VERSION 5.8 ;
BUSBITCHARS "[]" ;
DIVIDERCHAR "/" ;
UNITS
    DATABASE MICRONS 1000 ;
END UNITS

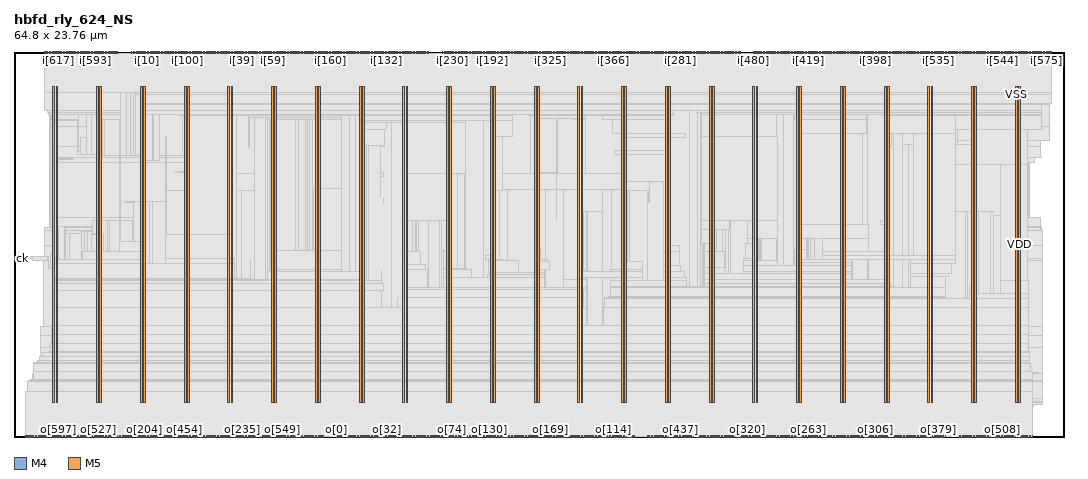
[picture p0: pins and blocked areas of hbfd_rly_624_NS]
MACRO hbfd_rly_624_NS
  FOREIGN hbfd_rly_624_NS 0 0 ;
  CLASS BLOCK ;
  SIZE 64.8 BY 23.76 ;
  PIN ck
    DIRECTION INPUT ;
    USE SIGNAL ;
    PORT
      LAYER M4 ;
        RECT  0 10.992 0.084 11.016 ;
    END
  END ck
  PIN i[0]
    DIRECTION INPUT ;
    USE SIGNAL ;
    PORT
      LAYER M5 ;
        RECT  7.248 23.676 7.272 23.76 ;
    END
  END i[0]
  PIN i[100]
    DIRECTION INPUT ;
    USE SIGNAL ;
    PORT
      LAYER M5 ;
        RECT  10.704 23.676 10.728 23.76 ;
    END
  END i[100]
  PIN i[101]
    DIRECTION INPUT ;
    USE SIGNAL ;
    PORT
      LAYER M5 ;
        RECT  10.8 23.676 10.824 23.76 ;
    END
  END i[101]
  PIN i[102]
    DIRECTION INPUT ;
    USE SIGNAL ;
    PORT
      LAYER M5 ;
        RECT  10.896 23.676 10.92 23.76 ;
    END
  END i[102]
  PIN i[103]
    DIRECTION INPUT ;
    USE SIGNAL ;
    PORT
      LAYER M5 ;
        RECT  10.992 23.676 11.016 23.76 ;
    END
  END i[103]
  PIN i[104]
    DIRECTION INPUT ;
    USE SIGNAL ;
    PORT
      LAYER M5 ;
        RECT  11.088 23.676 11.112 23.76 ;
    END
  END i[104]
  PIN i[105]
    DIRECTION INPUT ;
    USE SIGNAL ;
    PORT
      LAYER M5 ;
        RECT  11.184 23.676 11.208 23.76 ;
    END
  END i[105]
  PIN i[106]
    DIRECTION INPUT ;
    USE SIGNAL ;
    PORT
      LAYER M5 ;
        RECT  11.28 23.676 11.304 23.76 ;
    END
  END i[106]
  PIN i[107]
    DIRECTION INPUT ;
    USE SIGNAL ;
    PORT
      LAYER M5 ;
        RECT  11.376 23.676 11.4 23.76 ;
    END
  END i[107]
  PIN i[108]
    DIRECTION INPUT ;
    USE SIGNAL ;
    PORT
      LAYER M5 ;
        RECT  11.472 23.676 11.496 23.76 ;
    END
  END i[108]
  PIN i[109]
    DIRECTION INPUT ;
    USE SIGNAL ;
    PORT
      LAYER M5 ;
        RECT  11.568 23.676 11.592 23.76 ;
    END
  END i[109]
  PIN i[10]
    DIRECTION INPUT ;
    USE SIGNAL ;
    PORT
      LAYER M5 ;
        RECT  8.208 23.676 8.232 23.76 ;
    END
  END i[10]
  PIN i[110]
    DIRECTION INPUT ;
    USE SIGNAL ;
    PORT
      LAYER M5 ;
        RECT  11.664 23.676 11.688 23.76 ;
    END
  END i[110]
  PIN i[111]
    DIRECTION INPUT ;
    USE SIGNAL ;
    PORT
      LAYER M5 ;
        RECT  11.76 23.676 11.784 23.76 ;
    END
  END i[111]
  PIN i[112]
    DIRECTION INPUT ;
    USE SIGNAL ;
    PORT
      LAYER M5 ;
        RECT  11.856 23.676 11.88 23.76 ;
    END
  END i[112]
  PIN i[113]
    DIRECTION INPUT ;
    USE SIGNAL ;
    PORT
      LAYER M5 ;
        RECT  11.952 23.676 11.976 23.76 ;
    END
  END i[113]
  PIN i[114]
    DIRECTION INPUT ;
    USE SIGNAL ;
    PORT
      LAYER M5 ;
        RECT  12.048 23.676 12.072 23.76 ;
    END
  END i[114]
  PIN i[115]
    DIRECTION INPUT ;
    USE SIGNAL ;
    PORT
      LAYER M5 ;
        RECT  12.144 23.676 12.168 23.76 ;
    END
  END i[115]
  PIN i[116]
    DIRECTION INPUT ;
    USE SIGNAL ;
    PORT
      LAYER M5 ;
        RECT  12.24 23.676 12.264 23.76 ;
    END
  END i[116]
  PIN i[117]
    DIRECTION INPUT ;
    USE SIGNAL ;
    PORT
      LAYER M5 ;
        RECT  12.336 23.676 12.36 23.76 ;
    END
  END i[117]
  PIN i[118]
    DIRECTION INPUT ;
    USE SIGNAL ;
    PORT
      LAYER M5 ;
        RECT  12.432 23.676 12.456 23.76 ;
    END
  END i[118]
  PIN i[119]
    DIRECTION INPUT ;
    USE SIGNAL ;
    PORT
      LAYER M5 ;
        RECT  12.528 23.676 12.552 23.76 ;
    END
  END i[119]
  PIN i[11]
    DIRECTION INPUT ;
    USE SIGNAL ;
    PORT
      LAYER M5 ;
        RECT  8.304 23.676 8.328 23.76 ;
    END
  END i[11]
  PIN i[120]
    DIRECTION INPUT ;
    USE SIGNAL ;
    PORT
      LAYER M5 ;
        RECT  12.624 23.676 12.648 23.76 ;
    END
  END i[120]
  PIN i[121]
    DIRECTION INPUT ;
    USE SIGNAL ;
    PORT
      LAYER M5 ;
        RECT  12.72 23.676 12.744 23.76 ;
    END
  END i[121]
  PIN i[122]
    DIRECTION INPUT ;
    USE SIGNAL ;
    PORT
      LAYER M5 ;
        RECT  12.816 23.676 12.84 23.76 ;
    END
  END i[122]
  PIN i[123]
    DIRECTION INPUT ;
    USE SIGNAL ;
    PORT
      LAYER M5 ;
        RECT  12.912 23.676 12.936 23.76 ;
    END
  END i[123]
  PIN i[124]
    DIRECTION INPUT ;
    USE SIGNAL ;
    PORT
      LAYER M5 ;
        RECT  13.008 23.676 13.032 23.76 ;
    END
  END i[124]
  PIN i[125]
    DIRECTION INPUT ;
    USE SIGNAL ;
    PORT
      LAYER M5 ;
        RECT  13.104 23.676 13.128 23.76 ;
    END
  END i[125]
  PIN i[126]
    DIRECTION INPUT ;
    USE SIGNAL ;
    PORT
      LAYER M5 ;
        RECT  13.2 23.676 13.224 23.76 ;
    END
  END i[126]
  PIN i[127]
    DIRECTION INPUT ;
    USE SIGNAL ;
    PORT
      LAYER M5 ;
        RECT  13.296 23.676 13.32 23.76 ;
    END
  END i[127]
  PIN i[128]
    DIRECTION INPUT ;
    USE SIGNAL ;
    PORT
      LAYER M5 ;
        RECT  22.608 23.676 22.632 23.76 ;
    END
  END i[128]
  PIN i[129]
    DIRECTION INPUT ;
    USE SIGNAL ;
    PORT
      LAYER M5 ;
        RECT  22.704 23.676 22.728 23.76 ;
    END
  END i[129]
  PIN i[12]
    DIRECTION INPUT ;
    USE SIGNAL ;
    PORT
      LAYER M5 ;
        RECT  8.4 23.676 8.424 23.76 ;
    END
  END i[12]
  PIN i[130]
    DIRECTION INPUT ;
    USE SIGNAL ;
    PORT
      LAYER M5 ;
        RECT  22.8 23.676 22.824 23.76 ;
    END
  END i[130]
  PIN i[131]
    DIRECTION INPUT ;
    USE SIGNAL ;
    PORT
      LAYER M5 ;
        RECT  22.896 23.676 22.92 23.76 ;
    END
  END i[131]
  PIN i[132]
    DIRECTION INPUT ;
    USE SIGNAL ;
    PORT
      LAYER M5 ;
        RECT  22.992 23.676 23.016 23.76 ;
    END
  END i[132]
  PIN i[133]
    DIRECTION INPUT ;
    USE SIGNAL ;
    PORT
      LAYER M5 ;
        RECT  23.088 23.676 23.112 23.76 ;
    END
  END i[133]
  PIN i[134]
    DIRECTION INPUT ;
    USE SIGNAL ;
    PORT
      LAYER M5 ;
        RECT  23.184 23.676 23.208 23.76 ;
    END
  END i[134]
  PIN i[135]
    DIRECTION INPUT ;
    USE SIGNAL ;
    PORT
      LAYER M5 ;
        RECT  23.28 23.676 23.304 23.76 ;
    END
  END i[135]
  PIN i[136]
    DIRECTION INPUT ;
    USE SIGNAL ;
    PORT
      LAYER M5 ;
        RECT  23.376 23.676 23.4 23.76 ;
    END
  END i[136]
  PIN i[137]
    DIRECTION INPUT ;
    USE SIGNAL ;
    PORT
      LAYER M5 ;
        RECT  23.472 23.676 23.496 23.76 ;
    END
  END i[137]
  PIN i[138]
    DIRECTION INPUT ;
    USE SIGNAL ;
    PORT
      LAYER M5 ;
        RECT  23.568 23.676 23.592 23.76 ;
    END
  END i[138]
  PIN i[139]
    DIRECTION INPUT ;
    USE SIGNAL ;
    PORT
      LAYER M5 ;
        RECT  23.664 23.676 23.688 23.76 ;
    END
  END i[139]
  PIN i[13]
    DIRECTION INPUT ;
    USE SIGNAL ;
    PORT
      LAYER M5 ;
        RECT  8.496 23.676 8.52 23.76 ;
    END
  END i[13]
  PIN i[140]
    DIRECTION INPUT ;
    USE SIGNAL ;
    PORT
      LAYER M5 ;
        RECT  23.76 23.676 23.784 23.76 ;
    END
  END i[140]
  PIN i[141]
    DIRECTION INPUT ;
    USE SIGNAL ;
    PORT
      LAYER M5 ;
        RECT  23.856 23.676 23.88 23.76 ;
    END
  END i[141]
  PIN i[142]
    DIRECTION INPUT ;
    USE SIGNAL ;
    PORT
      LAYER M5 ;
        RECT  23.952 23.676 23.976 23.76 ;
    END
  END i[142]
  PIN i[143]
    DIRECTION INPUT ;
    USE SIGNAL ;
    PORT
      LAYER M5 ;
        RECT  24.048 23.676 24.072 23.76 ;
    END
  END i[143]
  PIN i[144]
    DIRECTION INPUT ;
    USE SIGNAL ;
    PORT
      LAYER M5 ;
        RECT  24.144 23.676 24.168 23.76 ;
    END
  END i[144]
  PIN i[145]
    DIRECTION INPUT ;
    USE SIGNAL ;
    PORT
      LAYER M5 ;
        RECT  24.24 23.676 24.264 23.76 ;
    END
  END i[145]
  PIN i[146]
    DIRECTION INPUT ;
    USE SIGNAL ;
    PORT
      LAYER M5 ;
        RECT  24.336 23.676 24.36 23.76 ;
    END
  END i[146]
  PIN i[147]
    DIRECTION INPUT ;
    USE SIGNAL ;
    PORT
      LAYER M5 ;
        RECT  24.432 23.676 24.456 23.76 ;
    END
  END i[147]
  PIN i[148]
    DIRECTION INPUT ;
    USE SIGNAL ;
    PORT
      LAYER M5 ;
        RECT  24.528 23.676 24.552 23.76 ;
    END
  END i[148]
  PIN i[149]
    DIRECTION INPUT ;
    USE SIGNAL ;
    PORT
      LAYER M5 ;
        RECT  24.624 23.676 24.648 23.76 ;
    END
  END i[149]
  PIN i[14]
    DIRECTION INPUT ;
    USE SIGNAL ;
    PORT
      LAYER M5 ;
        RECT  8.592 23.676 8.616 23.76 ;
    END
  END i[14]
  PIN i[150]
    DIRECTION INPUT ;
    USE SIGNAL ;
    PORT
      LAYER M5 ;
        RECT  24.72 23.676 24.744 23.76 ;
    END
  END i[150]
  PIN i[151]
    DIRECTION INPUT ;
    USE SIGNAL ;
    PORT
      LAYER M5 ;
        RECT  24.816 23.676 24.84 23.76 ;
    END
  END i[151]
  PIN i[152]
    DIRECTION INPUT ;
    USE SIGNAL ;
    PORT
      LAYER M5 ;
        RECT  24.912 23.676 24.936 23.76 ;
    END
  END i[152]
  PIN i[153]
    DIRECTION INPUT ;
    USE SIGNAL ;
    PORT
      LAYER M5 ;
        RECT  25.008 23.676 25.032 23.76 ;
    END
  END i[153]
  PIN i[154]
    DIRECTION INPUT ;
    USE SIGNAL ;
    PORT
      LAYER M5 ;
        RECT  25.104 23.676 25.128 23.76 ;
    END
  END i[154]
  PIN i[155]
    DIRECTION INPUT ;
    USE SIGNAL ;
    PORT
      LAYER M5 ;
        RECT  25.2 23.676 25.224 23.76 ;
    END
  END i[155]
  PIN i[156]
    DIRECTION INPUT ;
    USE SIGNAL ;
    PORT
      LAYER M5 ;
        RECT  25.296 23.676 25.32 23.76 ;
    END
  END i[156]
  PIN i[157]
    DIRECTION INPUT ;
    USE SIGNAL ;
    PORT
      LAYER M5 ;
        RECT  25.392 23.676 25.416 23.76 ;
    END
  END i[157]
  PIN i[158]
    DIRECTION INPUT ;
    USE SIGNAL ;
    PORT
      LAYER M5 ;
        RECT  25.488 23.676 25.512 23.76 ;
    END
  END i[158]
  PIN i[159]
    DIRECTION INPUT ;
    USE SIGNAL ;
    PORT
      LAYER M5 ;
        RECT  25.584 23.676 25.608 23.76 ;
    END
  END i[159]
  PIN i[15]
    DIRECTION INPUT ;
    USE SIGNAL ;
    PORT
      LAYER M5 ;
        RECT  8.688 23.676 8.712 23.76 ;
    END
  END i[15]
  PIN i[160]
    DIRECTION INPUT ;
    USE SIGNAL ;
    PORT
      LAYER M5 ;
        RECT  19.536 23.676 19.56 23.76 ;
    END
  END i[160]
  PIN i[161]
    DIRECTION INPUT ;
    USE SIGNAL ;
    PORT
      LAYER M5 ;
        RECT  19.632 23.676 19.656 23.76 ;
    END
  END i[161]
  PIN i[162]
    DIRECTION INPUT ;
    USE SIGNAL ;
    PORT
      LAYER M5 ;
        RECT  19.728 23.676 19.752 23.76 ;
    END
  END i[162]
  PIN i[163]
    DIRECTION INPUT ;
    USE SIGNAL ;
    PORT
      LAYER M5 ;
        RECT  19.824 23.676 19.848 23.76 ;
    END
  END i[163]
  PIN i[164]
    DIRECTION INPUT ;
    USE SIGNAL ;
    PORT
      LAYER M5 ;
        RECT  19.92 23.676 19.944 23.76 ;
    END
  END i[164]
  PIN i[165]
    DIRECTION INPUT ;
    USE SIGNAL ;
    PORT
      LAYER M5 ;
        RECT  20.016 23.676 20.04 23.76 ;
    END
  END i[165]
  PIN i[166]
    DIRECTION INPUT ;
    USE SIGNAL ;
    PORT
      LAYER M5 ;
        RECT  20.112 23.676 20.136 23.76 ;
    END
  END i[166]
  PIN i[167]
    DIRECTION INPUT ;
    USE SIGNAL ;
    PORT
      LAYER M5 ;
        RECT  20.208 23.676 20.232 23.76 ;
    END
  END i[167]
  PIN i[168]
    DIRECTION INPUT ;
    USE SIGNAL ;
    PORT
      LAYER M5 ;
        RECT  20.304 23.676 20.328 23.76 ;
    END
  END i[168]
  PIN i[169]
    DIRECTION INPUT ;
    USE SIGNAL ;
    PORT
      LAYER M5 ;
        RECT  20.4 23.676 20.424 23.76 ;
    END
  END i[169]
  PIN i[16]
    DIRECTION INPUT ;
    USE SIGNAL ;
    PORT
      LAYER M5 ;
        RECT  8.784 23.676 8.808 23.76 ;
    END
  END i[16]
  PIN i[170]
    DIRECTION INPUT ;
    USE SIGNAL ;
    PORT
      LAYER M5 ;
        RECT  20.496 23.676 20.52 23.76 ;
    END
  END i[170]
  PIN i[171]
    DIRECTION INPUT ;
    USE SIGNAL ;
    PORT
      LAYER M5 ;
        RECT  20.592 23.676 20.616 23.76 ;
    END
  END i[171]
  PIN i[172]
    DIRECTION INPUT ;
    USE SIGNAL ;
    PORT
      LAYER M5 ;
        RECT  20.688 23.676 20.712 23.76 ;
    END
  END i[172]
  PIN i[173]
    DIRECTION INPUT ;
    USE SIGNAL ;
    PORT
      LAYER M5 ;
        RECT  20.784 23.676 20.808 23.76 ;
    END
  END i[173]
  PIN i[174]
    DIRECTION INPUT ;
    USE SIGNAL ;
    PORT
      LAYER M5 ;
        RECT  20.88 23.676 20.904 23.76 ;
    END
  END i[174]
  PIN i[175]
    DIRECTION INPUT ;
    USE SIGNAL ;
    PORT
      LAYER M5 ;
        RECT  20.976 23.676 21 23.76 ;
    END
  END i[175]
  PIN i[176]
    DIRECTION INPUT ;
    USE SIGNAL ;
    PORT
      LAYER M5 ;
        RECT  21.072 23.676 21.096 23.76 ;
    END
  END i[176]
  PIN i[177]
    DIRECTION INPUT ;
    USE SIGNAL ;
    PORT
      LAYER M5 ;
        RECT  21.168 23.676 21.192 23.76 ;
    END
  END i[177]
  PIN i[178]
    DIRECTION INPUT ;
    USE SIGNAL ;
    PORT
      LAYER M5 ;
        RECT  21.264 23.676 21.288 23.76 ;
    END
  END i[178]
  PIN i[179]
    DIRECTION INPUT ;
    USE SIGNAL ;
    PORT
      LAYER M5 ;
        RECT  21.36 23.676 21.384 23.76 ;
    END
  END i[179]
  PIN i[17]
    DIRECTION INPUT ;
    USE SIGNAL ;
    PORT
      LAYER M5 ;
        RECT  8.88 23.676 8.904 23.76 ;
    END
  END i[17]
  PIN i[180]
    DIRECTION INPUT ;
    USE SIGNAL ;
    PORT
      LAYER M5 ;
        RECT  21.456 23.676 21.48 23.76 ;
    END
  END i[180]
  PIN i[181]
    DIRECTION INPUT ;
    USE SIGNAL ;
    PORT
      LAYER M5 ;
        RECT  21.552 23.676 21.576 23.76 ;
    END
  END i[181]
  PIN i[182]
    DIRECTION INPUT ;
    USE SIGNAL ;
    PORT
      LAYER M5 ;
        RECT  21.648 23.676 21.672 23.76 ;
    END
  END i[182]
  PIN i[183]
    DIRECTION INPUT ;
    USE SIGNAL ;
    PORT
      LAYER M5 ;
        RECT  21.744 23.676 21.768 23.76 ;
    END
  END i[183]
  PIN i[184]
    DIRECTION INPUT ;
    USE SIGNAL ;
    PORT
      LAYER M5 ;
        RECT  21.84 23.676 21.864 23.76 ;
    END
  END i[184]
  PIN i[185]
    DIRECTION INPUT ;
    USE SIGNAL ;
    PORT
      LAYER M5 ;
        RECT  21.936 23.676 21.96 23.76 ;
    END
  END i[185]
  PIN i[186]
    DIRECTION INPUT ;
    USE SIGNAL ;
    PORT
      LAYER M5 ;
        RECT  22.032 23.676 22.056 23.76 ;
    END
  END i[186]
  PIN i[187]
    DIRECTION INPUT ;
    USE SIGNAL ;
    PORT
      LAYER M5 ;
        RECT  22.128 23.676 22.152 23.76 ;
    END
  END i[187]
  PIN i[188]
    DIRECTION INPUT ;
    USE SIGNAL ;
    PORT
      LAYER M5 ;
        RECT  22.224 23.676 22.248 23.76 ;
    END
  END i[188]
  PIN i[189]
    DIRECTION INPUT ;
    USE SIGNAL ;
    PORT
      LAYER M5 ;
        RECT  22.32 23.676 22.344 23.76 ;
    END
  END i[189]
  PIN i[18]
    DIRECTION INPUT ;
    USE SIGNAL ;
    PORT
      LAYER M5 ;
        RECT  8.976 23.676 9 23.76 ;
    END
  END i[18]
  PIN i[190]
    DIRECTION INPUT ;
    USE SIGNAL ;
    PORT
      LAYER M5 ;
        RECT  22.416 23.676 22.44 23.76 ;
    END
  END i[190]
  PIN i[191]
    DIRECTION INPUT ;
    USE SIGNAL ;
    PORT
      LAYER M5 ;
        RECT  22.512 23.676 22.536 23.76 ;
    END
  END i[191]
  PIN i[192]
    DIRECTION INPUT ;
    USE SIGNAL ;
    PORT
      LAYER M5 ;
        RECT  29.52 23.676 29.544 23.76 ;
    END
  END i[192]
  PIN i[193]
    DIRECTION INPUT ;
    USE SIGNAL ;
    PORT
      LAYER M5 ;
        RECT  29.616 23.676 29.64 23.76 ;
    END
  END i[193]
  PIN i[194]
    DIRECTION INPUT ;
    USE SIGNAL ;
    PORT
      LAYER M5 ;
        RECT  29.712 23.676 29.736 23.76 ;
    END
  END i[194]
  PIN i[195]
    DIRECTION INPUT ;
    USE SIGNAL ;
    PORT
      LAYER M5 ;
        RECT  29.808 23.676 29.832 23.76 ;
    END
  END i[195]
  PIN i[196]
    DIRECTION INPUT ;
    USE SIGNAL ;
    PORT
      LAYER M5 ;
        RECT  29.904 23.676 29.928 23.76 ;
    END
  END i[196]
  PIN i[197]
    DIRECTION INPUT ;
    USE SIGNAL ;
    PORT
      LAYER M5 ;
        RECT  30 23.676 30.024 23.76 ;
    END
  END i[197]
  PIN i[198]
    DIRECTION INPUT ;
    USE SIGNAL ;
    PORT
      LAYER M5 ;
        RECT  30.096 23.676 30.12 23.76 ;
    END
  END i[198]
  PIN i[199]
    DIRECTION INPUT ;
    USE SIGNAL ;
    PORT
      LAYER M5 ;
        RECT  30.192 23.676 30.216 23.76 ;
    END
  END i[199]
  PIN i[19]
    DIRECTION INPUT ;
    USE SIGNAL ;
    PORT
      LAYER M5 ;
        RECT  9.072 23.676 9.096 23.76 ;
    END
  END i[19]
  PIN i[1]
    DIRECTION INPUT ;
    USE SIGNAL ;
    PORT
      LAYER M5 ;
        RECT  7.344 23.676 7.368 23.76 ;
    END
  END i[1]
  PIN i[200]
    DIRECTION INPUT ;
    USE SIGNAL ;
    PORT
      LAYER M5 ;
        RECT  30.288 23.676 30.312 23.76 ;
    END
  END i[200]
  PIN i[201]
    DIRECTION INPUT ;
    USE SIGNAL ;
    PORT
      LAYER M5 ;
        RECT  30.384 23.676 30.408 23.76 ;
    END
  END i[201]
  PIN i[202]
    DIRECTION INPUT ;
    USE SIGNAL ;
    PORT
      LAYER M5 ;
        RECT  30.48 23.676 30.504 23.76 ;
    END
  END i[202]
  PIN i[203]
    DIRECTION INPUT ;
    USE SIGNAL ;
    PORT
      LAYER M5 ;
        RECT  30.576 23.676 30.6 23.76 ;
    END
  END i[203]
  PIN i[204]
    DIRECTION INPUT ;
    USE SIGNAL ;
    PORT
      LAYER M5 ;
        RECT  30.672 23.676 30.696 23.76 ;
    END
  END i[204]
  PIN i[205]
    DIRECTION INPUT ;
    USE SIGNAL ;
    PORT
      LAYER M5 ;
        RECT  30.768 23.676 30.792 23.76 ;
    END
  END i[205]
  PIN i[206]
    DIRECTION INPUT ;
    USE SIGNAL ;
    PORT
      LAYER M5 ;
        RECT  30.864 23.676 30.888 23.76 ;
    END
  END i[206]
  PIN i[207]
    DIRECTION INPUT ;
    USE SIGNAL ;
    PORT
      LAYER M5 ;
        RECT  30.96 23.676 30.984 23.76 ;
    END
  END i[207]
  PIN i[208]
    DIRECTION INPUT ;
    USE SIGNAL ;
    PORT
      LAYER M5 ;
        RECT  31.056 23.676 31.08 23.76 ;
    END
  END i[208]
  PIN i[209]
    DIRECTION INPUT ;
    USE SIGNAL ;
    PORT
      LAYER M5 ;
        RECT  31.152 23.676 31.176 23.76 ;
    END
  END i[209]
  PIN i[20]
    DIRECTION INPUT ;
    USE SIGNAL ;
    PORT
      LAYER M5 ;
        RECT  9.168 23.676 9.192 23.76 ;
    END
  END i[20]
  PIN i[210]
    DIRECTION INPUT ;
    USE SIGNAL ;
    PORT
      LAYER M5 ;
        RECT  31.248 23.676 31.272 23.76 ;
    END
  END i[210]
  PIN i[211]
    DIRECTION INPUT ;
    USE SIGNAL ;
    PORT
      LAYER M5 ;
        RECT  31.344 23.676 31.368 23.76 ;
    END
  END i[211]
  PIN i[212]
    DIRECTION INPUT ;
    USE SIGNAL ;
    PORT
      LAYER M5 ;
        RECT  31.44 23.676 31.464 23.76 ;
    END
  END i[212]
  PIN i[213]
    DIRECTION INPUT ;
    USE SIGNAL ;
    PORT
      LAYER M5 ;
        RECT  31.536 23.676 31.56 23.76 ;
    END
  END i[213]
  PIN i[214]
    DIRECTION INPUT ;
    USE SIGNAL ;
    PORT
      LAYER M5 ;
        RECT  31.632 23.676 31.656 23.76 ;
    END
  END i[214]
  PIN i[215]
    DIRECTION INPUT ;
    USE SIGNAL ;
    PORT
      LAYER M5 ;
        RECT  31.728 23.676 31.752 23.76 ;
    END
  END i[215]
  PIN i[216]
    DIRECTION INPUT ;
    USE SIGNAL ;
    PORT
      LAYER M5 ;
        RECT  31.824 23.676 31.848 23.76 ;
    END
  END i[216]
  PIN i[217]
    DIRECTION INPUT ;
    USE SIGNAL ;
    PORT
      LAYER M5 ;
        RECT  31.92 23.676 31.944 23.76 ;
    END
  END i[217]
  PIN i[218]
    DIRECTION INPUT ;
    USE SIGNAL ;
    PORT
      LAYER M5 ;
        RECT  32.016 23.676 32.04 23.76 ;
    END
  END i[218]
  PIN i[219]
    DIRECTION INPUT ;
    USE SIGNAL ;
    PORT
      LAYER M5 ;
        RECT  32.112 23.676 32.136 23.76 ;
    END
  END i[219]
  PIN i[21]
    DIRECTION INPUT ;
    USE SIGNAL ;
    PORT
      LAYER M5 ;
        RECT  9.264 23.676 9.288 23.76 ;
    END
  END i[21]
  PIN i[220]
    DIRECTION INPUT ;
    USE SIGNAL ;
    PORT
      LAYER M5 ;
        RECT  32.208 23.676 32.232 23.76 ;
    END
  END i[220]
  PIN i[221]
    DIRECTION INPUT ;
    USE SIGNAL ;
    PORT
      LAYER M5 ;
        RECT  32.304 23.676 32.328 23.76 ;
    END
  END i[221]
  PIN i[222]
    DIRECTION INPUT ;
    USE SIGNAL ;
    PORT
      LAYER M5 ;
        RECT  32.4 23.676 32.424 23.76 ;
    END
  END i[222]
  PIN i[223]
    DIRECTION INPUT ;
    USE SIGNAL ;
    PORT
      LAYER M5 ;
        RECT  32.496 23.676 32.52 23.76 ;
    END
  END i[223]
  PIN i[224]
    DIRECTION INPUT ;
    USE SIGNAL ;
    PORT
      LAYER M5 ;
        RECT  26.448 23.676 26.472 23.76 ;
    END
  END i[224]
  PIN i[225]
    DIRECTION INPUT ;
    USE SIGNAL ;
    PORT
      LAYER M5 ;
        RECT  26.544 23.676 26.568 23.76 ;
    END
  END i[225]
  PIN i[226]
    DIRECTION INPUT ;
    USE SIGNAL ;
    PORT
      LAYER M5 ;
        RECT  26.64 23.676 26.664 23.76 ;
    END
  END i[226]
  PIN i[227]
    DIRECTION INPUT ;
    USE SIGNAL ;
    PORT
      LAYER M5 ;
        RECT  26.736 23.676 26.76 23.76 ;
    END
  END i[227]
  PIN i[228]
    DIRECTION INPUT ;
    USE SIGNAL ;
    PORT
      LAYER M5 ;
        RECT  26.832 23.676 26.856 23.76 ;
    END
  END i[228]
  PIN i[229]
    DIRECTION INPUT ;
    USE SIGNAL ;
    PORT
      LAYER M5 ;
        RECT  26.928 23.676 26.952 23.76 ;
    END
  END i[229]
  PIN i[22]
    DIRECTION INPUT ;
    USE SIGNAL ;
    PORT
      LAYER M5 ;
        RECT  9.36 23.676 9.384 23.76 ;
    END
  END i[22]
  PIN i[230]
    DIRECTION INPUT ;
    USE SIGNAL ;
    PORT
      LAYER M5 ;
        RECT  27.024 23.676 27.048 23.76 ;
    END
  END i[230]
  PIN i[231]
    DIRECTION INPUT ;
    USE SIGNAL ;
    PORT
      LAYER M5 ;
        RECT  27.12 23.676 27.144 23.76 ;
    END
  END i[231]
  PIN i[232]
    DIRECTION INPUT ;
    USE SIGNAL ;
    PORT
      LAYER M5 ;
        RECT  27.216 23.676 27.24 23.76 ;
    END
  END i[232]
  PIN i[233]
    DIRECTION INPUT ;
    USE SIGNAL ;
    PORT
      LAYER M5 ;
        RECT  27.312 23.676 27.336 23.76 ;
    END
  END i[233]
  PIN i[234]
    DIRECTION INPUT ;
    USE SIGNAL ;
    PORT
      LAYER M5 ;
        RECT  27.408 23.676 27.432 23.76 ;
    END
  END i[234]
  PIN i[235]
    DIRECTION INPUT ;
    USE SIGNAL ;
    PORT
      LAYER M5 ;
        RECT  27.504 23.676 27.528 23.76 ;
    END
  END i[235]
  PIN i[236]
    DIRECTION INPUT ;
    USE SIGNAL ;
    PORT
      LAYER M5 ;
        RECT  27.6 23.676 27.624 23.76 ;
    END
  END i[236]
  PIN i[237]
    DIRECTION INPUT ;
    USE SIGNAL ;
    PORT
      LAYER M5 ;
        RECT  27.696 23.676 27.72 23.76 ;
    END
  END i[237]
  PIN i[238]
    DIRECTION INPUT ;
    USE SIGNAL ;
    PORT
      LAYER M5 ;
        RECT  27.792 23.676 27.816 23.76 ;
    END
  END i[238]
  PIN i[239]
    DIRECTION INPUT ;
    USE SIGNAL ;
    PORT
      LAYER M5 ;
        RECT  27.888 23.676 27.912 23.76 ;
    END
  END i[239]
  PIN i[23]
    DIRECTION INPUT ;
    USE SIGNAL ;
    PORT
      LAYER M5 ;
        RECT  9.456 23.676 9.48 23.76 ;
    END
  END i[23]
  PIN i[240]
    DIRECTION INPUT ;
    USE SIGNAL ;
    PORT
      LAYER M5 ;
        RECT  27.984 23.676 28.008 23.76 ;
    END
  END i[240]
  PIN i[241]
    DIRECTION INPUT ;
    USE SIGNAL ;
    PORT
      LAYER M5 ;
        RECT  28.08 23.676 28.104 23.76 ;
    END
  END i[241]
  PIN i[242]
    DIRECTION INPUT ;
    USE SIGNAL ;
    PORT
      LAYER M5 ;
        RECT  28.176 23.676 28.2 23.76 ;
    END
  END i[242]
  PIN i[243]
    DIRECTION INPUT ;
    USE SIGNAL ;
    PORT
      LAYER M5 ;
        RECT  28.272 23.676 28.296 23.76 ;
    END
  END i[243]
  PIN i[244]
    DIRECTION INPUT ;
    USE SIGNAL ;
    PORT
      LAYER M5 ;
        RECT  28.368 23.676 28.392 23.76 ;
    END
  END i[244]
  PIN i[245]
    DIRECTION INPUT ;
    USE SIGNAL ;
    PORT
      LAYER M5 ;
        RECT  28.464 23.676 28.488 23.76 ;
    END
  END i[245]
  PIN i[246]
    DIRECTION INPUT ;
    USE SIGNAL ;
    PORT
      LAYER M5 ;
        RECT  28.56 23.676 28.584 23.76 ;
    END
  END i[246]
  PIN i[247]
    DIRECTION INPUT ;
    USE SIGNAL ;
    PORT
      LAYER M5 ;
        RECT  28.656 23.676 28.68 23.76 ;
    END
  END i[247]
  PIN i[248]
    DIRECTION INPUT ;
    USE SIGNAL ;
    PORT
      LAYER M5 ;
        RECT  28.752 23.676 28.776 23.76 ;
    END
  END i[248]
  PIN i[249]
    DIRECTION INPUT ;
    USE SIGNAL ;
    PORT
      LAYER M5 ;
        RECT  28.848 23.676 28.872 23.76 ;
    END
  END i[249]
  PIN i[24]
    DIRECTION INPUT ;
    USE SIGNAL ;
    PORT
      LAYER M5 ;
        RECT  9.552 23.676 9.576 23.76 ;
    END
  END i[24]
  PIN i[250]
    DIRECTION INPUT ;
    USE SIGNAL ;
    PORT
      LAYER M5 ;
        RECT  28.944 23.676 28.968 23.76 ;
    END
  END i[250]
  PIN i[251]
    DIRECTION INPUT ;
    USE SIGNAL ;
    PORT
      LAYER M5 ;
        RECT  29.04 23.676 29.064 23.76 ;
    END
  END i[251]
  PIN i[252]
    DIRECTION INPUT ;
    USE SIGNAL ;
    PORT
      LAYER M5 ;
        RECT  29.136 23.676 29.16 23.76 ;
    END
  END i[252]
  PIN i[253]
    DIRECTION INPUT ;
    USE SIGNAL ;
    PORT
      LAYER M5 ;
        RECT  29.232 23.676 29.256 23.76 ;
    END
  END i[253]
  PIN i[254]
    DIRECTION INPUT ;
    USE SIGNAL ;
    PORT
      LAYER M5 ;
        RECT  29.328 23.676 29.352 23.76 ;
    END
  END i[254]
  PIN i[255]
    DIRECTION INPUT ;
    USE SIGNAL ;
    PORT
      LAYER M5 ;
        RECT  29.424 23.676 29.448 23.76 ;
    END
  END i[255]
  PIN i[256]
    DIRECTION INPUT ;
    USE SIGNAL ;
    PORT
      LAYER M5 ;
        RECT  38.736 23.676 38.76 23.76 ;
    END
  END i[256]
  PIN i[257]
    DIRECTION INPUT ;
    USE SIGNAL ;
    PORT
      LAYER M5 ;
        RECT  38.832 23.676 38.856 23.76 ;
    END
  END i[257]
  PIN i[258]
    DIRECTION INPUT ;
    USE SIGNAL ;
    PORT
      LAYER M5 ;
        RECT  38.928 23.676 38.952 23.76 ;
    END
  END i[258]
  PIN i[259]
    DIRECTION INPUT ;
    USE SIGNAL ;
    PORT
      LAYER M5 ;
        RECT  39.024 23.676 39.048 23.76 ;
    END
  END i[259]
  PIN i[25]
    DIRECTION INPUT ;
    USE SIGNAL ;
    PORT
      LAYER M5 ;
        RECT  9.648 23.676 9.672 23.76 ;
    END
  END i[25]
  PIN i[260]
    DIRECTION INPUT ;
    USE SIGNAL ;
    PORT
      LAYER M5 ;
        RECT  39.12 23.676 39.144 23.76 ;
    END
  END i[260]
  PIN i[261]
    DIRECTION INPUT ;
    USE SIGNAL ;
    PORT
      LAYER M5 ;
        RECT  39.216 23.676 39.24 23.76 ;
    END
  END i[261]
  PIN i[262]
    DIRECTION INPUT ;
    USE SIGNAL ;
    PORT
      LAYER M5 ;
        RECT  39.312 23.676 39.336 23.76 ;
    END
  END i[262]
  PIN i[263]
    DIRECTION INPUT ;
    USE SIGNAL ;
    PORT
      LAYER M5 ;
        RECT  39.408 23.676 39.432 23.76 ;
    END
  END i[263]
  PIN i[264]
    DIRECTION INPUT ;
    USE SIGNAL ;
    PORT
      LAYER M5 ;
        RECT  39.504 23.676 39.528 23.76 ;
    END
  END i[264]
  PIN i[265]
    DIRECTION INPUT ;
    USE SIGNAL ;
    PORT
      LAYER M5 ;
        RECT  39.6 23.676 39.624 23.76 ;
    END
  END i[265]
  PIN i[266]
    DIRECTION INPUT ;
    USE SIGNAL ;
    PORT
      LAYER M5 ;
        RECT  39.696 23.676 39.72 23.76 ;
    END
  END i[266]
  PIN i[267]
    DIRECTION INPUT ;
    USE SIGNAL ;
    PORT
      LAYER M5 ;
        RECT  39.792 23.676 39.816 23.76 ;
    END
  END i[267]
  PIN i[268]
    DIRECTION INPUT ;
    USE SIGNAL ;
    PORT
      LAYER M5 ;
        RECT  39.888 23.676 39.912 23.76 ;
    END
  END i[268]
  PIN i[269]
    DIRECTION INPUT ;
    USE SIGNAL ;
    PORT
      LAYER M5 ;
        RECT  39.984 23.676 40.008 23.76 ;
    END
  END i[269]
  PIN i[26]
    DIRECTION INPUT ;
    USE SIGNAL ;
    PORT
      LAYER M5 ;
        RECT  9.744 23.676 9.768 23.76 ;
    END
  END i[26]
  PIN i[270]
    DIRECTION INPUT ;
    USE SIGNAL ;
    PORT
      LAYER M5 ;
        RECT  40.08 23.676 40.104 23.76 ;
    END
  END i[270]
  PIN i[271]
    DIRECTION INPUT ;
    USE SIGNAL ;
    PORT
      LAYER M5 ;
        RECT  40.176 23.676 40.2 23.76 ;
    END
  END i[271]
  PIN i[272]
    DIRECTION INPUT ;
    USE SIGNAL ;
    PORT
      LAYER M5 ;
        RECT  40.272 23.676 40.296 23.76 ;
    END
  END i[272]
  PIN i[273]
    DIRECTION INPUT ;
    USE SIGNAL ;
    PORT
      LAYER M5 ;
        RECT  40.368 23.676 40.392 23.76 ;
    END
  END i[273]
  PIN i[274]
    DIRECTION INPUT ;
    USE SIGNAL ;
    PORT
      LAYER M5 ;
        RECT  40.464 23.676 40.488 23.76 ;
    END
  END i[274]
  PIN i[275]
    DIRECTION INPUT ;
    USE SIGNAL ;
    PORT
      LAYER M5 ;
        RECT  40.56 23.676 40.584 23.76 ;
    END
  END i[275]
  PIN i[276]
    DIRECTION INPUT ;
    USE SIGNAL ;
    PORT
      LAYER M5 ;
        RECT  40.656 23.676 40.68 23.76 ;
    END
  END i[276]
  PIN i[277]
    DIRECTION INPUT ;
    USE SIGNAL ;
    PORT
      LAYER M5 ;
        RECT  40.752 23.676 40.776 23.76 ;
    END
  END i[277]
  PIN i[278]
    DIRECTION INPUT ;
    USE SIGNAL ;
    PORT
      LAYER M5 ;
        RECT  40.848 23.676 40.872 23.76 ;
    END
  END i[278]
  PIN i[279]
    DIRECTION INPUT ;
    USE SIGNAL ;
    PORT
      LAYER M5 ;
        RECT  40.944 23.676 40.968 23.76 ;
    END
  END i[279]
  PIN i[27]
    DIRECTION INPUT ;
    USE SIGNAL ;
    PORT
      LAYER M5 ;
        RECT  9.84 23.676 9.864 23.76 ;
    END
  END i[27]
  PIN i[280]
    DIRECTION INPUT ;
    USE SIGNAL ;
    PORT
      LAYER M5 ;
        RECT  41.04 23.676 41.064 23.76 ;
    END
  END i[280]
  PIN i[281]
    DIRECTION INPUT ;
    USE SIGNAL ;
    PORT
      LAYER M5 ;
        RECT  41.136 23.676 41.16 23.76 ;
    END
  END i[281]
  PIN i[282]
    DIRECTION INPUT ;
    USE SIGNAL ;
    PORT
      LAYER M5 ;
        RECT  41.232 23.676 41.256 23.76 ;
    END
  END i[282]
  PIN i[283]
    DIRECTION INPUT ;
    USE SIGNAL ;
    PORT
      LAYER M5 ;
        RECT  41.328 23.676 41.352 23.76 ;
    END
  END i[283]
  PIN i[284]
    DIRECTION INPUT ;
    USE SIGNAL ;
    PORT
      LAYER M5 ;
        RECT  41.424 23.676 41.448 23.76 ;
    END
  END i[284]
  PIN i[285]
    DIRECTION INPUT ;
    USE SIGNAL ;
    PORT
      LAYER M5 ;
        RECT  41.52 23.676 41.544 23.76 ;
    END
  END i[285]
  PIN i[286]
    DIRECTION INPUT ;
    USE SIGNAL ;
    PORT
      LAYER M5 ;
        RECT  41.616 23.676 41.64 23.76 ;
    END
  END i[286]
  PIN i[287]
    DIRECTION INPUT ;
    USE SIGNAL ;
    PORT
      LAYER M5 ;
        RECT  41.712 23.676 41.736 23.76 ;
    END
  END i[287]
  PIN i[288]
    DIRECTION INPUT ;
    USE SIGNAL ;
    PORT
      LAYER M5 ;
        RECT  41.808 23.676 41.832 23.76 ;
    END
  END i[288]
  PIN i[289]
    DIRECTION INPUT ;
    USE SIGNAL ;
    PORT
      LAYER M5 ;
        RECT  41.904 23.676 41.928 23.76 ;
    END
  END i[289]
  PIN i[28]
    DIRECTION INPUT ;
    USE SIGNAL ;
    PORT
      LAYER M5 ;
        RECT  9.936 23.676 9.96 23.76 ;
    END
  END i[28]
  PIN i[290]
    DIRECTION INPUT ;
    USE SIGNAL ;
    PORT
      LAYER M5 ;
        RECT  42 23.676 42.024 23.76 ;
    END
  END i[290]
  PIN i[291]
    DIRECTION INPUT ;
    USE SIGNAL ;
    PORT
      LAYER M5 ;
        RECT  42.096 23.676 42.12 23.76 ;
    END
  END i[291]
  PIN i[292]
    DIRECTION INPUT ;
    USE SIGNAL ;
    PORT
      LAYER M5 ;
        RECT  42.192 23.676 42.216 23.76 ;
    END
  END i[292]
  PIN i[293]
    DIRECTION INPUT ;
    USE SIGNAL ;
    PORT
      LAYER M5 ;
        RECT  42.288 23.676 42.312 23.76 ;
    END
  END i[293]
  PIN i[294]
    DIRECTION INPUT ;
    USE SIGNAL ;
    PORT
      LAYER M5 ;
        RECT  42.384 23.676 42.408 23.76 ;
    END
  END i[294]
  PIN i[295]
    DIRECTION INPUT ;
    USE SIGNAL ;
    PORT
      LAYER M5 ;
        RECT  42.48 23.676 42.504 23.76 ;
    END
  END i[295]
  PIN i[296]
    DIRECTION INPUT ;
    USE SIGNAL ;
    PORT
      LAYER M5 ;
        RECT  42.576 23.676 42.6 23.76 ;
    END
  END i[296]
  PIN i[297]
    DIRECTION INPUT ;
    USE SIGNAL ;
    PORT
      LAYER M5 ;
        RECT  42.672 23.676 42.696 23.76 ;
    END
  END i[297]
  PIN i[298]
    DIRECTION INPUT ;
    USE SIGNAL ;
    PORT
      LAYER M5 ;
        RECT  42.768 23.676 42.792 23.76 ;
    END
  END i[298]
  PIN i[299]
    DIRECTION INPUT ;
    USE SIGNAL ;
    PORT
      LAYER M5 ;
        RECT  42.864 23.676 42.888 23.76 ;
    END
  END i[299]
  PIN i[29]
    DIRECTION INPUT ;
    USE SIGNAL ;
    PORT
      LAYER M5 ;
        RECT  10.032 23.676 10.056 23.76 ;
    END
  END i[29]
  PIN i[2]
    DIRECTION INPUT ;
    USE SIGNAL ;
    PORT
      LAYER M5 ;
        RECT  7.44 23.676 7.464 23.76 ;
    END
  END i[2]
  PIN i[300]
    DIRECTION INPUT ;
    USE SIGNAL ;
    PORT
      LAYER M5 ;
        RECT  42.96 23.676 42.984 23.76 ;
    END
  END i[300]
  PIN i[301]
    DIRECTION INPUT ;
    USE SIGNAL ;
    PORT
      LAYER M5 ;
        RECT  43.056 23.676 43.08 23.76 ;
    END
  END i[301]
  PIN i[302]
    DIRECTION INPUT ;
    USE SIGNAL ;
    PORT
      LAYER M5 ;
        RECT  43.152 23.676 43.176 23.76 ;
    END
  END i[302]
  PIN i[303]
    DIRECTION INPUT ;
    USE SIGNAL ;
    PORT
      LAYER M5 ;
        RECT  43.248 23.676 43.272 23.76 ;
    END
  END i[303]
  PIN i[304]
    DIRECTION INPUT ;
    USE SIGNAL ;
    PORT
      LAYER M5 ;
        RECT  43.344 23.676 43.368 23.76 ;
    END
  END i[304]
  PIN i[305]
    DIRECTION INPUT ;
    USE SIGNAL ;
    PORT
      LAYER M5 ;
        RECT  43.44 23.676 43.464 23.76 ;
    END
  END i[305]
  PIN i[306]
    DIRECTION INPUT ;
    USE SIGNAL ;
    PORT
      LAYER M5 ;
        RECT  43.536 23.676 43.56 23.76 ;
    END
  END i[306]
  PIN i[307]
    DIRECTION INPUT ;
    USE SIGNAL ;
    PORT
      LAYER M5 ;
        RECT  43.632 23.676 43.656 23.76 ;
    END
  END i[307]
  PIN i[308]
    DIRECTION INPUT ;
    USE SIGNAL ;
    PORT
      LAYER M5 ;
        RECT  43.728 23.676 43.752 23.76 ;
    END
  END i[308]
  PIN i[309]
    DIRECTION INPUT ;
    USE SIGNAL ;
    PORT
      LAYER M5 ;
        RECT  43.824 23.676 43.848 23.76 ;
    END
  END i[309]
  PIN i[30]
    DIRECTION INPUT ;
    USE SIGNAL ;
    PORT
      LAYER M5 ;
        RECT  10.128 23.676 10.152 23.76 ;
    END
  END i[30]
  PIN i[310]
    DIRECTION INPUT ;
    USE SIGNAL ;
    PORT
      LAYER M5 ;
        RECT  43.92 23.676 43.944 23.76 ;
    END
  END i[310]
  PIN i[311]
    DIRECTION INPUT ;
    USE SIGNAL ;
    PORT
      LAYER M5 ;
        RECT  44.016 23.676 44.04 23.76 ;
    END
  END i[311]
  PIN i[312]
    DIRECTION INPUT ;
    USE SIGNAL ;
    PORT
      LAYER M5 ;
        RECT  44.112 23.676 44.136 23.76 ;
    END
  END i[312]
  PIN i[313]
    DIRECTION INPUT ;
    USE SIGNAL ;
    PORT
      LAYER M5 ;
        RECT  44.208 23.676 44.232 23.76 ;
    END
  END i[313]
  PIN i[314]
    DIRECTION INPUT ;
    USE SIGNAL ;
    PORT
      LAYER M5 ;
        RECT  44.304 23.676 44.328 23.76 ;
    END
  END i[314]
  PIN i[315]
    DIRECTION INPUT ;
    USE SIGNAL ;
    PORT
      LAYER M5 ;
        RECT  44.4 23.676 44.424 23.76 ;
    END
  END i[315]
  PIN i[316]
    DIRECTION INPUT ;
    USE SIGNAL ;
    PORT
      LAYER M5 ;
        RECT  44.496 23.676 44.52 23.76 ;
    END
  END i[316]
  PIN i[317]
    DIRECTION INPUT ;
    USE SIGNAL ;
    PORT
      LAYER M5 ;
        RECT  44.592 23.676 44.616 23.76 ;
    END
  END i[317]
  PIN i[318]
    DIRECTION INPUT ;
    USE SIGNAL ;
    PORT
      LAYER M5 ;
        RECT  44.688 23.676 44.712 23.76 ;
    END
  END i[318]
  PIN i[319]
    DIRECTION INPUT ;
    USE SIGNAL ;
    PORT
      LAYER M5 ;
        RECT  44.784 23.676 44.808 23.76 ;
    END
  END i[319]
  PIN i[31]
    DIRECTION INPUT ;
    USE SIGNAL ;
    PORT
      LAYER M5 ;
        RECT  10.224 23.676 10.248 23.76 ;
    END
  END i[31]
  PIN i[320]
    DIRECTION INPUT ;
    USE SIGNAL ;
    PORT
      LAYER M5 ;
        RECT  32.592 23.676 32.616 23.76 ;
    END
  END i[320]
  PIN i[321]
    DIRECTION INPUT ;
    USE SIGNAL ;
    PORT
      LAYER M5 ;
        RECT  32.688 23.676 32.712 23.76 ;
    END
  END i[321]
  PIN i[322]
    DIRECTION INPUT ;
    USE SIGNAL ;
    PORT
      LAYER M5 ;
        RECT  32.784 23.676 32.808 23.76 ;
    END
  END i[322]
  PIN i[323]
    DIRECTION INPUT ;
    USE SIGNAL ;
    PORT
      LAYER M5 ;
        RECT  32.88 23.676 32.904 23.76 ;
    END
  END i[323]
  PIN i[324]
    DIRECTION INPUT ;
    USE SIGNAL ;
    PORT
      LAYER M5 ;
        RECT  32.976 23.676 33 23.76 ;
    END
  END i[324]
  PIN i[325]
    DIRECTION INPUT ;
    USE SIGNAL ;
    PORT
      LAYER M5 ;
        RECT  33.072 23.676 33.096 23.76 ;
    END
  END i[325]
  PIN i[326]
    DIRECTION INPUT ;
    USE SIGNAL ;
    PORT
      LAYER M5 ;
        RECT  33.168 23.676 33.192 23.76 ;
    END
  END i[326]
  PIN i[327]
    DIRECTION INPUT ;
    USE SIGNAL ;
    PORT
      LAYER M5 ;
        RECT  33.264 23.676 33.288 23.76 ;
    END
  END i[327]
  PIN i[328]
    DIRECTION INPUT ;
    USE SIGNAL ;
    PORT
      LAYER M5 ;
        RECT  33.36 23.676 33.384 23.76 ;
    END
  END i[328]
  PIN i[329]
    DIRECTION INPUT ;
    USE SIGNAL ;
    PORT
      LAYER M5 ;
        RECT  33.456 23.676 33.48 23.76 ;
    END
  END i[329]
  PIN i[32]
    DIRECTION INPUT ;
    USE SIGNAL ;
    PORT
      LAYER M5 ;
        RECT  13.392 23.676 13.416 23.76 ;
    END
  END i[32]
  PIN i[330]
    DIRECTION INPUT ;
    USE SIGNAL ;
    PORT
      LAYER M5 ;
        RECT  33.552 23.676 33.576 23.76 ;
    END
  END i[330]
  PIN i[331]
    DIRECTION INPUT ;
    USE SIGNAL ;
    PORT
      LAYER M5 ;
        RECT  33.648 23.676 33.672 23.76 ;
    END
  END i[331]
  PIN i[332]
    DIRECTION INPUT ;
    USE SIGNAL ;
    PORT
      LAYER M5 ;
        RECT  33.744 23.676 33.768 23.76 ;
    END
  END i[332]
  PIN i[333]
    DIRECTION INPUT ;
    USE SIGNAL ;
    PORT
      LAYER M5 ;
        RECT  33.84 23.676 33.864 23.76 ;
    END
  END i[333]
  PIN i[334]
    DIRECTION INPUT ;
    USE SIGNAL ;
    PORT
      LAYER M5 ;
        RECT  33.936 23.676 33.96 23.76 ;
    END
  END i[334]
  PIN i[335]
    DIRECTION INPUT ;
    USE SIGNAL ;
    PORT
      LAYER M5 ;
        RECT  34.032 23.676 34.056 23.76 ;
    END
  END i[335]
  PIN i[336]
    DIRECTION INPUT ;
    USE SIGNAL ;
    PORT
      LAYER M5 ;
        RECT  34.128 23.676 34.152 23.76 ;
    END
  END i[336]
  PIN i[337]
    DIRECTION INPUT ;
    USE SIGNAL ;
    PORT
      LAYER M5 ;
        RECT  34.224 23.676 34.248 23.76 ;
    END
  END i[337]
  PIN i[338]
    DIRECTION INPUT ;
    USE SIGNAL ;
    PORT
      LAYER M5 ;
        RECT  34.32 23.676 34.344 23.76 ;
    END
  END i[338]
  PIN i[339]
    DIRECTION INPUT ;
    USE SIGNAL ;
    PORT
      LAYER M5 ;
        RECT  34.416 23.676 34.44 23.76 ;
    END
  END i[339]
  PIN i[33]
    DIRECTION INPUT ;
    USE SIGNAL ;
    PORT
      LAYER M5 ;
        RECT  13.488 23.676 13.512 23.76 ;
    END
  END i[33]
  PIN i[340]
    DIRECTION INPUT ;
    USE SIGNAL ;
    PORT
      LAYER M5 ;
        RECT  34.512 23.676 34.536 23.76 ;
    END
  END i[340]
  PIN i[341]
    DIRECTION INPUT ;
    USE SIGNAL ;
    PORT
      LAYER M5 ;
        RECT  34.608 23.676 34.632 23.76 ;
    END
  END i[341]
  PIN i[342]
    DIRECTION INPUT ;
    USE SIGNAL ;
    PORT
      LAYER M5 ;
        RECT  34.704 23.676 34.728 23.76 ;
    END
  END i[342]
  PIN i[343]
    DIRECTION INPUT ;
    USE SIGNAL ;
    PORT
      LAYER M5 ;
        RECT  34.8 23.676 34.824 23.76 ;
    END
  END i[343]
  PIN i[344]
    DIRECTION INPUT ;
    USE SIGNAL ;
    PORT
      LAYER M5 ;
        RECT  34.896 23.676 34.92 23.76 ;
    END
  END i[344]
  PIN i[345]
    DIRECTION INPUT ;
    USE SIGNAL ;
    PORT
      LAYER M5 ;
        RECT  34.992 23.676 35.016 23.76 ;
    END
  END i[345]
  PIN i[346]
    DIRECTION INPUT ;
    USE SIGNAL ;
    PORT
      LAYER M5 ;
        RECT  35.088 23.676 35.112 23.76 ;
    END
  END i[346]
  PIN i[347]
    DIRECTION INPUT ;
    USE SIGNAL ;
    PORT
      LAYER M5 ;
        RECT  35.184 23.676 35.208 23.76 ;
    END
  END i[347]
  PIN i[348]
    DIRECTION INPUT ;
    USE SIGNAL ;
    PORT
      LAYER M5 ;
        RECT  35.28 23.676 35.304 23.76 ;
    END
  END i[348]
  PIN i[349]
    DIRECTION INPUT ;
    USE SIGNAL ;
    PORT
      LAYER M5 ;
        RECT  35.376 23.676 35.4 23.76 ;
    END
  END i[349]
  PIN i[34]
    DIRECTION INPUT ;
    USE SIGNAL ;
    PORT
      LAYER M5 ;
        RECT  13.584 23.676 13.608 23.76 ;
    END
  END i[34]
  PIN i[350]
    DIRECTION INPUT ;
    USE SIGNAL ;
    PORT
      LAYER M5 ;
        RECT  35.472 23.676 35.496 23.76 ;
    END
  END i[350]
  PIN i[351]
    DIRECTION INPUT ;
    USE SIGNAL ;
    PORT
      LAYER M5 ;
        RECT  35.568 23.676 35.592 23.76 ;
    END
  END i[351]
  PIN i[352]
    DIRECTION INPUT ;
    USE SIGNAL ;
    PORT
      LAYER M5 ;
        RECT  35.664 23.676 35.688 23.76 ;
    END
  END i[352]
  PIN i[353]
    DIRECTION INPUT ;
    USE SIGNAL ;
    PORT
      LAYER M5 ;
        RECT  35.76 23.676 35.784 23.76 ;
    END
  END i[353]
  PIN i[354]
    DIRECTION INPUT ;
    USE SIGNAL ;
    PORT
      LAYER M5 ;
        RECT  35.856 23.676 35.88 23.76 ;
    END
  END i[354]
  PIN i[355]
    DIRECTION INPUT ;
    USE SIGNAL ;
    PORT
      LAYER M5 ;
        RECT  35.952 23.676 35.976 23.76 ;
    END
  END i[355]
  PIN i[356]
    DIRECTION INPUT ;
    USE SIGNAL ;
    PORT
      LAYER M5 ;
        RECT  36.048 23.676 36.072 23.76 ;
    END
  END i[356]
  PIN i[357]
    DIRECTION INPUT ;
    USE SIGNAL ;
    PORT
      LAYER M5 ;
        RECT  36.144 23.676 36.168 23.76 ;
    END
  END i[357]
  PIN i[358]
    DIRECTION INPUT ;
    USE SIGNAL ;
    PORT
      LAYER M5 ;
        RECT  36.24 23.676 36.264 23.76 ;
    END
  END i[358]
  PIN i[359]
    DIRECTION INPUT ;
    USE SIGNAL ;
    PORT
      LAYER M5 ;
        RECT  36.336 23.676 36.36 23.76 ;
    END
  END i[359]
  PIN i[35]
    DIRECTION INPUT ;
    USE SIGNAL ;
    PORT
      LAYER M5 ;
        RECT  13.68 23.676 13.704 23.76 ;
    END
  END i[35]
  PIN i[360]
    DIRECTION INPUT ;
    USE SIGNAL ;
    PORT
      LAYER M5 ;
        RECT  36.432 23.676 36.456 23.76 ;
    END
  END i[360]
  PIN i[361]
    DIRECTION INPUT ;
    USE SIGNAL ;
    PORT
      LAYER M5 ;
        RECT  36.528 23.676 36.552 23.76 ;
    END
  END i[361]
  PIN i[362]
    DIRECTION INPUT ;
    USE SIGNAL ;
    PORT
      LAYER M5 ;
        RECT  36.624 23.676 36.648 23.76 ;
    END
  END i[362]
  PIN i[363]
    DIRECTION INPUT ;
    USE SIGNAL ;
    PORT
      LAYER M5 ;
        RECT  36.72 23.676 36.744 23.76 ;
    END
  END i[363]
  PIN i[364]
    DIRECTION INPUT ;
    USE SIGNAL ;
    PORT
      LAYER M5 ;
        RECT  36.816 23.676 36.84 23.76 ;
    END
  END i[364]
  PIN i[365]
    DIRECTION INPUT ;
    USE SIGNAL ;
    PORT
      LAYER M5 ;
        RECT  36.912 23.676 36.936 23.76 ;
    END
  END i[365]
  PIN i[366]
    DIRECTION INPUT ;
    USE SIGNAL ;
    PORT
      LAYER M5 ;
        RECT  37.008 23.676 37.032 23.76 ;
    END
  END i[366]
  PIN i[367]
    DIRECTION INPUT ;
    USE SIGNAL ;
    PORT
      LAYER M5 ;
        RECT  37.104 23.676 37.128 23.76 ;
    END
  END i[367]
  PIN i[368]
    DIRECTION INPUT ;
    USE SIGNAL ;
    PORT
      LAYER M5 ;
        RECT  37.2 23.676 37.224 23.76 ;
    END
  END i[368]
  PIN i[369]
    DIRECTION INPUT ;
    USE SIGNAL ;
    PORT
      LAYER M5 ;
        RECT  37.296 23.676 37.32 23.76 ;
    END
  END i[369]
  PIN i[36]
    DIRECTION INPUT ;
    USE SIGNAL ;
    PORT
      LAYER M5 ;
        RECT  13.776 23.676 13.8 23.76 ;
    END
  END i[36]
  PIN i[370]
    DIRECTION INPUT ;
    USE SIGNAL ;
    PORT
      LAYER M5 ;
        RECT  37.392 23.676 37.416 23.76 ;
    END
  END i[370]
  PIN i[371]
    DIRECTION INPUT ;
    USE SIGNAL ;
    PORT
      LAYER M5 ;
        RECT  37.488 23.676 37.512 23.76 ;
    END
  END i[371]
  PIN i[372]
    DIRECTION INPUT ;
    USE SIGNAL ;
    PORT
      LAYER M5 ;
        RECT  37.584 23.676 37.608 23.76 ;
    END
  END i[372]
  PIN i[373]
    DIRECTION INPUT ;
    USE SIGNAL ;
    PORT
      LAYER M5 ;
        RECT  37.68 23.676 37.704 23.76 ;
    END
  END i[373]
  PIN i[374]
    DIRECTION INPUT ;
    USE SIGNAL ;
    PORT
      LAYER M5 ;
        RECT  37.776 23.676 37.8 23.76 ;
    END
  END i[374]
  PIN i[375]
    DIRECTION INPUT ;
    USE SIGNAL ;
    PORT
      LAYER M5 ;
        RECT  37.872 23.676 37.896 23.76 ;
    END
  END i[375]
  PIN i[376]
    DIRECTION INPUT ;
    USE SIGNAL ;
    PORT
      LAYER M5 ;
        RECT  37.968 23.676 37.992 23.76 ;
    END
  END i[376]
  PIN i[377]
    DIRECTION INPUT ;
    USE SIGNAL ;
    PORT
      LAYER M5 ;
        RECT  38.064 23.676 38.088 23.76 ;
    END
  END i[377]
  PIN i[378]
    DIRECTION INPUT ;
    USE SIGNAL ;
    PORT
      LAYER M5 ;
        RECT  38.16 23.676 38.184 23.76 ;
    END
  END i[378]
  PIN i[379]
    DIRECTION INPUT ;
    USE SIGNAL ;
    PORT
      LAYER M5 ;
        RECT  38.256 23.676 38.28 23.76 ;
    END
  END i[379]
  PIN i[37]
    DIRECTION INPUT ;
    USE SIGNAL ;
    PORT
      LAYER M5 ;
        RECT  13.872 23.676 13.896 23.76 ;
    END
  END i[37]
  PIN i[380]
    DIRECTION INPUT ;
    USE SIGNAL ;
    PORT
      LAYER M5 ;
        RECT  38.352 23.676 38.376 23.76 ;
    END
  END i[380]
  PIN i[381]
    DIRECTION INPUT ;
    USE SIGNAL ;
    PORT
      LAYER M5 ;
        RECT  38.448 23.676 38.472 23.76 ;
    END
  END i[381]
  PIN i[382]
    DIRECTION INPUT ;
    USE SIGNAL ;
    PORT
      LAYER M5 ;
        RECT  38.544 23.676 38.568 23.76 ;
    END
  END i[382]
  PIN i[383]
    DIRECTION INPUT ;
    USE SIGNAL ;
    PORT
      LAYER M5 ;
        RECT  38.64 23.676 38.664 23.76 ;
    END
  END i[383]
  PIN i[384]
    DIRECTION INPUT ;
    USE SIGNAL ;
    PORT
      LAYER M5 ;
        RECT  51.792 23.676 51.816 23.76 ;
    END
  END i[384]
  PIN i[385]
    DIRECTION INPUT ;
    USE SIGNAL ;
    PORT
      LAYER M5 ;
        RECT  51.888 23.676 51.912 23.76 ;
    END
  END i[385]
  PIN i[386]
    DIRECTION INPUT ;
    USE SIGNAL ;
    PORT
      LAYER M5 ;
        RECT  51.984 23.676 52.008 23.76 ;
    END
  END i[386]
  PIN i[387]
    DIRECTION INPUT ;
    USE SIGNAL ;
    PORT
      LAYER M5 ;
        RECT  52.08 23.676 52.104 23.76 ;
    END
  END i[387]
  PIN i[388]
    DIRECTION INPUT ;
    USE SIGNAL ;
    PORT
      LAYER M5 ;
        RECT  52.176 23.676 52.2 23.76 ;
    END
  END i[388]
  PIN i[389]
    DIRECTION INPUT ;
    USE SIGNAL ;
    PORT
      LAYER M5 ;
        RECT  52.272 23.676 52.296 23.76 ;
    END
  END i[389]
  PIN i[38]
    DIRECTION INPUT ;
    USE SIGNAL ;
    PORT
      LAYER M5 ;
        RECT  13.968 23.676 13.992 23.76 ;
    END
  END i[38]
  PIN i[390]
    DIRECTION INPUT ;
    USE SIGNAL ;
    PORT
      LAYER M5 ;
        RECT  52.368 23.676 52.392 23.76 ;
    END
  END i[390]
  PIN i[391]
    DIRECTION INPUT ;
    USE SIGNAL ;
    PORT
      LAYER M5 ;
        RECT  52.464 23.676 52.488 23.76 ;
    END
  END i[391]
  PIN i[392]
    DIRECTION INPUT ;
    USE SIGNAL ;
    PORT
      LAYER M5 ;
        RECT  52.56 23.676 52.584 23.76 ;
    END
  END i[392]
  PIN i[393]
    DIRECTION INPUT ;
    USE SIGNAL ;
    PORT
      LAYER M5 ;
        RECT  52.656 23.676 52.68 23.76 ;
    END
  END i[393]
  PIN i[394]
    DIRECTION INPUT ;
    USE SIGNAL ;
    PORT
      LAYER M5 ;
        RECT  52.752 23.676 52.776 23.76 ;
    END
  END i[394]
  PIN i[395]
    DIRECTION INPUT ;
    USE SIGNAL ;
    PORT
      LAYER M5 ;
        RECT  52.848 23.676 52.872 23.76 ;
    END
  END i[395]
  PIN i[396]
    DIRECTION INPUT ;
    USE SIGNAL ;
    PORT
      LAYER M5 ;
        RECT  52.944 23.676 52.968 23.76 ;
    END
  END i[396]
  PIN i[397]
    DIRECTION INPUT ;
    USE SIGNAL ;
    PORT
      LAYER M5 ;
        RECT  53.04 23.676 53.064 23.76 ;
    END
  END i[397]
  PIN i[398]
    DIRECTION INPUT ;
    USE SIGNAL ;
    PORT
      LAYER M5 ;
        RECT  53.136 23.676 53.16 23.76 ;
    END
  END i[398]
  PIN i[399]
    DIRECTION INPUT ;
    USE SIGNAL ;
    PORT
      LAYER M5 ;
        RECT  53.232 23.676 53.256 23.76 ;
    END
  END i[399]
  PIN i[39]
    DIRECTION INPUT ;
    USE SIGNAL ;
    PORT
      LAYER M5 ;
        RECT  14.064 23.676 14.088 23.76 ;
    END
  END i[39]
  PIN i[3]
    DIRECTION INPUT ;
    USE SIGNAL ;
    PORT
      LAYER M5 ;
        RECT  7.536 23.676 7.56 23.76 ;
    END
  END i[3]
  PIN i[400]
    DIRECTION INPUT ;
    USE SIGNAL ;
    PORT
      LAYER M5 ;
        RECT  53.328 23.676 53.352 23.76 ;
    END
  END i[400]
  PIN i[401]
    DIRECTION INPUT ;
    USE SIGNAL ;
    PORT
      LAYER M5 ;
        RECT  53.424 23.676 53.448 23.76 ;
    END
  END i[401]
  PIN i[402]
    DIRECTION INPUT ;
    USE SIGNAL ;
    PORT
      LAYER M5 ;
        RECT  53.52 23.676 53.544 23.76 ;
    END
  END i[402]
  PIN i[403]
    DIRECTION INPUT ;
    USE SIGNAL ;
    PORT
      LAYER M5 ;
        RECT  53.616 23.676 53.64 23.76 ;
    END
  END i[403]
  PIN i[404]
    DIRECTION INPUT ;
    USE SIGNAL ;
    PORT
      LAYER M5 ;
        RECT  53.712 23.676 53.736 23.76 ;
    END
  END i[404]
  PIN i[405]
    DIRECTION INPUT ;
    USE SIGNAL ;
    PORT
      LAYER M5 ;
        RECT  53.808 23.676 53.832 23.76 ;
    END
  END i[405]
  PIN i[406]
    DIRECTION INPUT ;
    USE SIGNAL ;
    PORT
      LAYER M5 ;
        RECT  53.904 23.676 53.928 23.76 ;
    END
  END i[406]
  PIN i[407]
    DIRECTION INPUT ;
    USE SIGNAL ;
    PORT
      LAYER M5 ;
        RECT  54 23.676 54.024 23.76 ;
    END
  END i[407]
  PIN i[408]
    DIRECTION INPUT ;
    USE SIGNAL ;
    PORT
      LAYER M5 ;
        RECT  54.096 23.676 54.12 23.76 ;
    END
  END i[408]
  PIN i[409]
    DIRECTION INPUT ;
    USE SIGNAL ;
    PORT
      LAYER M5 ;
        RECT  54.192 23.676 54.216 23.76 ;
    END
  END i[409]
  PIN i[40]
    DIRECTION INPUT ;
    USE SIGNAL ;
    PORT
      LAYER M5 ;
        RECT  14.16 23.676 14.184 23.76 ;
    END
  END i[40]
  PIN i[410]
    DIRECTION INPUT ;
    USE SIGNAL ;
    PORT
      LAYER M5 ;
        RECT  54.288 23.676 54.312 23.76 ;
    END
  END i[410]
  PIN i[411]
    DIRECTION INPUT ;
    USE SIGNAL ;
    PORT
      LAYER M5 ;
        RECT  54.384 23.676 54.408 23.76 ;
    END
  END i[411]
  PIN i[412]
    DIRECTION INPUT ;
    USE SIGNAL ;
    PORT
      LAYER M5 ;
        RECT  54.48 23.676 54.504 23.76 ;
    END
  END i[412]
  PIN i[413]
    DIRECTION INPUT ;
    USE SIGNAL ;
    PORT
      LAYER M5 ;
        RECT  54.576 23.676 54.6 23.76 ;
    END
  END i[413]
  PIN i[414]
    DIRECTION INPUT ;
    USE SIGNAL ;
    PORT
      LAYER M5 ;
        RECT  54.672 23.676 54.696 23.76 ;
    END
  END i[414]
  PIN i[415]
    DIRECTION INPUT ;
    USE SIGNAL ;
    PORT
      LAYER M5 ;
        RECT  54.768 23.676 54.792 23.76 ;
    END
  END i[415]
  PIN i[416]
    DIRECTION INPUT ;
    USE SIGNAL ;
    PORT
      LAYER M5 ;
        RECT  48.72 23.676 48.744 23.76 ;
    END
  END i[416]
  PIN i[417]
    DIRECTION INPUT ;
    USE SIGNAL ;
    PORT
      LAYER M5 ;
        RECT  48.816 23.676 48.84 23.76 ;
    END
  END i[417]
  PIN i[418]
    DIRECTION INPUT ;
    USE SIGNAL ;
    PORT
      LAYER M5 ;
        RECT  48.912 23.676 48.936 23.76 ;
    END
  END i[418]
  PIN i[419]
    DIRECTION INPUT ;
    USE SIGNAL ;
    PORT
      LAYER M5 ;
        RECT  49.008 23.676 49.032 23.76 ;
    END
  END i[419]
  PIN i[41]
    DIRECTION INPUT ;
    USE SIGNAL ;
    PORT
      LAYER M5 ;
        RECT  14.256 23.676 14.28 23.76 ;
    END
  END i[41]
  PIN i[420]
    DIRECTION INPUT ;
    USE SIGNAL ;
    PORT
      LAYER M5 ;
        RECT  49.104 23.676 49.128 23.76 ;
    END
  END i[420]
  PIN i[421]
    DIRECTION INPUT ;
    USE SIGNAL ;
    PORT
      LAYER M5 ;
        RECT  49.2 23.676 49.224 23.76 ;
    END
  END i[421]
  PIN i[422]
    DIRECTION INPUT ;
    USE SIGNAL ;
    PORT
      LAYER M5 ;
        RECT  49.296 23.676 49.32 23.76 ;
    END
  END i[422]
  PIN i[423]
    DIRECTION INPUT ;
    USE SIGNAL ;
    PORT
      LAYER M5 ;
        RECT  49.392 23.676 49.416 23.76 ;
    END
  END i[423]
  PIN i[424]
    DIRECTION INPUT ;
    USE SIGNAL ;
    PORT
      LAYER M5 ;
        RECT  49.488 23.676 49.512 23.76 ;
    END
  END i[424]
  PIN i[425]
    DIRECTION INPUT ;
    USE SIGNAL ;
    PORT
      LAYER M5 ;
        RECT  49.584 23.676 49.608 23.76 ;
    END
  END i[425]
  PIN i[426]
    DIRECTION INPUT ;
    USE SIGNAL ;
    PORT
      LAYER M5 ;
        RECT  49.68 23.676 49.704 23.76 ;
    END
  END i[426]
  PIN i[427]
    DIRECTION INPUT ;
    USE SIGNAL ;
    PORT
      LAYER M5 ;
        RECT  49.776 23.676 49.8 23.76 ;
    END
  END i[427]
  PIN i[428]
    DIRECTION INPUT ;
    USE SIGNAL ;
    PORT
      LAYER M5 ;
        RECT  49.872 23.676 49.896 23.76 ;
    END
  END i[428]
  PIN i[429]
    DIRECTION INPUT ;
    USE SIGNAL ;
    PORT
      LAYER M5 ;
        RECT  49.968 23.676 49.992 23.76 ;
    END
  END i[429]
  PIN i[42]
    DIRECTION INPUT ;
    USE SIGNAL ;
    PORT
      LAYER M5 ;
        RECT  14.352 23.676 14.376 23.76 ;
    END
  END i[42]
  PIN i[430]
    DIRECTION INPUT ;
    USE SIGNAL ;
    PORT
      LAYER M5 ;
        RECT  50.064 23.676 50.088 23.76 ;
    END
  END i[430]
  PIN i[431]
    DIRECTION INPUT ;
    USE SIGNAL ;
    PORT
      LAYER M5 ;
        RECT  50.16 23.676 50.184 23.76 ;
    END
  END i[431]
  PIN i[432]
    DIRECTION INPUT ;
    USE SIGNAL ;
    PORT
      LAYER M5 ;
        RECT  50.256 23.676 50.28 23.76 ;
    END
  END i[432]
  PIN i[433]
    DIRECTION INPUT ;
    USE SIGNAL ;
    PORT
      LAYER M5 ;
        RECT  50.352 23.676 50.376 23.76 ;
    END
  END i[433]
  PIN i[434]
    DIRECTION INPUT ;
    USE SIGNAL ;
    PORT
      LAYER M5 ;
        RECT  50.448 23.676 50.472 23.76 ;
    END
  END i[434]
  PIN i[435]
    DIRECTION INPUT ;
    USE SIGNAL ;
    PORT
      LAYER M5 ;
        RECT  50.544 23.676 50.568 23.76 ;
    END
  END i[435]
  PIN i[436]
    DIRECTION INPUT ;
    USE SIGNAL ;
    PORT
      LAYER M5 ;
        RECT  50.64 23.676 50.664 23.76 ;
    END
  END i[436]
  PIN i[437]
    DIRECTION INPUT ;
    USE SIGNAL ;
    PORT
      LAYER M5 ;
        RECT  50.736 23.676 50.76 23.76 ;
    END
  END i[437]
  PIN i[438]
    DIRECTION INPUT ;
    USE SIGNAL ;
    PORT
      LAYER M5 ;
        RECT  50.832 23.676 50.856 23.76 ;
    END
  END i[438]
  PIN i[439]
    DIRECTION INPUT ;
    USE SIGNAL ;
    PORT
      LAYER M5 ;
        RECT  50.928 23.676 50.952 23.76 ;
    END
  END i[439]
  PIN i[43]
    DIRECTION INPUT ;
    USE SIGNAL ;
    PORT
      LAYER M5 ;
        RECT  14.448 23.676 14.472 23.76 ;
    END
  END i[43]
  PIN i[440]
    DIRECTION INPUT ;
    USE SIGNAL ;
    PORT
      LAYER M5 ;
        RECT  51.024 23.676 51.048 23.76 ;
    END
  END i[440]
  PIN i[441]
    DIRECTION INPUT ;
    USE SIGNAL ;
    PORT
      LAYER M5 ;
        RECT  51.12 23.676 51.144 23.76 ;
    END
  END i[441]
  PIN i[442]
    DIRECTION INPUT ;
    USE SIGNAL ;
    PORT
      LAYER M5 ;
        RECT  51.216 23.676 51.24 23.76 ;
    END
  END i[442]
  PIN i[443]
    DIRECTION INPUT ;
    USE SIGNAL ;
    PORT
      LAYER M5 ;
        RECT  51.312 23.676 51.336 23.76 ;
    END
  END i[443]
  PIN i[444]
    DIRECTION INPUT ;
    USE SIGNAL ;
    PORT
      LAYER M5 ;
        RECT  51.408 23.676 51.432 23.76 ;
    END
  END i[444]
  PIN i[445]
    DIRECTION INPUT ;
    USE SIGNAL ;
    PORT
      LAYER M5 ;
        RECT  51.504 23.676 51.528 23.76 ;
    END
  END i[445]
  PIN i[446]
    DIRECTION INPUT ;
    USE SIGNAL ;
    PORT
      LAYER M5 ;
        RECT  51.6 23.676 51.624 23.76 ;
    END
  END i[446]
  PIN i[447]
    DIRECTION INPUT ;
    USE SIGNAL ;
    PORT
      LAYER M5 ;
        RECT  51.696 23.676 51.72 23.76 ;
    END
  END i[447]
  PIN i[448]
    DIRECTION INPUT ;
    USE SIGNAL ;
    PORT
      LAYER M5 ;
        RECT  57.936 23.676 57.96 23.76 ;
    END
  END i[448]
  PIN i[449]
    DIRECTION INPUT ;
    USE SIGNAL ;
    PORT
      LAYER M5 ;
        RECT  58.032 23.676 58.056 23.76 ;
    END
  END i[449]
  PIN i[44]
    DIRECTION INPUT ;
    USE SIGNAL ;
    PORT
      LAYER M5 ;
        RECT  14.544 23.676 14.568 23.76 ;
    END
  END i[44]
  PIN i[450]
    DIRECTION INPUT ;
    USE SIGNAL ;
    PORT
      LAYER M5 ;
        RECT  58.128 23.676 58.152 23.76 ;
    END
  END i[450]
  PIN i[451]
    DIRECTION INPUT ;
    USE SIGNAL ;
    PORT
      LAYER M5 ;
        RECT  58.224 23.676 58.248 23.76 ;
    END
  END i[451]
  PIN i[452]
    DIRECTION INPUT ;
    USE SIGNAL ;
    PORT
      LAYER M5 ;
        RECT  58.32 23.676 58.344 23.76 ;
    END
  END i[452]
  PIN i[453]
    DIRECTION INPUT ;
    USE SIGNAL ;
    PORT
      LAYER M5 ;
        RECT  58.416 23.676 58.44 23.76 ;
    END
  END i[453]
  PIN i[454]
    DIRECTION INPUT ;
    USE SIGNAL ;
    PORT
      LAYER M5 ;
        RECT  58.512 23.676 58.536 23.76 ;
    END
  END i[454]
  PIN i[455]
    DIRECTION INPUT ;
    USE SIGNAL ;
    PORT
      LAYER M5 ;
        RECT  58.608 23.676 58.632 23.76 ;
    END
  END i[455]
  PIN i[456]
    DIRECTION INPUT ;
    USE SIGNAL ;
    PORT
      LAYER M5 ;
        RECT  58.704 23.676 58.728 23.76 ;
    END
  END i[456]
  PIN i[457]
    DIRECTION INPUT ;
    USE SIGNAL ;
    PORT
      LAYER M5 ;
        RECT  58.8 23.676 58.824 23.76 ;
    END
  END i[457]
  PIN i[458]
    DIRECTION INPUT ;
    USE SIGNAL ;
    PORT
      LAYER M5 ;
        RECT  58.896 23.676 58.92 23.76 ;
    END
  END i[458]
  PIN i[459]
    DIRECTION INPUT ;
    USE SIGNAL ;
    PORT
      LAYER M5 ;
        RECT  58.992 23.676 59.016 23.76 ;
    END
  END i[459]
  PIN i[45]
    DIRECTION INPUT ;
    USE SIGNAL ;
    PORT
      LAYER M5 ;
        RECT  14.64 23.676 14.664 23.76 ;
    END
  END i[45]
  PIN i[460]
    DIRECTION INPUT ;
    USE SIGNAL ;
    PORT
      LAYER M5 ;
        RECT  59.088 23.676 59.112 23.76 ;
    END
  END i[460]
  PIN i[461]
    DIRECTION INPUT ;
    USE SIGNAL ;
    PORT
      LAYER M5 ;
        RECT  59.184 23.676 59.208 23.76 ;
    END
  END i[461]
  PIN i[462]
    DIRECTION INPUT ;
    USE SIGNAL ;
    PORT
      LAYER M5 ;
        RECT  59.28 23.676 59.304 23.76 ;
    END
  END i[462]
  PIN i[463]
    DIRECTION INPUT ;
    USE SIGNAL ;
    PORT
      LAYER M5 ;
        RECT  59.376 23.676 59.4 23.76 ;
    END
  END i[463]
  PIN i[464]
    DIRECTION INPUT ;
    USE SIGNAL ;
    PORT
      LAYER M5 ;
        RECT  59.472 23.676 59.496 23.76 ;
    END
  END i[464]
  PIN i[465]
    DIRECTION INPUT ;
    USE SIGNAL ;
    PORT
      LAYER M5 ;
        RECT  59.568 23.676 59.592 23.76 ;
    END
  END i[465]
  PIN i[466]
    DIRECTION INPUT ;
    USE SIGNAL ;
    PORT
      LAYER M5 ;
        RECT  59.664 23.676 59.688 23.76 ;
    END
  END i[466]
  PIN i[467]
    DIRECTION INPUT ;
    USE SIGNAL ;
    PORT
      LAYER M5 ;
        RECT  59.76 23.676 59.784 23.76 ;
    END
  END i[467]
  PIN i[468]
    DIRECTION INPUT ;
    USE SIGNAL ;
    PORT
      LAYER M5 ;
        RECT  59.856 23.676 59.88 23.76 ;
    END
  END i[468]
  PIN i[469]
    DIRECTION INPUT ;
    USE SIGNAL ;
    PORT
      LAYER M5 ;
        RECT  59.952 23.676 59.976 23.76 ;
    END
  END i[469]
  PIN i[46]
    DIRECTION INPUT ;
    USE SIGNAL ;
    PORT
      LAYER M5 ;
        RECT  14.736 23.676 14.76 23.76 ;
    END
  END i[46]
  PIN i[470]
    DIRECTION INPUT ;
    USE SIGNAL ;
    PORT
      LAYER M5 ;
        RECT  60.048 23.676 60.072 23.76 ;
    END
  END i[470]
  PIN i[471]
    DIRECTION INPUT ;
    USE SIGNAL ;
    PORT
      LAYER M5 ;
        RECT  60.144 23.676 60.168 23.76 ;
    END
  END i[471]
  PIN i[472]
    DIRECTION INPUT ;
    USE SIGNAL ;
    PORT
      LAYER M5 ;
        RECT  60.24 23.676 60.264 23.76 ;
    END
  END i[472]
  PIN i[473]
    DIRECTION INPUT ;
    USE SIGNAL ;
    PORT
      LAYER M5 ;
        RECT  60.336 23.676 60.36 23.76 ;
    END
  END i[473]
  PIN i[474]
    DIRECTION INPUT ;
    USE SIGNAL ;
    PORT
      LAYER M5 ;
        RECT  60.432 23.676 60.456 23.76 ;
    END
  END i[474]
  PIN i[475]
    DIRECTION INPUT ;
    USE SIGNAL ;
    PORT
      LAYER M5 ;
        RECT  60.528 23.676 60.552 23.76 ;
    END
  END i[475]
  PIN i[476]
    DIRECTION INPUT ;
    USE SIGNAL ;
    PORT
      LAYER M5 ;
        RECT  60.624 23.676 60.648 23.76 ;
    END
  END i[476]
  PIN i[477]
    DIRECTION INPUT ;
    USE SIGNAL ;
    PORT
      LAYER M5 ;
        RECT  60.72 23.676 60.744 23.76 ;
    END
  END i[477]
  PIN i[478]
    DIRECTION INPUT ;
    USE SIGNAL ;
    PORT
      LAYER M5 ;
        RECT  60.816 23.676 60.84 23.76 ;
    END
  END i[478]
  PIN i[479]
    DIRECTION INPUT ;
    USE SIGNAL ;
    PORT
      LAYER M5 ;
        RECT  60.912 23.676 60.936 23.76 ;
    END
  END i[479]
  PIN i[47]
    DIRECTION INPUT ;
    USE SIGNAL ;
    PORT
      LAYER M5 ;
        RECT  14.832 23.676 14.856 23.76 ;
    END
  END i[47]
  PIN i[480]
    DIRECTION INPUT ;
    USE SIGNAL ;
    PORT
      LAYER M5 ;
        RECT  45.648 23.676 45.672 23.76 ;
    END
  END i[480]
  PIN i[481]
    DIRECTION INPUT ;
    USE SIGNAL ;
    PORT
      LAYER M5 ;
        RECT  45.744 23.676 45.768 23.76 ;
    END
  END i[481]
  PIN i[482]
    DIRECTION INPUT ;
    USE SIGNAL ;
    PORT
      LAYER M5 ;
        RECT  45.84 23.676 45.864 23.76 ;
    END
  END i[482]
  PIN i[483]
    DIRECTION INPUT ;
    USE SIGNAL ;
    PORT
      LAYER M5 ;
        RECT  45.936 23.676 45.96 23.76 ;
    END
  END i[483]
  PIN i[484]
    DIRECTION INPUT ;
    USE SIGNAL ;
    PORT
      LAYER M5 ;
        RECT  46.032 23.676 46.056 23.76 ;
    END
  END i[484]
  PIN i[485]
    DIRECTION INPUT ;
    USE SIGNAL ;
    PORT
      LAYER M5 ;
        RECT  46.128 23.676 46.152 23.76 ;
    END
  END i[485]
  PIN i[486]
    DIRECTION INPUT ;
    USE SIGNAL ;
    PORT
      LAYER M5 ;
        RECT  46.224 23.676 46.248 23.76 ;
    END
  END i[486]
  PIN i[487]
    DIRECTION INPUT ;
    USE SIGNAL ;
    PORT
      LAYER M5 ;
        RECT  46.32 23.676 46.344 23.76 ;
    END
  END i[487]
  PIN i[488]
    DIRECTION INPUT ;
    USE SIGNAL ;
    PORT
      LAYER M5 ;
        RECT  46.416 23.676 46.44 23.76 ;
    END
  END i[488]
  PIN i[489]
    DIRECTION INPUT ;
    USE SIGNAL ;
    PORT
      LAYER M5 ;
        RECT  46.512 23.676 46.536 23.76 ;
    END
  END i[489]
  PIN i[48]
    DIRECTION INPUT ;
    USE SIGNAL ;
    PORT
      LAYER M5 ;
        RECT  14.928 23.676 14.952 23.76 ;
    END
  END i[48]
  PIN i[490]
    DIRECTION INPUT ;
    USE SIGNAL ;
    PORT
      LAYER M5 ;
        RECT  46.608 23.676 46.632 23.76 ;
    END
  END i[490]
  PIN i[491]
    DIRECTION INPUT ;
    USE SIGNAL ;
    PORT
      LAYER M5 ;
        RECT  46.704 23.676 46.728 23.76 ;
    END
  END i[491]
  PIN i[492]
    DIRECTION INPUT ;
    USE SIGNAL ;
    PORT
      LAYER M5 ;
        RECT  46.8 23.676 46.824 23.76 ;
    END
  END i[492]
  PIN i[493]
    DIRECTION INPUT ;
    USE SIGNAL ;
    PORT
      LAYER M5 ;
        RECT  46.896 23.676 46.92 23.76 ;
    END
  END i[493]
  PIN i[494]
    DIRECTION INPUT ;
    USE SIGNAL ;
    PORT
      LAYER M5 ;
        RECT  46.992 23.676 47.016 23.76 ;
    END
  END i[494]
  PIN i[495]
    DIRECTION INPUT ;
    USE SIGNAL ;
    PORT
      LAYER M5 ;
        RECT  47.088 23.676 47.112 23.76 ;
    END
  END i[495]
  PIN i[496]
    DIRECTION INPUT ;
    USE SIGNAL ;
    PORT
      LAYER M5 ;
        RECT  47.184 23.676 47.208 23.76 ;
    END
  END i[496]
  PIN i[497]
    DIRECTION INPUT ;
    USE SIGNAL ;
    PORT
      LAYER M5 ;
        RECT  47.28 23.676 47.304 23.76 ;
    END
  END i[497]
  PIN i[498]
    DIRECTION INPUT ;
    USE SIGNAL ;
    PORT
      LAYER M5 ;
        RECT  47.376 23.676 47.4 23.76 ;
    END
  END i[498]
  PIN i[499]
    DIRECTION INPUT ;
    USE SIGNAL ;
    PORT
      LAYER M5 ;
        RECT  47.472 23.676 47.496 23.76 ;
    END
  END i[499]
  PIN i[49]
    DIRECTION INPUT ;
    USE SIGNAL ;
    PORT
      LAYER M5 ;
        RECT  15.024 23.676 15.048 23.76 ;
    END
  END i[49]
  PIN i[4]
    DIRECTION INPUT ;
    USE SIGNAL ;
    PORT
      LAYER M5 ;
        RECT  7.632 23.676 7.656 23.76 ;
    END
  END i[4]
  PIN i[500]
    DIRECTION INPUT ;
    USE SIGNAL ;
    PORT
      LAYER M5 ;
        RECT  47.568 23.676 47.592 23.76 ;
    END
  END i[500]
  PIN i[501]
    DIRECTION INPUT ;
    USE SIGNAL ;
    PORT
      LAYER M5 ;
        RECT  47.664 23.676 47.688 23.76 ;
    END
  END i[501]
  PIN i[502]
    DIRECTION INPUT ;
    USE SIGNAL ;
    PORT
      LAYER M5 ;
        RECT  47.76 23.676 47.784 23.76 ;
    END
  END i[502]
  PIN i[503]
    DIRECTION INPUT ;
    USE SIGNAL ;
    PORT
      LAYER M5 ;
        RECT  47.856 23.676 47.88 23.76 ;
    END
  END i[503]
  PIN i[504]
    DIRECTION INPUT ;
    USE SIGNAL ;
    PORT
      LAYER M5 ;
        RECT  47.952 23.676 47.976 23.76 ;
    END
  END i[504]
  PIN i[505]
    DIRECTION INPUT ;
    USE SIGNAL ;
    PORT
      LAYER M5 ;
        RECT  48.048 23.676 48.072 23.76 ;
    END
  END i[505]
  PIN i[506]
    DIRECTION INPUT ;
    USE SIGNAL ;
    PORT
      LAYER M5 ;
        RECT  48.144 23.676 48.168 23.76 ;
    END
  END i[506]
  PIN i[507]
    DIRECTION INPUT ;
    USE SIGNAL ;
    PORT
      LAYER M5 ;
        RECT  48.24 23.676 48.264 23.76 ;
    END
  END i[507]
  PIN i[508]
    DIRECTION INPUT ;
    USE SIGNAL ;
    PORT
      LAYER M5 ;
        RECT  48.336 23.676 48.36 23.76 ;
    END
  END i[508]
  PIN i[509]
    DIRECTION INPUT ;
    USE SIGNAL ;
    PORT
      LAYER M5 ;
        RECT  48.432 23.676 48.456 23.76 ;
    END
  END i[509]
  PIN i[50]
    DIRECTION INPUT ;
    USE SIGNAL ;
    PORT
      LAYER M5 ;
        RECT  15.12 23.676 15.144 23.76 ;
    END
  END i[50]
  PIN i[510]
    DIRECTION INPUT ;
    USE SIGNAL ;
    PORT
      LAYER M5 ;
        RECT  48.528 23.676 48.552 23.76 ;
    END
  END i[510]
  PIN i[511]
    DIRECTION INPUT ;
    USE SIGNAL ;
    PORT
      LAYER M5 ;
        RECT  48.624 23.676 48.648 23.76 ;
    END
  END i[511]
  PIN i[512]
    DIRECTION INPUT ;
    USE SIGNAL ;
    PORT
      LAYER M5 ;
        RECT  54.864 23.676 54.888 23.76 ;
    END
  END i[512]
  PIN i[513]
    DIRECTION INPUT ;
    USE SIGNAL ;
    PORT
      LAYER M5 ;
        RECT  54.96 23.676 54.984 23.76 ;
    END
  END i[513]
  PIN i[514]
    DIRECTION INPUT ;
    USE SIGNAL ;
    PORT
      LAYER M5 ;
        RECT  55.056 23.676 55.08 23.76 ;
    END
  END i[514]
  PIN i[515]
    DIRECTION INPUT ;
    USE SIGNAL ;
    PORT
      LAYER M5 ;
        RECT  55.152 23.676 55.176 23.76 ;
    END
  END i[515]
  PIN i[516]
    DIRECTION INPUT ;
    USE SIGNAL ;
    PORT
      LAYER M5 ;
        RECT  55.248 23.676 55.272 23.76 ;
    END
  END i[516]
  PIN i[517]
    DIRECTION INPUT ;
    USE SIGNAL ;
    PORT
      LAYER M5 ;
        RECT  55.344 23.676 55.368 23.76 ;
    END
  END i[517]
  PIN i[518]
    DIRECTION INPUT ;
    USE SIGNAL ;
    PORT
      LAYER M5 ;
        RECT  55.44 23.676 55.464 23.76 ;
    END
  END i[518]
  PIN i[519]
    DIRECTION INPUT ;
    USE SIGNAL ;
    PORT
      LAYER M5 ;
        RECT  55.536 23.676 55.56 23.76 ;
    END
  END i[519]
  PIN i[51]
    DIRECTION INPUT ;
    USE SIGNAL ;
    PORT
      LAYER M5 ;
        RECT  15.216 23.676 15.24 23.76 ;
    END
  END i[51]
  PIN i[520]
    DIRECTION INPUT ;
    USE SIGNAL ;
    PORT
      LAYER M5 ;
        RECT  55.632 23.676 55.656 23.76 ;
    END
  END i[520]
  PIN i[521]
    DIRECTION INPUT ;
    USE SIGNAL ;
    PORT
      LAYER M5 ;
        RECT  55.728 23.676 55.752 23.76 ;
    END
  END i[521]
  PIN i[522]
    DIRECTION INPUT ;
    USE SIGNAL ;
    PORT
      LAYER M5 ;
        RECT  55.824 23.676 55.848 23.76 ;
    END
  END i[522]
  PIN i[523]
    DIRECTION INPUT ;
    USE SIGNAL ;
    PORT
      LAYER M5 ;
        RECT  55.92 23.676 55.944 23.76 ;
    END
  END i[523]
  PIN i[524]
    DIRECTION INPUT ;
    USE SIGNAL ;
    PORT
      LAYER M5 ;
        RECT  56.016 23.676 56.04 23.76 ;
    END
  END i[524]
  PIN i[525]
    DIRECTION INPUT ;
    USE SIGNAL ;
    PORT
      LAYER M5 ;
        RECT  56.112 23.676 56.136 23.76 ;
    END
  END i[525]
  PIN i[526]
    DIRECTION INPUT ;
    USE SIGNAL ;
    PORT
      LAYER M5 ;
        RECT  56.208 23.676 56.232 23.76 ;
    END
  END i[526]
  PIN i[527]
    DIRECTION INPUT ;
    USE SIGNAL ;
    PORT
      LAYER M5 ;
        RECT  56.304 23.676 56.328 23.76 ;
    END
  END i[527]
  PIN i[528]
    DIRECTION INPUT ;
    USE SIGNAL ;
    PORT
      LAYER M5 ;
        RECT  56.4 23.676 56.424 23.76 ;
    END
  END i[528]
  PIN i[529]
    DIRECTION INPUT ;
    USE SIGNAL ;
    PORT
      LAYER M5 ;
        RECT  56.496 23.676 56.52 23.76 ;
    END
  END i[529]
  PIN i[52]
    DIRECTION INPUT ;
    USE SIGNAL ;
    PORT
      LAYER M5 ;
        RECT  15.312 23.676 15.336 23.76 ;
    END
  END i[52]
  PIN i[530]
    DIRECTION INPUT ;
    USE SIGNAL ;
    PORT
      LAYER M5 ;
        RECT  56.592 23.676 56.616 23.76 ;
    END
  END i[530]
  PIN i[531]
    DIRECTION INPUT ;
    USE SIGNAL ;
    PORT
      LAYER M5 ;
        RECT  56.688 23.676 56.712 23.76 ;
    END
  END i[531]
  PIN i[532]
    DIRECTION INPUT ;
    USE SIGNAL ;
    PORT
      LAYER M5 ;
        RECT  56.784 23.676 56.808 23.76 ;
    END
  END i[532]
  PIN i[533]
    DIRECTION INPUT ;
    USE SIGNAL ;
    PORT
      LAYER M5 ;
        RECT  56.88 23.676 56.904 23.76 ;
    END
  END i[533]
  PIN i[534]
    DIRECTION INPUT ;
    USE SIGNAL ;
    PORT
      LAYER M5 ;
        RECT  56.976 23.676 57 23.76 ;
    END
  END i[534]
  PIN i[535]
    DIRECTION INPUT ;
    USE SIGNAL ;
    PORT
      LAYER M5 ;
        RECT  57.072 23.676 57.096 23.76 ;
    END
  END i[535]
  PIN i[536]
    DIRECTION INPUT ;
    USE SIGNAL ;
    PORT
      LAYER M5 ;
        RECT  57.168 23.676 57.192 23.76 ;
    END
  END i[536]
  PIN i[537]
    DIRECTION INPUT ;
    USE SIGNAL ;
    PORT
      LAYER M5 ;
        RECT  57.264 23.676 57.288 23.76 ;
    END
  END i[537]
  PIN i[538]
    DIRECTION INPUT ;
    USE SIGNAL ;
    PORT
      LAYER M5 ;
        RECT  57.36 23.676 57.384 23.76 ;
    END
  END i[538]
  PIN i[539]
    DIRECTION INPUT ;
    USE SIGNAL ;
    PORT
      LAYER M5 ;
        RECT  57.456 23.676 57.48 23.76 ;
    END
  END i[539]
  PIN i[53]
    DIRECTION INPUT ;
    USE SIGNAL ;
    PORT
      LAYER M5 ;
        RECT  15.408 23.676 15.432 23.76 ;
    END
  END i[53]
  PIN i[540]
    DIRECTION INPUT ;
    USE SIGNAL ;
    PORT
      LAYER M5 ;
        RECT  57.552 23.676 57.576 23.76 ;
    END
  END i[540]
  PIN i[541]
    DIRECTION INPUT ;
    USE SIGNAL ;
    PORT
      LAYER M5 ;
        RECT  57.648 23.676 57.672 23.76 ;
    END
  END i[541]
  PIN i[542]
    DIRECTION INPUT ;
    USE SIGNAL ;
    PORT
      LAYER M5 ;
        RECT  57.744 23.676 57.768 23.76 ;
    END
  END i[542]
  PIN i[543]
    DIRECTION INPUT ;
    USE SIGNAL ;
    PORT
      LAYER M5 ;
        RECT  57.84 23.676 57.864 23.76 ;
    END
  END i[543]
  PIN i[544]
    DIRECTION INPUT ;
    USE SIGNAL ;
    PORT
      LAYER M5 ;
        RECT  61.008 23.676 61.032 23.76 ;
    END
  END i[544]
  PIN i[545]
    DIRECTION INPUT ;
    USE SIGNAL ;
    PORT
      LAYER M5 ;
        RECT  61.104 23.676 61.128 23.76 ;
    END
  END i[545]
  PIN i[546]
    DIRECTION INPUT ;
    USE SIGNAL ;
    PORT
      LAYER M5 ;
        RECT  61.2 23.676 61.224 23.76 ;
    END
  END i[546]
  PIN i[547]
    DIRECTION INPUT ;
    USE SIGNAL ;
    PORT
      LAYER M5 ;
        RECT  61.296 23.676 61.32 23.76 ;
    END
  END i[547]
  PIN i[548]
    DIRECTION INPUT ;
    USE SIGNAL ;
    PORT
      LAYER M5 ;
        RECT  61.392 23.676 61.416 23.76 ;
    END
  END i[548]
  PIN i[549]
    DIRECTION INPUT ;
    USE SIGNAL ;
    PORT
      LAYER M5 ;
        RECT  61.488 23.676 61.512 23.76 ;
    END
  END i[549]
  PIN i[54]
    DIRECTION INPUT ;
    USE SIGNAL ;
    PORT
      LAYER M5 ;
        RECT  15.504 23.676 15.528 23.76 ;
    END
  END i[54]
  PIN i[550]
    DIRECTION INPUT ;
    USE SIGNAL ;
    PORT
      LAYER M5 ;
        RECT  61.584 23.676 61.608 23.76 ;
    END
  END i[550]
  PIN i[551]
    DIRECTION INPUT ;
    USE SIGNAL ;
    PORT
      LAYER M5 ;
        RECT  61.68 23.676 61.704 23.76 ;
    END
  END i[551]
  PIN i[552]
    DIRECTION INPUT ;
    USE SIGNAL ;
    PORT
      LAYER M5 ;
        RECT  61.776 23.676 61.8 23.76 ;
    END
  END i[552]
  PIN i[553]
    DIRECTION INPUT ;
    USE SIGNAL ;
    PORT
      LAYER M5 ;
        RECT  61.872 23.676 61.896 23.76 ;
    END
  END i[553]
  PIN i[554]
    DIRECTION INPUT ;
    USE SIGNAL ;
    PORT
      LAYER M5 ;
        RECT  61.968 23.676 61.992 23.76 ;
    END
  END i[554]
  PIN i[555]
    DIRECTION INPUT ;
    USE SIGNAL ;
    PORT
      LAYER M5 ;
        RECT  62.064 23.676 62.088 23.76 ;
    END
  END i[555]
  PIN i[556]
    DIRECTION INPUT ;
    USE SIGNAL ;
    PORT
      LAYER M5 ;
        RECT  62.16 23.676 62.184 23.76 ;
    END
  END i[556]
  PIN i[557]
    DIRECTION INPUT ;
    USE SIGNAL ;
    PORT
      LAYER M5 ;
        RECT  62.256 23.676 62.28 23.76 ;
    END
  END i[557]
  PIN i[558]
    DIRECTION INPUT ;
    USE SIGNAL ;
    PORT
      LAYER M5 ;
        RECT  62.352 23.676 62.376 23.76 ;
    END
  END i[558]
  PIN i[559]
    DIRECTION INPUT ;
    USE SIGNAL ;
    PORT
      LAYER M5 ;
        RECT  62.448 23.676 62.472 23.76 ;
    END
  END i[559]
  PIN i[55]
    DIRECTION INPUT ;
    USE SIGNAL ;
    PORT
      LAYER M5 ;
        RECT  15.6 23.676 15.624 23.76 ;
    END
  END i[55]
  PIN i[560]
    DIRECTION INPUT ;
    USE SIGNAL ;
    PORT
      LAYER M5 ;
        RECT  62.544 23.676 62.568 23.76 ;
    END
  END i[560]
  PIN i[561]
    DIRECTION INPUT ;
    USE SIGNAL ;
    PORT
      LAYER M5 ;
        RECT  62.64 23.676 62.664 23.76 ;
    END
  END i[561]
  PIN i[562]
    DIRECTION INPUT ;
    USE SIGNAL ;
    PORT
      LAYER M5 ;
        RECT  62.736 23.676 62.76 23.76 ;
    END
  END i[562]
  PIN i[563]
    DIRECTION INPUT ;
    USE SIGNAL ;
    PORT
      LAYER M5 ;
        RECT  62.832 23.676 62.856 23.76 ;
    END
  END i[563]
  PIN i[564]
    DIRECTION INPUT ;
    USE SIGNAL ;
    PORT
      LAYER M5 ;
        RECT  62.928 23.676 62.952 23.76 ;
    END
  END i[564]
  PIN i[565]
    DIRECTION INPUT ;
    USE SIGNAL ;
    PORT
      LAYER M5 ;
        RECT  63.024 23.676 63.048 23.76 ;
    END
  END i[565]
  PIN i[566]
    DIRECTION INPUT ;
    USE SIGNAL ;
    PORT
      LAYER M5 ;
        RECT  63.12 23.676 63.144 23.76 ;
    END
  END i[566]
  PIN i[567]
    DIRECTION INPUT ;
    USE SIGNAL ;
    PORT
      LAYER M5 ;
        RECT  63.216 23.676 63.24 23.76 ;
    END
  END i[567]
  PIN i[568]
    DIRECTION INPUT ;
    USE SIGNAL ;
    PORT
      LAYER M5 ;
        RECT  63.312 23.676 63.336 23.76 ;
    END
  END i[568]
  PIN i[569]
    DIRECTION INPUT ;
    USE SIGNAL ;
    PORT
      LAYER M5 ;
        RECT  63.408 23.676 63.432 23.76 ;
    END
  END i[569]
  PIN i[56]
    DIRECTION INPUT ;
    USE SIGNAL ;
    PORT
      LAYER M5 ;
        RECT  15.696 23.676 15.72 23.76 ;
    END
  END i[56]
  PIN i[570]
    DIRECTION INPUT ;
    USE SIGNAL ;
    PORT
      LAYER M5 ;
        RECT  63.504 23.676 63.528 23.76 ;
    END
  END i[570]
  PIN i[571]
    DIRECTION INPUT ;
    USE SIGNAL ;
    PORT
      LAYER M5 ;
        RECT  63.6 23.676 63.624 23.76 ;
    END
  END i[571]
  PIN i[572]
    DIRECTION INPUT ;
    USE SIGNAL ;
    PORT
      LAYER M5 ;
        RECT  63.696 23.676 63.72 23.76 ;
    END
  END i[572]
  PIN i[573]
    DIRECTION INPUT ;
    USE SIGNAL ;
    PORT
      LAYER M5 ;
        RECT  63.792 23.676 63.816 23.76 ;
    END
  END i[573]
  PIN i[574]
    DIRECTION INPUT ;
    USE SIGNAL ;
    PORT
      LAYER M5 ;
        RECT  63.888 23.676 63.912 23.76 ;
    END
  END i[574]
  PIN i[575]
    DIRECTION INPUT ;
    USE SIGNAL ;
    PORT
      LAYER M5 ;
        RECT  63.984 23.676 64.008 23.76 ;
    END
  END i[575]
  PIN i[576]
    DIRECTION INPUT ;
    USE SIGNAL ;
    PORT
      LAYER M5 ;
        RECT  3.408 23.676 3.432 23.76 ;
    END
  END i[576]
  PIN i[577]
    DIRECTION INPUT ;
    USE SIGNAL ;
    PORT
      LAYER M5 ;
        RECT  3.504 23.676 3.528 23.76 ;
    END
  END i[577]
  PIN i[578]
    DIRECTION INPUT ;
    USE SIGNAL ;
    PORT
      LAYER M5 ;
        RECT  3.6 23.676 3.624 23.76 ;
    END
  END i[578]
  PIN i[579]
    DIRECTION INPUT ;
    USE SIGNAL ;
    PORT
      LAYER M5 ;
        RECT  3.696 23.676 3.72 23.76 ;
    END
  END i[579]
  PIN i[57]
    DIRECTION INPUT ;
    USE SIGNAL ;
    PORT
      LAYER M5 ;
        RECT  15.792 23.676 15.816 23.76 ;
    END
  END i[57]
  PIN i[580]
    DIRECTION INPUT ;
    USE SIGNAL ;
    PORT
      LAYER M5 ;
        RECT  3.792 23.676 3.816 23.76 ;
    END
  END i[580]
  PIN i[581]
    DIRECTION INPUT ;
    USE SIGNAL ;
    PORT
      LAYER M5 ;
        RECT  3.888 23.676 3.912 23.76 ;
    END
  END i[581]
  PIN i[582]
    DIRECTION INPUT ;
    USE SIGNAL ;
    PORT
      LAYER M5 ;
        RECT  3.984 23.676 4.008 23.76 ;
    END
  END i[582]
  PIN i[583]
    DIRECTION INPUT ;
    USE SIGNAL ;
    PORT
      LAYER M5 ;
        RECT  4.08 23.676 4.104 23.76 ;
    END
  END i[583]
  PIN i[584]
    DIRECTION INPUT ;
    USE SIGNAL ;
    PORT
      LAYER M5 ;
        RECT  4.176 23.676 4.2 23.76 ;
    END
  END i[584]
  PIN i[585]
    DIRECTION INPUT ;
    USE SIGNAL ;
    PORT
      LAYER M5 ;
        RECT  4.272 23.676 4.296 23.76 ;
    END
  END i[585]
  PIN i[586]
    DIRECTION INPUT ;
    USE SIGNAL ;
    PORT
      LAYER M5 ;
        RECT  4.368 23.676 4.392 23.76 ;
    END
  END i[586]
  PIN i[587]
    DIRECTION INPUT ;
    USE SIGNAL ;
    PORT
      LAYER M5 ;
        RECT  4.464 23.676 4.488 23.76 ;
    END
  END i[587]
  PIN i[588]
    DIRECTION INPUT ;
    USE SIGNAL ;
    PORT
      LAYER M5 ;
        RECT  4.56 23.676 4.584 23.76 ;
    END
  END i[588]
  PIN i[589]
    DIRECTION INPUT ;
    USE SIGNAL ;
    PORT
      LAYER M5 ;
        RECT  4.656 23.676 4.68 23.76 ;
    END
  END i[589]
  PIN i[58]
    DIRECTION INPUT ;
    USE SIGNAL ;
    PORT
      LAYER M5 ;
        RECT  15.888 23.676 15.912 23.76 ;
    END
  END i[58]
  PIN i[590]
    DIRECTION INPUT ;
    USE SIGNAL ;
    PORT
      LAYER M5 ;
        RECT  4.752 23.676 4.776 23.76 ;
    END
  END i[590]
  PIN i[591]
    DIRECTION INPUT ;
    USE SIGNAL ;
    PORT
      LAYER M5 ;
        RECT  4.848 23.676 4.872 23.76 ;
    END
  END i[591]
  PIN i[592]
    DIRECTION INPUT ;
    USE SIGNAL ;
    PORT
      LAYER M5 ;
        RECT  4.944 23.676 4.968 23.76 ;
    END
  END i[592]
  PIN i[593]
    DIRECTION INPUT ;
    USE SIGNAL ;
    PORT
      LAYER M5 ;
        RECT  5.04 23.676 5.064 23.76 ;
    END
  END i[593]
  PIN i[594]
    DIRECTION INPUT ;
    USE SIGNAL ;
    PORT
      LAYER M5 ;
        RECT  5.136 23.676 5.16 23.76 ;
    END
  END i[594]
  PIN i[595]
    DIRECTION INPUT ;
    USE SIGNAL ;
    PORT
      LAYER M5 ;
        RECT  5.232 23.676 5.256 23.76 ;
    END
  END i[595]
  PIN i[596]
    DIRECTION INPUT ;
    USE SIGNAL ;
    PORT
      LAYER M5 ;
        RECT  5.328 23.676 5.352 23.76 ;
    END
  END i[596]
  PIN i[597]
    DIRECTION INPUT ;
    USE SIGNAL ;
    PORT
      LAYER M5 ;
        RECT  5.424 23.676 5.448 23.76 ;
    END
  END i[597]
  PIN i[598]
    DIRECTION INPUT ;
    USE SIGNAL ;
    PORT
      LAYER M5 ;
        RECT  5.52 23.676 5.544 23.76 ;
    END
  END i[598]
  PIN i[599]
    DIRECTION INPUT ;
    USE SIGNAL ;
    PORT
      LAYER M5 ;
        RECT  5.616 23.676 5.64 23.76 ;
    END
  END i[599]
  PIN i[59]
    DIRECTION INPUT ;
    USE SIGNAL ;
    PORT
      LAYER M5 ;
        RECT  15.984 23.676 16.008 23.76 ;
    END
  END i[59]
  PIN i[5]
    DIRECTION INPUT ;
    USE SIGNAL ;
    PORT
      LAYER M5 ;
        RECT  7.728 23.676 7.752 23.76 ;
    END
  END i[5]
  PIN i[600]
    DIRECTION INPUT ;
    USE SIGNAL ;
    PORT
      LAYER M5 ;
        RECT  5.712 23.676 5.736 23.76 ;
    END
  END i[600]
  PIN i[601]
    DIRECTION INPUT ;
    USE SIGNAL ;
    PORT
      LAYER M5 ;
        RECT  5.808 23.676 5.832 23.76 ;
    END
  END i[601]
  PIN i[602]
    DIRECTION INPUT ;
    USE SIGNAL ;
    PORT
      LAYER M5 ;
        RECT  5.904 23.676 5.928 23.76 ;
    END
  END i[602]
  PIN i[603]
    DIRECTION INPUT ;
    USE SIGNAL ;
    PORT
      LAYER M5 ;
        RECT  6 23.676 6.024 23.76 ;
    END
  END i[603]
  PIN i[604]
    DIRECTION INPUT ;
    USE SIGNAL ;
    PORT
      LAYER M5 ;
        RECT  6.096 23.676 6.12 23.76 ;
    END
  END i[604]
  PIN i[605]
    DIRECTION INPUT ;
    USE SIGNAL ;
    PORT
      LAYER M5 ;
        RECT  6.192 23.676 6.216 23.76 ;
    END
  END i[605]
  PIN i[606]
    DIRECTION INPUT ;
    USE SIGNAL ;
    PORT
      LAYER M5 ;
        RECT  6.288 23.676 6.312 23.76 ;
    END
  END i[606]
  PIN i[607]
    DIRECTION INPUT ;
    USE SIGNAL ;
    PORT
      LAYER M5 ;
        RECT  6.384 23.676 6.408 23.76 ;
    END
  END i[607]
  PIN i[608]
    DIRECTION INPUT ;
    USE SIGNAL ;
    PORT
      LAYER M5 ;
        RECT  1.872 23.676 1.896 23.76 ;
    END
  END i[608]
  PIN i[609]
    DIRECTION INPUT ;
    USE SIGNAL ;
    PORT
      LAYER M5 ;
        RECT  1.968 23.676 1.992 23.76 ;
    END
  END i[609]
  PIN i[60]
    DIRECTION INPUT ;
    USE SIGNAL ;
    PORT
      LAYER M5 ;
        RECT  16.08 23.676 16.104 23.76 ;
    END
  END i[60]
  PIN i[610]
    DIRECTION INPUT ;
    USE SIGNAL ;
    PORT
      LAYER M5 ;
        RECT  2.064 23.676 2.088 23.76 ;
    END
  END i[610]
  PIN i[611]
    DIRECTION INPUT ;
    USE SIGNAL ;
    PORT
      LAYER M5 ;
        RECT  2.16 23.676 2.184 23.76 ;
    END
  END i[611]
  PIN i[612]
    DIRECTION INPUT ;
    USE SIGNAL ;
    PORT
      LAYER M5 ;
        RECT  2.256 23.676 2.28 23.76 ;
    END
  END i[612]
  PIN i[613]
    DIRECTION INPUT ;
    USE SIGNAL ;
    PORT
      LAYER M5 ;
        RECT  2.352 23.676 2.376 23.76 ;
    END
  END i[613]
  PIN i[614]
    DIRECTION INPUT ;
    USE SIGNAL ;
    PORT
      LAYER M5 ;
        RECT  2.448 23.676 2.472 23.76 ;
    END
  END i[614]
  PIN i[615]
    DIRECTION INPUT ;
    USE SIGNAL ;
    PORT
      LAYER M5 ;
        RECT  2.544 23.676 2.568 23.76 ;
    END
  END i[615]
  PIN i[616]
    DIRECTION INPUT ;
    USE SIGNAL ;
    PORT
      LAYER M5 ;
        RECT  2.64 23.676 2.664 23.76 ;
    END
  END i[616]
  PIN i[617]
    DIRECTION INPUT ;
    USE SIGNAL ;
    PORT
      LAYER M5 ;
        RECT  2.736 23.676 2.76 23.76 ;
    END
  END i[617]
  PIN i[618]
    DIRECTION INPUT ;
    USE SIGNAL ;
    PORT
      LAYER M5 ;
        RECT  2.832 23.676 2.856 23.76 ;
    END
  END i[618]
  PIN i[619]
    DIRECTION INPUT ;
    USE SIGNAL ;
    PORT
      LAYER M5 ;
        RECT  2.928 23.676 2.952 23.76 ;
    END
  END i[619]
  PIN i[61]
    DIRECTION INPUT ;
    USE SIGNAL ;
    PORT
      LAYER M5 ;
        RECT  16.176 23.676 16.2 23.76 ;
    END
  END i[61]
  PIN i[620]
    DIRECTION INPUT ;
    USE SIGNAL ;
    PORT
      LAYER M5 ;
        RECT  3.024 23.676 3.048 23.76 ;
    END
  END i[620]
  PIN i[621]
    DIRECTION INPUT ;
    USE SIGNAL ;
    PORT
      LAYER M5 ;
        RECT  3.12 23.676 3.144 23.76 ;
    END
  END i[621]
  PIN i[622]
    DIRECTION INPUT ;
    USE SIGNAL ;
    PORT
      LAYER M5 ;
        RECT  3.216 23.676 3.24 23.76 ;
    END
  END i[622]
  PIN i[623]
    DIRECTION INPUT ;
    USE SIGNAL ;
    PORT
      LAYER M5 ;
        RECT  3.312 23.676 3.336 23.76 ;
    END
  END i[623]
  PIN i[62]
    DIRECTION INPUT ;
    USE SIGNAL ;
    PORT
      LAYER M5 ;
        RECT  16.272 23.676 16.296 23.76 ;
    END
  END i[62]
  PIN i[63]
    DIRECTION INPUT ;
    USE SIGNAL ;
    PORT
      LAYER M5 ;
        RECT  16.368 23.676 16.392 23.76 ;
    END
  END i[63]
  PIN i[64]
    DIRECTION INPUT ;
    USE SIGNAL ;
    PORT
      LAYER M5 ;
        RECT  16.464 23.676 16.488 23.76 ;
    END
  END i[64]
  PIN i[65]
    DIRECTION INPUT ;
    USE SIGNAL ;
    PORT
      LAYER M5 ;
        RECT  16.56 23.676 16.584 23.76 ;
    END
  END i[65]
  PIN i[66]
    DIRECTION INPUT ;
    USE SIGNAL ;
    PORT
      LAYER M5 ;
        RECT  16.656 23.676 16.68 23.76 ;
    END
  END i[66]
  PIN i[67]
    DIRECTION INPUT ;
    USE SIGNAL ;
    PORT
      LAYER M5 ;
        RECT  16.752 23.676 16.776 23.76 ;
    END
  END i[67]
  PIN i[68]
    DIRECTION INPUT ;
    USE SIGNAL ;
    PORT
      LAYER M5 ;
        RECT  16.848 23.676 16.872 23.76 ;
    END
  END i[68]
  PIN i[69]
    DIRECTION INPUT ;
    USE SIGNAL ;
    PORT
      LAYER M5 ;
        RECT  16.944 23.676 16.968 23.76 ;
    END
  END i[69]
  PIN i[6]
    DIRECTION INPUT ;
    USE SIGNAL ;
    PORT
      LAYER M5 ;
        RECT  7.824 23.676 7.848 23.76 ;
    END
  END i[6]
  PIN i[70]
    DIRECTION INPUT ;
    USE SIGNAL ;
    PORT
      LAYER M5 ;
        RECT  17.04 23.676 17.064 23.76 ;
    END
  END i[70]
  PIN i[71]
    DIRECTION INPUT ;
    USE SIGNAL ;
    PORT
      LAYER M5 ;
        RECT  17.136 23.676 17.16 23.76 ;
    END
  END i[71]
  PIN i[72]
    DIRECTION INPUT ;
    USE SIGNAL ;
    PORT
      LAYER M5 ;
        RECT  17.232 23.676 17.256 23.76 ;
    END
  END i[72]
  PIN i[73]
    DIRECTION INPUT ;
    USE SIGNAL ;
    PORT
      LAYER M5 ;
        RECT  17.328 23.676 17.352 23.76 ;
    END
  END i[73]
  PIN i[74]
    DIRECTION INPUT ;
    USE SIGNAL ;
    PORT
      LAYER M5 ;
        RECT  17.424 23.676 17.448 23.76 ;
    END
  END i[74]
  PIN i[75]
    DIRECTION INPUT ;
    USE SIGNAL ;
    PORT
      LAYER M5 ;
        RECT  17.52 23.676 17.544 23.76 ;
    END
  END i[75]
  PIN i[76]
    DIRECTION INPUT ;
    USE SIGNAL ;
    PORT
      LAYER M5 ;
        RECT  17.616 23.676 17.64 23.76 ;
    END
  END i[76]
  PIN i[77]
    DIRECTION INPUT ;
    USE SIGNAL ;
    PORT
      LAYER M5 ;
        RECT  17.712 23.676 17.736 23.76 ;
    END
  END i[77]
  PIN i[78]
    DIRECTION INPUT ;
    USE SIGNAL ;
    PORT
      LAYER M5 ;
        RECT  17.808 23.676 17.832 23.76 ;
    END
  END i[78]
  PIN i[79]
    DIRECTION INPUT ;
    USE SIGNAL ;
    PORT
      LAYER M5 ;
        RECT  17.904 23.676 17.928 23.76 ;
    END
  END i[79]
  PIN i[7]
    DIRECTION INPUT ;
    USE SIGNAL ;
    PORT
      LAYER M5 ;
        RECT  7.92 23.676 7.944 23.76 ;
    END
  END i[7]
  PIN i[80]
    DIRECTION INPUT ;
    USE SIGNAL ;
    PORT
      LAYER M5 ;
        RECT  18 23.676 18.024 23.76 ;
    END
  END i[80]
  PIN i[81]
    DIRECTION INPUT ;
    USE SIGNAL ;
    PORT
      LAYER M5 ;
        RECT  18.096 23.676 18.12 23.76 ;
    END
  END i[81]
  PIN i[82]
    DIRECTION INPUT ;
    USE SIGNAL ;
    PORT
      LAYER M5 ;
        RECT  18.192 23.676 18.216 23.76 ;
    END
  END i[82]
  PIN i[83]
    DIRECTION INPUT ;
    USE SIGNAL ;
    PORT
      LAYER M5 ;
        RECT  18.288 23.676 18.312 23.76 ;
    END
  END i[83]
  PIN i[84]
    DIRECTION INPUT ;
    USE SIGNAL ;
    PORT
      LAYER M5 ;
        RECT  18.384 23.676 18.408 23.76 ;
    END
  END i[84]
  PIN i[85]
    DIRECTION INPUT ;
    USE SIGNAL ;
    PORT
      LAYER M5 ;
        RECT  18.48 23.676 18.504 23.76 ;
    END
  END i[85]
  PIN i[86]
    DIRECTION INPUT ;
    USE SIGNAL ;
    PORT
      LAYER M5 ;
        RECT  18.576 23.676 18.6 23.76 ;
    END
  END i[86]
  PIN i[87]
    DIRECTION INPUT ;
    USE SIGNAL ;
    PORT
      LAYER M5 ;
        RECT  18.672 23.676 18.696 23.76 ;
    END
  END i[87]
  PIN i[88]
    DIRECTION INPUT ;
    USE SIGNAL ;
    PORT
      LAYER M5 ;
        RECT  18.768 23.676 18.792 23.76 ;
    END
  END i[88]
  PIN i[89]
    DIRECTION INPUT ;
    USE SIGNAL ;
    PORT
      LAYER M5 ;
        RECT  18.864 23.676 18.888 23.76 ;
    END
  END i[89]
  PIN i[8]
    DIRECTION INPUT ;
    USE SIGNAL ;
    PORT
      LAYER M5 ;
        RECT  8.016 23.676 8.04 23.76 ;
    END
  END i[8]
  PIN i[90]
    DIRECTION INPUT ;
    USE SIGNAL ;
    PORT
      LAYER M5 ;
        RECT  18.96 23.676 18.984 23.76 ;
    END
  END i[90]
  PIN i[91]
    DIRECTION INPUT ;
    USE SIGNAL ;
    PORT
      LAYER M5 ;
        RECT  19.056 23.676 19.08 23.76 ;
    END
  END i[91]
  PIN i[92]
    DIRECTION INPUT ;
    USE SIGNAL ;
    PORT
      LAYER M5 ;
        RECT  19.152 23.676 19.176 23.76 ;
    END
  END i[92]
  PIN i[93]
    DIRECTION INPUT ;
    USE SIGNAL ;
    PORT
      LAYER M5 ;
        RECT  19.248 23.676 19.272 23.76 ;
    END
  END i[93]
  PIN i[94]
    DIRECTION INPUT ;
    USE SIGNAL ;
    PORT
      LAYER M5 ;
        RECT  19.344 23.676 19.368 23.76 ;
    END
  END i[94]
  PIN i[95]
    DIRECTION INPUT ;
    USE SIGNAL ;
    PORT
      LAYER M5 ;
        RECT  19.44 23.676 19.464 23.76 ;
    END
  END i[95]
  PIN i[96]
    DIRECTION INPUT ;
    USE SIGNAL ;
    PORT
      LAYER M5 ;
        RECT  10.32 23.676 10.344 23.76 ;
    END
  END i[96]
  PIN i[97]
    DIRECTION INPUT ;
    USE SIGNAL ;
    PORT
      LAYER M5 ;
        RECT  10.416 23.676 10.44 23.76 ;
    END
  END i[97]
  PIN i[98]
    DIRECTION INPUT ;
    USE SIGNAL ;
    PORT
      LAYER M5 ;
        RECT  10.512 23.676 10.536 23.76 ;
    END
  END i[98]
  PIN i[99]
    DIRECTION INPUT ;
    USE SIGNAL ;
    PORT
      LAYER M5 ;
        RECT  10.608 23.676 10.632 23.76 ;
    END
  END i[99]
  PIN i[9]
    DIRECTION INPUT ;
    USE SIGNAL ;
    PORT
      LAYER M5 ;
        RECT  8.112 23.676 8.136 23.76 ;
    END
  END i[9]
  PIN o[0]
    DIRECTION OUTPUT ;
    USE SIGNAL ;
    PORT
      LAYER M5 ;
        RECT  19.92 0 19.944 0.084 ;
    END
  END o[0]
  PIN o[100]
    DIRECTION OUTPUT ;
    USE SIGNAL ;
    PORT
      LAYER M5 ;
        RECT  35.664 0 35.688 0.084 ;
    END
  END o[100]
  PIN o[101]
    DIRECTION OUTPUT ;
    USE SIGNAL ;
    PORT
      LAYER M5 ;
        RECT  35.76 0 35.784 0.084 ;
    END
  END o[101]
  PIN o[102]
    DIRECTION OUTPUT ;
    USE SIGNAL ;
    PORT
      LAYER M5 ;
        RECT  35.856 0 35.88 0.084 ;
    END
  END o[102]
  PIN o[103]
    DIRECTION OUTPUT ;
    USE SIGNAL ;
    PORT
      LAYER M5 ;
        RECT  35.952 0 35.976 0.084 ;
    END
  END o[103]
  PIN o[104]
    DIRECTION OUTPUT ;
    USE SIGNAL ;
    PORT
      LAYER M5 ;
        RECT  36.048 0 36.072 0.084 ;
    END
  END o[104]
  PIN o[105]
    DIRECTION OUTPUT ;
    USE SIGNAL ;
    PORT
      LAYER M5 ;
        RECT  36.144 0 36.168 0.084 ;
    END
  END o[105]
  PIN o[106]
    DIRECTION OUTPUT ;
    USE SIGNAL ;
    PORT
      LAYER M5 ;
        RECT  36.24 0 36.264 0.084 ;
    END
  END o[106]
  PIN o[107]
    DIRECTION OUTPUT ;
    USE SIGNAL ;
    PORT
      LAYER M5 ;
        RECT  36.336 0 36.36 0.084 ;
    END
  END o[107]
  PIN o[108]
    DIRECTION OUTPUT ;
    USE SIGNAL ;
    PORT
      LAYER M5 ;
        RECT  36.432 0 36.456 0.084 ;
    END
  END o[108]
  PIN o[109]
    DIRECTION OUTPUT ;
    USE SIGNAL ;
    PORT
      LAYER M5 ;
        RECT  36.528 0 36.552 0.084 ;
    END
  END o[109]
  PIN o[10]
    DIRECTION OUTPUT ;
    USE SIGNAL ;
    PORT
      LAYER M5 ;
        RECT  20.88 0 20.904 0.084 ;
    END
  END o[10]
  PIN o[110]
    DIRECTION OUTPUT ;
    USE SIGNAL ;
    PORT
      LAYER M5 ;
        RECT  36.624 0 36.648 0.084 ;
    END
  END o[110]
  PIN o[111]
    DIRECTION OUTPUT ;
    USE SIGNAL ;
    PORT
      LAYER M5 ;
        RECT  36.72 0 36.744 0.084 ;
    END
  END o[111]
  PIN o[112]
    DIRECTION OUTPUT ;
    USE SIGNAL ;
    PORT
      LAYER M5 ;
        RECT  36.816 0 36.84 0.084 ;
    END
  END o[112]
  PIN o[113]
    DIRECTION OUTPUT ;
    USE SIGNAL ;
    PORT
      LAYER M5 ;
        RECT  36.912 0 36.936 0.084 ;
    END
  END o[113]
  PIN o[114]
    DIRECTION OUTPUT ;
    USE SIGNAL ;
    PORT
      LAYER M5 ;
        RECT  37.008 0 37.032 0.084 ;
    END
  END o[114]
  PIN o[115]
    DIRECTION OUTPUT ;
    USE SIGNAL ;
    PORT
      LAYER M5 ;
        RECT  37.104 0 37.128 0.084 ;
    END
  END o[115]
  PIN o[116]
    DIRECTION OUTPUT ;
    USE SIGNAL ;
    PORT
      LAYER M5 ;
        RECT  37.2 0 37.224 0.084 ;
    END
  END o[116]
  PIN o[117]
    DIRECTION OUTPUT ;
    USE SIGNAL ;
    PORT
      LAYER M5 ;
        RECT  37.296 0 37.32 0.084 ;
    END
  END o[117]
  PIN o[118]
    DIRECTION OUTPUT ;
    USE SIGNAL ;
    PORT
      LAYER M5 ;
        RECT  37.392 0 37.416 0.084 ;
    END
  END o[118]
  PIN o[119]
    DIRECTION OUTPUT ;
    USE SIGNAL ;
    PORT
      LAYER M5 ;
        RECT  37.488 0 37.512 0.084 ;
    END
  END o[119]
  PIN o[11]
    DIRECTION OUTPUT ;
    USE SIGNAL ;
    PORT
      LAYER M5 ;
        RECT  20.976 0 21 0.084 ;
    END
  END o[11]
  PIN o[120]
    DIRECTION OUTPUT ;
    USE SIGNAL ;
    PORT
      LAYER M5 ;
        RECT  37.584 0 37.608 0.084 ;
    END
  END o[120]
  PIN o[121]
    DIRECTION OUTPUT ;
    USE SIGNAL ;
    PORT
      LAYER M5 ;
        RECT  37.68 0 37.704 0.084 ;
    END
  END o[121]
  PIN o[122]
    DIRECTION OUTPUT ;
    USE SIGNAL ;
    PORT
      LAYER M5 ;
        RECT  37.776 0 37.8 0.084 ;
    END
  END o[122]
  PIN o[123]
    DIRECTION OUTPUT ;
    USE SIGNAL ;
    PORT
      LAYER M5 ;
        RECT  37.872 0 37.896 0.084 ;
    END
  END o[123]
  PIN o[124]
    DIRECTION OUTPUT ;
    USE SIGNAL ;
    PORT
      LAYER M5 ;
        RECT  37.968 0 37.992 0.084 ;
    END
  END o[124]
  PIN o[125]
    DIRECTION OUTPUT ;
    USE SIGNAL ;
    PORT
      LAYER M5 ;
        RECT  38.064 0 38.088 0.084 ;
    END
  END o[125]
  PIN o[126]
    DIRECTION OUTPUT ;
    USE SIGNAL ;
    PORT
      LAYER M5 ;
        RECT  38.16 0 38.184 0.084 ;
    END
  END o[126]
  PIN o[127]
    DIRECTION OUTPUT ;
    USE SIGNAL ;
    PORT
      LAYER M5 ;
        RECT  38.256 0 38.28 0.084 ;
    END
  END o[127]
  PIN o[128]
    DIRECTION OUTPUT ;
    USE SIGNAL ;
    PORT
      LAYER M5 ;
        RECT  29.136 0 29.16 0.084 ;
    END
  END o[128]
  PIN o[129]
    DIRECTION OUTPUT ;
    USE SIGNAL ;
    PORT
      LAYER M5 ;
        RECT  29.232 0 29.256 0.084 ;
    END
  END o[129]
  PIN o[12]
    DIRECTION OUTPUT ;
    USE SIGNAL ;
    PORT
      LAYER M5 ;
        RECT  21.072 0 21.096 0.084 ;
    END
  END o[12]
  PIN o[130]
    DIRECTION OUTPUT ;
    USE SIGNAL ;
    PORT
      LAYER M5 ;
        RECT  29.328 0 29.352 0.084 ;
    END
  END o[130]
  PIN o[131]
    DIRECTION OUTPUT ;
    USE SIGNAL ;
    PORT
      LAYER M5 ;
        RECT  29.424 0 29.448 0.084 ;
    END
  END o[131]
  PIN o[132]
    DIRECTION OUTPUT ;
    USE SIGNAL ;
    PORT
      LAYER M5 ;
        RECT  29.52 0 29.544 0.084 ;
    END
  END o[132]
  PIN o[133]
    DIRECTION OUTPUT ;
    USE SIGNAL ;
    PORT
      LAYER M5 ;
        RECT  29.616 0 29.64 0.084 ;
    END
  END o[133]
  PIN o[134]
    DIRECTION OUTPUT ;
    USE SIGNAL ;
    PORT
      LAYER M5 ;
        RECT  29.712 0 29.736 0.084 ;
    END
  END o[134]
  PIN o[135]
    DIRECTION OUTPUT ;
    USE SIGNAL ;
    PORT
      LAYER M5 ;
        RECT  29.808 0 29.832 0.084 ;
    END
  END o[135]
  PIN o[136]
    DIRECTION OUTPUT ;
    USE SIGNAL ;
    PORT
      LAYER M5 ;
        RECT  29.904 0 29.928 0.084 ;
    END
  END o[136]
  PIN o[137]
    DIRECTION OUTPUT ;
    USE SIGNAL ;
    PORT
      LAYER M5 ;
        RECT  30 0 30.024 0.084 ;
    END
  END o[137]
  PIN o[138]
    DIRECTION OUTPUT ;
    USE SIGNAL ;
    PORT
      LAYER M5 ;
        RECT  30.096 0 30.12 0.084 ;
    END
  END o[138]
  PIN o[139]
    DIRECTION OUTPUT ;
    USE SIGNAL ;
    PORT
      LAYER M5 ;
        RECT  30.192 0 30.216 0.084 ;
    END
  END o[139]
  PIN o[13]
    DIRECTION OUTPUT ;
    USE SIGNAL ;
    PORT
      LAYER M5 ;
        RECT  21.168 0 21.192 0.084 ;
    END
  END o[13]
  PIN o[140]
    DIRECTION OUTPUT ;
    USE SIGNAL ;
    PORT
      LAYER M5 ;
        RECT  30.288 0 30.312 0.084 ;
    END
  END o[140]
  PIN o[141]
    DIRECTION OUTPUT ;
    USE SIGNAL ;
    PORT
      LAYER M5 ;
        RECT  30.384 0 30.408 0.084 ;
    END
  END o[141]
  PIN o[142]
    DIRECTION OUTPUT ;
    USE SIGNAL ;
    PORT
      LAYER M5 ;
        RECT  30.48 0 30.504 0.084 ;
    END
  END o[142]
  PIN o[143]
    DIRECTION OUTPUT ;
    USE SIGNAL ;
    PORT
      LAYER M5 ;
        RECT  30.576 0 30.6 0.084 ;
    END
  END o[143]
  PIN o[144]
    DIRECTION OUTPUT ;
    USE SIGNAL ;
    PORT
      LAYER M5 ;
        RECT  30.672 0 30.696 0.084 ;
    END
  END o[144]
  PIN o[145]
    DIRECTION OUTPUT ;
    USE SIGNAL ;
    PORT
      LAYER M5 ;
        RECT  30.768 0 30.792 0.084 ;
    END
  END o[145]
  PIN o[146]
    DIRECTION OUTPUT ;
    USE SIGNAL ;
    PORT
      LAYER M5 ;
        RECT  30.864 0 30.888 0.084 ;
    END
  END o[146]
  PIN o[147]
    DIRECTION OUTPUT ;
    USE SIGNAL ;
    PORT
      LAYER M5 ;
        RECT  30.96 0 30.984 0.084 ;
    END
  END o[147]
  PIN o[148]
    DIRECTION OUTPUT ;
    USE SIGNAL ;
    PORT
      LAYER M5 ;
        RECT  31.056 0 31.08 0.084 ;
    END
  END o[148]
  PIN o[149]
    DIRECTION OUTPUT ;
    USE SIGNAL ;
    PORT
      LAYER M5 ;
        RECT  31.152 0 31.176 0.084 ;
    END
  END o[149]
  PIN o[14]
    DIRECTION OUTPUT ;
    USE SIGNAL ;
    PORT
      LAYER M5 ;
        RECT  21.264 0 21.288 0.084 ;
    END
  END o[14]
  PIN o[150]
    DIRECTION OUTPUT ;
    USE SIGNAL ;
    PORT
      LAYER M5 ;
        RECT  31.248 0 31.272 0.084 ;
    END
  END o[150]
  PIN o[151]
    DIRECTION OUTPUT ;
    USE SIGNAL ;
    PORT
      LAYER M5 ;
        RECT  31.344 0 31.368 0.084 ;
    END
  END o[151]
  PIN o[152]
    DIRECTION OUTPUT ;
    USE SIGNAL ;
    PORT
      LAYER M5 ;
        RECT  31.44 0 31.464 0.084 ;
    END
  END o[152]
  PIN o[153]
    DIRECTION OUTPUT ;
    USE SIGNAL ;
    PORT
      LAYER M5 ;
        RECT  31.536 0 31.56 0.084 ;
    END
  END o[153]
  PIN o[154]
    DIRECTION OUTPUT ;
    USE SIGNAL ;
    PORT
      LAYER M5 ;
        RECT  31.632 0 31.656 0.084 ;
    END
  END o[154]
  PIN o[155]
    DIRECTION OUTPUT ;
    USE SIGNAL ;
    PORT
      LAYER M5 ;
        RECT  31.728 0 31.752 0.084 ;
    END
  END o[155]
  PIN o[156]
    DIRECTION OUTPUT ;
    USE SIGNAL ;
    PORT
      LAYER M5 ;
        RECT  31.824 0 31.848 0.084 ;
    END
  END o[156]
  PIN o[157]
    DIRECTION OUTPUT ;
    USE SIGNAL ;
    PORT
      LAYER M5 ;
        RECT  31.92 0 31.944 0.084 ;
    END
  END o[157]
  PIN o[158]
    DIRECTION OUTPUT ;
    USE SIGNAL ;
    PORT
      LAYER M5 ;
        RECT  32.016 0 32.04 0.084 ;
    END
  END o[158]
  PIN o[159]
    DIRECTION OUTPUT ;
    USE SIGNAL ;
    PORT
      LAYER M5 ;
        RECT  32.112 0 32.136 0.084 ;
    END
  END o[159]
  PIN o[15]
    DIRECTION OUTPUT ;
    USE SIGNAL ;
    PORT
      LAYER M5 ;
        RECT  21.36 0 21.384 0.084 ;
    END
  END o[15]
  PIN o[160]
    DIRECTION OUTPUT ;
    USE SIGNAL ;
    PORT
      LAYER M5 ;
        RECT  32.208 0 32.232 0.084 ;
    END
  END o[160]
  PIN o[161]
    DIRECTION OUTPUT ;
    USE SIGNAL ;
    PORT
      LAYER M5 ;
        RECT  32.304 0 32.328 0.084 ;
    END
  END o[161]
  PIN o[162]
    DIRECTION OUTPUT ;
    USE SIGNAL ;
    PORT
      LAYER M5 ;
        RECT  32.4 0 32.424 0.084 ;
    END
  END o[162]
  PIN o[163]
    DIRECTION OUTPUT ;
    USE SIGNAL ;
    PORT
      LAYER M5 ;
        RECT  32.496 0 32.52 0.084 ;
    END
  END o[163]
  PIN o[164]
    DIRECTION OUTPUT ;
    USE SIGNAL ;
    PORT
      LAYER M5 ;
        RECT  32.592 0 32.616 0.084 ;
    END
  END o[164]
  PIN o[165]
    DIRECTION OUTPUT ;
    USE SIGNAL ;
    PORT
      LAYER M5 ;
        RECT  32.688 0 32.712 0.084 ;
    END
  END o[165]
  PIN o[166]
    DIRECTION OUTPUT ;
    USE SIGNAL ;
    PORT
      LAYER M5 ;
        RECT  32.784 0 32.808 0.084 ;
    END
  END o[166]
  PIN o[167]
    DIRECTION OUTPUT ;
    USE SIGNAL ;
    PORT
      LAYER M5 ;
        RECT  32.88 0 32.904 0.084 ;
    END
  END o[167]
  PIN o[168]
    DIRECTION OUTPUT ;
    USE SIGNAL ;
    PORT
      LAYER M5 ;
        RECT  32.976 0 33 0.084 ;
    END
  END o[168]
  PIN o[169]
    DIRECTION OUTPUT ;
    USE SIGNAL ;
    PORT
      LAYER M5 ;
        RECT  33.072 0 33.096 0.084 ;
    END
  END o[169]
  PIN o[16]
    DIRECTION OUTPUT ;
    USE SIGNAL ;
    PORT
      LAYER M5 ;
        RECT  21.456 0 21.48 0.084 ;
    END
  END o[16]
  PIN o[170]
    DIRECTION OUTPUT ;
    USE SIGNAL ;
    PORT
      LAYER M5 ;
        RECT  33.168 0 33.192 0.084 ;
    END
  END o[170]
  PIN o[171]
    DIRECTION OUTPUT ;
    USE SIGNAL ;
    PORT
      LAYER M5 ;
        RECT  33.264 0 33.288 0.084 ;
    END
  END o[171]
  PIN o[172]
    DIRECTION OUTPUT ;
    USE SIGNAL ;
    PORT
      LAYER M5 ;
        RECT  33.36 0 33.384 0.084 ;
    END
  END o[172]
  PIN o[173]
    DIRECTION OUTPUT ;
    USE SIGNAL ;
    PORT
      LAYER M5 ;
        RECT  33.456 0 33.48 0.084 ;
    END
  END o[173]
  PIN o[174]
    DIRECTION OUTPUT ;
    USE SIGNAL ;
    PORT
      LAYER M5 ;
        RECT  33.552 0 33.576 0.084 ;
    END
  END o[174]
  PIN o[175]
    DIRECTION OUTPUT ;
    USE SIGNAL ;
    PORT
      LAYER M5 ;
        RECT  33.648 0 33.672 0.084 ;
    END
  END o[175]
  PIN o[176]
    DIRECTION OUTPUT ;
    USE SIGNAL ;
    PORT
      LAYER M5 ;
        RECT  33.744 0 33.768 0.084 ;
    END
  END o[176]
  PIN o[177]
    DIRECTION OUTPUT ;
    USE SIGNAL ;
    PORT
      LAYER M5 ;
        RECT  33.84 0 33.864 0.084 ;
    END
  END o[177]
  PIN o[178]
    DIRECTION OUTPUT ;
    USE SIGNAL ;
    PORT
      LAYER M5 ;
        RECT  33.936 0 33.96 0.084 ;
    END
  END o[178]
  PIN o[179]
    DIRECTION OUTPUT ;
    USE SIGNAL ;
    PORT
      LAYER M5 ;
        RECT  34.032 0 34.056 0.084 ;
    END
  END o[179]
  PIN o[17]
    DIRECTION OUTPUT ;
    USE SIGNAL ;
    PORT
      LAYER M5 ;
        RECT  21.552 0 21.576 0.084 ;
    END
  END o[17]
  PIN o[180]
    DIRECTION OUTPUT ;
    USE SIGNAL ;
    PORT
      LAYER M5 ;
        RECT  34.128 0 34.152 0.084 ;
    END
  END o[180]
  PIN o[181]
    DIRECTION OUTPUT ;
    USE SIGNAL ;
    PORT
      LAYER M5 ;
        RECT  34.224 0 34.248 0.084 ;
    END
  END o[181]
  PIN o[182]
    DIRECTION OUTPUT ;
    USE SIGNAL ;
    PORT
      LAYER M5 ;
        RECT  34.32 0 34.344 0.084 ;
    END
  END o[182]
  PIN o[183]
    DIRECTION OUTPUT ;
    USE SIGNAL ;
    PORT
      LAYER M5 ;
        RECT  34.416 0 34.44 0.084 ;
    END
  END o[183]
  PIN o[184]
    DIRECTION OUTPUT ;
    USE SIGNAL ;
    PORT
      LAYER M5 ;
        RECT  34.512 0 34.536 0.084 ;
    END
  END o[184]
  PIN o[185]
    DIRECTION OUTPUT ;
    USE SIGNAL ;
    PORT
      LAYER M5 ;
        RECT  34.608 0 34.632 0.084 ;
    END
  END o[185]
  PIN o[186]
    DIRECTION OUTPUT ;
    USE SIGNAL ;
    PORT
      LAYER M5 ;
        RECT  34.704 0 34.728 0.084 ;
    END
  END o[186]
  PIN o[187]
    DIRECTION OUTPUT ;
    USE SIGNAL ;
    PORT
      LAYER M5 ;
        RECT  34.8 0 34.824 0.084 ;
    END
  END o[187]
  PIN o[188]
    DIRECTION OUTPUT ;
    USE SIGNAL ;
    PORT
      LAYER M5 ;
        RECT  34.896 0 34.92 0.084 ;
    END
  END o[188]
  PIN o[189]
    DIRECTION OUTPUT ;
    USE SIGNAL ;
    PORT
      LAYER M5 ;
        RECT  34.992 0 35.016 0.084 ;
    END
  END o[189]
  PIN o[18]
    DIRECTION OUTPUT ;
    USE SIGNAL ;
    PORT
      LAYER M5 ;
        RECT  21.648 0 21.672 0.084 ;
    END
  END o[18]
  PIN o[190]
    DIRECTION OUTPUT ;
    USE SIGNAL ;
    PORT
      LAYER M5 ;
        RECT  35.088 0 35.112 0.084 ;
    END
  END o[190]
  PIN o[191]
    DIRECTION OUTPUT ;
    USE SIGNAL ;
    PORT
      LAYER M5 ;
        RECT  35.184 0 35.208 0.084 ;
    END
  END o[191]
  PIN o[192]
    DIRECTION OUTPUT ;
    USE SIGNAL ;
    PORT
      LAYER M5 ;
        RECT  6.864 0 6.888 0.084 ;
    END
  END o[192]
  PIN o[193]
    DIRECTION OUTPUT ;
    USE SIGNAL ;
    PORT
      LAYER M5 ;
        RECT  6.96 0 6.984 0.084 ;
    END
  END o[193]
  PIN o[194]
    DIRECTION OUTPUT ;
    USE SIGNAL ;
    PORT
      LAYER M5 ;
        RECT  7.056 0 7.08 0.084 ;
    END
  END o[194]
  PIN o[195]
    DIRECTION OUTPUT ;
    USE SIGNAL ;
    PORT
      LAYER M5 ;
        RECT  7.152 0 7.176 0.084 ;
    END
  END o[195]
  PIN o[196]
    DIRECTION OUTPUT ;
    USE SIGNAL ;
    PORT
      LAYER M5 ;
        RECT  7.248 0 7.272 0.084 ;
    END
  END o[196]
  PIN o[197]
    DIRECTION OUTPUT ;
    USE SIGNAL ;
    PORT
      LAYER M5 ;
        RECT  7.344 0 7.368 0.084 ;
    END
  END o[197]
  PIN o[198]
    DIRECTION OUTPUT ;
    USE SIGNAL ;
    PORT
      LAYER M5 ;
        RECT  7.44 0 7.464 0.084 ;
    END
  END o[198]
  PIN o[199]
    DIRECTION OUTPUT ;
    USE SIGNAL ;
    PORT
      LAYER M5 ;
        RECT  7.536 0 7.56 0.084 ;
    END
  END o[199]
  PIN o[19]
    DIRECTION OUTPUT ;
    USE SIGNAL ;
    PORT
      LAYER M5 ;
        RECT  21.744 0 21.768 0.084 ;
    END
  END o[19]
  PIN o[1]
    DIRECTION OUTPUT ;
    USE SIGNAL ;
    PORT
      LAYER M5 ;
        RECT  20.016 0 20.04 0.084 ;
    END
  END o[1]
  PIN o[200]
    DIRECTION OUTPUT ;
    USE SIGNAL ;
    PORT
      LAYER M5 ;
        RECT  7.632 0 7.656 0.084 ;
    END
  END o[200]
  PIN o[201]
    DIRECTION OUTPUT ;
    USE SIGNAL ;
    PORT
      LAYER M5 ;
        RECT  7.728 0 7.752 0.084 ;
    END
  END o[201]
  PIN o[202]
    DIRECTION OUTPUT ;
    USE SIGNAL ;
    PORT
      LAYER M5 ;
        RECT  7.824 0 7.848 0.084 ;
    END
  END o[202]
  PIN o[203]
    DIRECTION OUTPUT ;
    USE SIGNAL ;
    PORT
      LAYER M5 ;
        RECT  7.92 0 7.944 0.084 ;
    END
  END o[203]
  PIN o[204]
    DIRECTION OUTPUT ;
    USE SIGNAL ;
    PORT
      LAYER M5 ;
        RECT  8.016 0 8.04 0.084 ;
    END
  END o[204]
  PIN o[205]
    DIRECTION OUTPUT ;
    USE SIGNAL ;
    PORT
      LAYER M5 ;
        RECT  8.112 0 8.136 0.084 ;
    END
  END o[205]
  PIN o[206]
    DIRECTION OUTPUT ;
    USE SIGNAL ;
    PORT
      LAYER M5 ;
        RECT  8.208 0 8.232 0.084 ;
    END
  END o[206]
  PIN o[207]
    DIRECTION OUTPUT ;
    USE SIGNAL ;
    PORT
      LAYER M5 ;
        RECT  8.304 0 8.328 0.084 ;
    END
  END o[207]
  PIN o[208]
    DIRECTION OUTPUT ;
    USE SIGNAL ;
    PORT
      LAYER M5 ;
        RECT  8.4 0 8.424 0.084 ;
    END
  END o[208]
  PIN o[209]
    DIRECTION OUTPUT ;
    USE SIGNAL ;
    PORT
      LAYER M5 ;
        RECT  8.496 0 8.52 0.084 ;
    END
  END o[209]
  PIN o[20]
    DIRECTION OUTPUT ;
    USE SIGNAL ;
    PORT
      LAYER M5 ;
        RECT  21.84 0 21.864 0.084 ;
    END
  END o[20]
  PIN o[210]
    DIRECTION OUTPUT ;
    USE SIGNAL ;
    PORT
      LAYER M5 ;
        RECT  8.592 0 8.616 0.084 ;
    END
  END o[210]
  PIN o[211]
    DIRECTION OUTPUT ;
    USE SIGNAL ;
    PORT
      LAYER M5 ;
        RECT  8.688 0 8.712 0.084 ;
    END
  END o[211]
  PIN o[212]
    DIRECTION OUTPUT ;
    USE SIGNAL ;
    PORT
      LAYER M5 ;
        RECT  8.784 0 8.808 0.084 ;
    END
  END o[212]
  PIN o[213]
    DIRECTION OUTPUT ;
    USE SIGNAL ;
    PORT
      LAYER M5 ;
        RECT  8.88 0 8.904 0.084 ;
    END
  END o[213]
  PIN o[214]
    DIRECTION OUTPUT ;
    USE SIGNAL ;
    PORT
      LAYER M5 ;
        RECT  8.976 0 9 0.084 ;
    END
  END o[214]
  PIN o[215]
    DIRECTION OUTPUT ;
    USE SIGNAL ;
    PORT
      LAYER M5 ;
        RECT  9.072 0 9.096 0.084 ;
    END
  END o[215]
  PIN o[216]
    DIRECTION OUTPUT ;
    USE SIGNAL ;
    PORT
      LAYER M5 ;
        RECT  9.168 0 9.192 0.084 ;
    END
  END o[216]
  PIN o[217]
    DIRECTION OUTPUT ;
    USE SIGNAL ;
    PORT
      LAYER M5 ;
        RECT  9.264 0 9.288 0.084 ;
    END
  END o[217]
  PIN o[218]
    DIRECTION OUTPUT ;
    USE SIGNAL ;
    PORT
      LAYER M5 ;
        RECT  9.36 0 9.384 0.084 ;
    END
  END o[218]
  PIN o[219]
    DIRECTION OUTPUT ;
    USE SIGNAL ;
    PORT
      LAYER M5 ;
        RECT  9.456 0 9.48 0.084 ;
    END
  END o[219]
  PIN o[21]
    DIRECTION OUTPUT ;
    USE SIGNAL ;
    PORT
      LAYER M5 ;
        RECT  21.936 0 21.96 0.084 ;
    END
  END o[21]
  PIN o[220]
    DIRECTION OUTPUT ;
    USE SIGNAL ;
    PORT
      LAYER M5 ;
        RECT  9.552 0 9.576 0.084 ;
    END
  END o[220]
  PIN o[221]
    DIRECTION OUTPUT ;
    USE SIGNAL ;
    PORT
      LAYER M5 ;
        RECT  9.648 0 9.672 0.084 ;
    END
  END o[221]
  PIN o[222]
    DIRECTION OUTPUT ;
    USE SIGNAL ;
    PORT
      LAYER M5 ;
        RECT  9.744 0 9.768 0.084 ;
    END
  END o[222]
  PIN o[223]
    DIRECTION OUTPUT ;
    USE SIGNAL ;
    PORT
      LAYER M5 ;
        RECT  9.84 0 9.864 0.084 ;
    END
  END o[223]
  PIN o[224]
    DIRECTION OUTPUT ;
    USE SIGNAL ;
    PORT
      LAYER M5 ;
        RECT  13.008 0 13.032 0.084 ;
    END
  END o[224]
  PIN o[225]
    DIRECTION OUTPUT ;
    USE SIGNAL ;
    PORT
      LAYER M5 ;
        RECT  13.104 0 13.128 0.084 ;
    END
  END o[225]
  PIN o[226]
    DIRECTION OUTPUT ;
    USE SIGNAL ;
    PORT
      LAYER M5 ;
        RECT  13.2 0 13.224 0.084 ;
    END
  END o[226]
  PIN o[227]
    DIRECTION OUTPUT ;
    USE SIGNAL ;
    PORT
      LAYER M5 ;
        RECT  13.296 0 13.32 0.084 ;
    END
  END o[227]
  PIN o[228]
    DIRECTION OUTPUT ;
    USE SIGNAL ;
    PORT
      LAYER M5 ;
        RECT  13.392 0 13.416 0.084 ;
    END
  END o[228]
  PIN o[229]
    DIRECTION OUTPUT ;
    USE SIGNAL ;
    PORT
      LAYER M5 ;
        RECT  13.488 0 13.512 0.084 ;
    END
  END o[229]
  PIN o[22]
    DIRECTION OUTPUT ;
    USE SIGNAL ;
    PORT
      LAYER M5 ;
        RECT  22.032 0 22.056 0.084 ;
    END
  END o[22]
  PIN o[230]
    DIRECTION OUTPUT ;
    USE SIGNAL ;
    PORT
      LAYER M5 ;
        RECT  13.584 0 13.608 0.084 ;
    END
  END o[230]
  PIN o[231]
    DIRECTION OUTPUT ;
    USE SIGNAL ;
    PORT
      LAYER M5 ;
        RECT  13.68 0 13.704 0.084 ;
    END
  END o[231]
  PIN o[232]
    DIRECTION OUTPUT ;
    USE SIGNAL ;
    PORT
      LAYER M5 ;
        RECT  13.776 0 13.8 0.084 ;
    END
  END o[232]
  PIN o[233]
    DIRECTION OUTPUT ;
    USE SIGNAL ;
    PORT
      LAYER M5 ;
        RECT  13.872 0 13.896 0.084 ;
    END
  END o[233]
  PIN o[234]
    DIRECTION OUTPUT ;
    USE SIGNAL ;
    PORT
      LAYER M5 ;
        RECT  13.968 0 13.992 0.084 ;
    END
  END o[234]
  PIN o[235]
    DIRECTION OUTPUT ;
    USE SIGNAL ;
    PORT
      LAYER M5 ;
        RECT  14.064 0 14.088 0.084 ;
    END
  END o[235]
  PIN o[236]
    DIRECTION OUTPUT ;
    USE SIGNAL ;
    PORT
      LAYER M5 ;
        RECT  14.16 0 14.184 0.084 ;
    END
  END o[236]
  PIN o[237]
    DIRECTION OUTPUT ;
    USE SIGNAL ;
    PORT
      LAYER M5 ;
        RECT  14.256 0 14.28 0.084 ;
    END
  END o[237]
  PIN o[238]
    DIRECTION OUTPUT ;
    USE SIGNAL ;
    PORT
      LAYER M5 ;
        RECT  14.352 0 14.376 0.084 ;
    END
  END o[238]
  PIN o[239]
    DIRECTION OUTPUT ;
    USE SIGNAL ;
    PORT
      LAYER M5 ;
        RECT  14.448 0 14.472 0.084 ;
    END
  END o[239]
  PIN o[23]
    DIRECTION OUTPUT ;
    USE SIGNAL ;
    PORT
      LAYER M5 ;
        RECT  22.128 0 22.152 0.084 ;
    END
  END o[23]
  PIN o[240]
    DIRECTION OUTPUT ;
    USE SIGNAL ;
    PORT
      LAYER M5 ;
        RECT  14.544 0 14.568 0.084 ;
    END
  END o[240]
  PIN o[241]
    DIRECTION OUTPUT ;
    USE SIGNAL ;
    PORT
      LAYER M5 ;
        RECT  14.64 0 14.664 0.084 ;
    END
  END o[241]
  PIN o[242]
    DIRECTION OUTPUT ;
    USE SIGNAL ;
    PORT
      LAYER M5 ;
        RECT  14.736 0 14.76 0.084 ;
    END
  END o[242]
  PIN o[243]
    DIRECTION OUTPUT ;
    USE SIGNAL ;
    PORT
      LAYER M5 ;
        RECT  14.832 0 14.856 0.084 ;
    END
  END o[243]
  PIN o[244]
    DIRECTION OUTPUT ;
    USE SIGNAL ;
    PORT
      LAYER M5 ;
        RECT  14.928 0 14.952 0.084 ;
    END
  END o[244]
  PIN o[245]
    DIRECTION OUTPUT ;
    USE SIGNAL ;
    PORT
      LAYER M5 ;
        RECT  15.024 0 15.048 0.084 ;
    END
  END o[245]
  PIN o[246]
    DIRECTION OUTPUT ;
    USE SIGNAL ;
    PORT
      LAYER M5 ;
        RECT  15.12 0 15.144 0.084 ;
    END
  END o[246]
  PIN o[247]
    DIRECTION OUTPUT ;
    USE SIGNAL ;
    PORT
      LAYER M5 ;
        RECT  15.216 0 15.24 0.084 ;
    END
  END o[247]
  PIN o[248]
    DIRECTION OUTPUT ;
    USE SIGNAL ;
    PORT
      LAYER M5 ;
        RECT  15.312 0 15.336 0.084 ;
    END
  END o[248]
  PIN o[249]
    DIRECTION OUTPUT ;
    USE SIGNAL ;
    PORT
      LAYER M5 ;
        RECT  15.408 0 15.432 0.084 ;
    END
  END o[249]
  PIN o[24]
    DIRECTION OUTPUT ;
    USE SIGNAL ;
    PORT
      LAYER M5 ;
        RECT  22.224 0 22.248 0.084 ;
    END
  END o[24]
  PIN o[250]
    DIRECTION OUTPUT ;
    USE SIGNAL ;
    PORT
      LAYER M5 ;
        RECT  15.504 0 15.528 0.084 ;
    END
  END o[250]
  PIN o[251]
    DIRECTION OUTPUT ;
    USE SIGNAL ;
    PORT
      LAYER M5 ;
        RECT  15.6 0 15.624 0.084 ;
    END
  END o[251]
  PIN o[252]
    DIRECTION OUTPUT ;
    USE SIGNAL ;
    PORT
      LAYER M5 ;
        RECT  15.696 0 15.72 0.084 ;
    END
  END o[252]
  PIN o[253]
    DIRECTION OUTPUT ;
    USE SIGNAL ;
    PORT
      LAYER M5 ;
        RECT  15.792 0 15.816 0.084 ;
    END
  END o[253]
  PIN o[254]
    DIRECTION OUTPUT ;
    USE SIGNAL ;
    PORT
      LAYER M5 ;
        RECT  15.888 0 15.912 0.084 ;
    END
  END o[254]
  PIN o[255]
    DIRECTION OUTPUT ;
    USE SIGNAL ;
    PORT
      LAYER M5 ;
        RECT  15.984 0 16.008 0.084 ;
    END
  END o[255]
  PIN o[256]
    DIRECTION OUTPUT ;
    USE SIGNAL ;
    PORT
      LAYER M5 ;
        RECT  48.336 0 48.36 0.084 ;
    END
  END o[256]
  PIN o[257]
    DIRECTION OUTPUT ;
    USE SIGNAL ;
    PORT
      LAYER M5 ;
        RECT  48.432 0 48.456 0.084 ;
    END
  END o[257]
  PIN o[258]
    DIRECTION OUTPUT ;
    USE SIGNAL ;
    PORT
      LAYER M5 ;
        RECT  48.528 0 48.552 0.084 ;
    END
  END o[258]
  PIN o[259]
    DIRECTION OUTPUT ;
    USE SIGNAL ;
    PORT
      LAYER M5 ;
        RECT  48.624 0 48.648 0.084 ;
    END
  END o[259]
  PIN o[25]
    DIRECTION OUTPUT ;
    USE SIGNAL ;
    PORT
      LAYER M5 ;
        RECT  22.32 0 22.344 0.084 ;
    END
  END o[25]
  PIN o[260]
    DIRECTION OUTPUT ;
    USE SIGNAL ;
    PORT
      LAYER M5 ;
        RECT  48.72 0 48.744 0.084 ;
    END
  END o[260]
  PIN o[261]
    DIRECTION OUTPUT ;
    USE SIGNAL ;
    PORT
      LAYER M5 ;
        RECT  48.816 0 48.84 0.084 ;
    END
  END o[261]
  PIN o[262]
    DIRECTION OUTPUT ;
    USE SIGNAL ;
    PORT
      LAYER M5 ;
        RECT  48.912 0 48.936 0.084 ;
    END
  END o[262]
  PIN o[263]
    DIRECTION OUTPUT ;
    USE SIGNAL ;
    PORT
      LAYER M5 ;
        RECT  49.008 0 49.032 0.084 ;
    END
  END o[263]
  PIN o[264]
    DIRECTION OUTPUT ;
    USE SIGNAL ;
    PORT
      LAYER M5 ;
        RECT  49.104 0 49.128 0.084 ;
    END
  END o[264]
  PIN o[265]
    DIRECTION OUTPUT ;
    USE SIGNAL ;
    PORT
      LAYER M5 ;
        RECT  49.2 0 49.224 0.084 ;
    END
  END o[265]
  PIN o[266]
    DIRECTION OUTPUT ;
    USE SIGNAL ;
    PORT
      LAYER M5 ;
        RECT  49.296 0 49.32 0.084 ;
    END
  END o[266]
  PIN o[267]
    DIRECTION OUTPUT ;
    USE SIGNAL ;
    PORT
      LAYER M5 ;
        RECT  49.392 0 49.416 0.084 ;
    END
  END o[267]
  PIN o[268]
    DIRECTION OUTPUT ;
    USE SIGNAL ;
    PORT
      LAYER M5 ;
        RECT  49.488 0 49.512 0.084 ;
    END
  END o[268]
  PIN o[269]
    DIRECTION OUTPUT ;
    USE SIGNAL ;
    PORT
      LAYER M5 ;
        RECT  49.584 0 49.608 0.084 ;
    END
  END o[269]
  PIN o[26]
    DIRECTION OUTPUT ;
    USE SIGNAL ;
    PORT
      LAYER M5 ;
        RECT  22.416 0 22.44 0.084 ;
    END
  END o[26]
  PIN o[270]
    DIRECTION OUTPUT ;
    USE SIGNAL ;
    PORT
      LAYER M5 ;
        RECT  49.68 0 49.704 0.084 ;
    END
  END o[270]
  PIN o[271]
    DIRECTION OUTPUT ;
    USE SIGNAL ;
    PORT
      LAYER M5 ;
        RECT  49.776 0 49.8 0.084 ;
    END
  END o[271]
  PIN o[272]
    DIRECTION OUTPUT ;
    USE SIGNAL ;
    PORT
      LAYER M5 ;
        RECT  49.872 0 49.896 0.084 ;
    END
  END o[272]
  PIN o[273]
    DIRECTION OUTPUT ;
    USE SIGNAL ;
    PORT
      LAYER M5 ;
        RECT  49.968 0 49.992 0.084 ;
    END
  END o[273]
  PIN o[274]
    DIRECTION OUTPUT ;
    USE SIGNAL ;
    PORT
      LAYER M5 ;
        RECT  50.064 0 50.088 0.084 ;
    END
  END o[274]
  PIN o[275]
    DIRECTION OUTPUT ;
    USE SIGNAL ;
    PORT
      LAYER M5 ;
        RECT  50.16 0 50.184 0.084 ;
    END
  END o[275]
  PIN o[276]
    DIRECTION OUTPUT ;
    USE SIGNAL ;
    PORT
      LAYER M5 ;
        RECT  50.256 0 50.28 0.084 ;
    END
  END o[276]
  PIN o[277]
    DIRECTION OUTPUT ;
    USE SIGNAL ;
    PORT
      LAYER M5 ;
        RECT  50.352 0 50.376 0.084 ;
    END
  END o[277]
  PIN o[278]
    DIRECTION OUTPUT ;
    USE SIGNAL ;
    PORT
      LAYER M5 ;
        RECT  50.448 0 50.472 0.084 ;
    END
  END o[278]
  PIN o[279]
    DIRECTION OUTPUT ;
    USE SIGNAL ;
    PORT
      LAYER M5 ;
        RECT  50.544 0 50.568 0.084 ;
    END
  END o[279]
  PIN o[27]
    DIRECTION OUTPUT ;
    USE SIGNAL ;
    PORT
      LAYER M5 ;
        RECT  22.512 0 22.536 0.084 ;
    END
  END o[27]
  PIN o[280]
    DIRECTION OUTPUT ;
    USE SIGNAL ;
    PORT
      LAYER M5 ;
        RECT  50.64 0 50.664 0.084 ;
    END
  END o[280]
  PIN o[281]
    DIRECTION OUTPUT ;
    USE SIGNAL ;
    PORT
      LAYER M5 ;
        RECT  50.736 0 50.76 0.084 ;
    END
  END o[281]
  PIN o[282]
    DIRECTION OUTPUT ;
    USE SIGNAL ;
    PORT
      LAYER M5 ;
        RECT  50.832 0 50.856 0.084 ;
    END
  END o[282]
  PIN o[283]
    DIRECTION OUTPUT ;
    USE SIGNAL ;
    PORT
      LAYER M5 ;
        RECT  50.928 0 50.952 0.084 ;
    END
  END o[283]
  PIN o[284]
    DIRECTION OUTPUT ;
    USE SIGNAL ;
    PORT
      LAYER M5 ;
        RECT  51.024 0 51.048 0.084 ;
    END
  END o[284]
  PIN o[285]
    DIRECTION OUTPUT ;
    USE SIGNAL ;
    PORT
      LAYER M5 ;
        RECT  51.12 0 51.144 0.084 ;
    END
  END o[285]
  PIN o[286]
    DIRECTION OUTPUT ;
    USE SIGNAL ;
    PORT
      LAYER M5 ;
        RECT  51.216 0 51.24 0.084 ;
    END
  END o[286]
  PIN o[287]
    DIRECTION OUTPUT ;
    USE SIGNAL ;
    PORT
      LAYER M5 ;
        RECT  51.312 0 51.336 0.084 ;
    END
  END o[287]
  PIN o[288]
    DIRECTION OUTPUT ;
    USE SIGNAL ;
    PORT
      LAYER M5 ;
        RECT  51.408 0 51.432 0.084 ;
    END
  END o[288]
  PIN o[289]
    DIRECTION OUTPUT ;
    USE SIGNAL ;
    PORT
      LAYER M5 ;
        RECT  51.504 0 51.528 0.084 ;
    END
  END o[289]
  PIN o[28]
    DIRECTION OUTPUT ;
    USE SIGNAL ;
    PORT
      LAYER M5 ;
        RECT  22.608 0 22.632 0.084 ;
    END
  END o[28]
  PIN o[290]
    DIRECTION OUTPUT ;
    USE SIGNAL ;
    PORT
      LAYER M5 ;
        RECT  51.6 0 51.624 0.084 ;
    END
  END o[290]
  PIN o[291]
    DIRECTION OUTPUT ;
    USE SIGNAL ;
    PORT
      LAYER M5 ;
        RECT  51.696 0 51.72 0.084 ;
    END
  END o[291]
  PIN o[292]
    DIRECTION OUTPUT ;
    USE SIGNAL ;
    PORT
      LAYER M5 ;
        RECT  51.792 0 51.816 0.084 ;
    END
  END o[292]
  PIN o[293]
    DIRECTION OUTPUT ;
    USE SIGNAL ;
    PORT
      LAYER M5 ;
        RECT  51.888 0 51.912 0.084 ;
    END
  END o[293]
  PIN o[294]
    DIRECTION OUTPUT ;
    USE SIGNAL ;
    PORT
      LAYER M5 ;
        RECT  51.984 0 52.008 0.084 ;
    END
  END o[294]
  PIN o[295]
    DIRECTION OUTPUT ;
    USE SIGNAL ;
    PORT
      LAYER M5 ;
        RECT  52.08 0 52.104 0.084 ;
    END
  END o[295]
  PIN o[296]
    DIRECTION OUTPUT ;
    USE SIGNAL ;
    PORT
      LAYER M5 ;
        RECT  52.176 0 52.2 0.084 ;
    END
  END o[296]
  PIN o[297]
    DIRECTION OUTPUT ;
    USE SIGNAL ;
    PORT
      LAYER M5 ;
        RECT  52.272 0 52.296 0.084 ;
    END
  END o[297]
  PIN o[298]
    DIRECTION OUTPUT ;
    USE SIGNAL ;
    PORT
      LAYER M5 ;
        RECT  52.368 0 52.392 0.084 ;
    END
  END o[298]
  PIN o[299]
    DIRECTION OUTPUT ;
    USE SIGNAL ;
    PORT
      LAYER M5 ;
        RECT  52.464 0 52.488 0.084 ;
    END
  END o[299]
  PIN o[29]
    DIRECTION OUTPUT ;
    USE SIGNAL ;
    PORT
      LAYER M5 ;
        RECT  22.704 0 22.728 0.084 ;
    END
  END o[29]
  PIN o[2]
    DIRECTION OUTPUT ;
    USE SIGNAL ;
    PORT
      LAYER M5 ;
        RECT  20.112 0 20.136 0.084 ;
    END
  END o[2]
  PIN o[300]
    DIRECTION OUTPUT ;
    USE SIGNAL ;
    PORT
      LAYER M5 ;
        RECT  52.56 0 52.584 0.084 ;
    END
  END o[300]
  PIN o[301]
    DIRECTION OUTPUT ;
    USE SIGNAL ;
    PORT
      LAYER M5 ;
        RECT  52.656 0 52.68 0.084 ;
    END
  END o[301]
  PIN o[302]
    DIRECTION OUTPUT ;
    USE SIGNAL ;
    PORT
      LAYER M5 ;
        RECT  52.752 0 52.776 0.084 ;
    END
  END o[302]
  PIN o[303]
    DIRECTION OUTPUT ;
    USE SIGNAL ;
    PORT
      LAYER M5 ;
        RECT  52.848 0 52.872 0.084 ;
    END
  END o[303]
  PIN o[304]
    DIRECTION OUTPUT ;
    USE SIGNAL ;
    PORT
      LAYER M5 ;
        RECT  52.944 0 52.968 0.084 ;
    END
  END o[304]
  PIN o[305]
    DIRECTION OUTPUT ;
    USE SIGNAL ;
    PORT
      LAYER M5 ;
        RECT  53.04 0 53.064 0.084 ;
    END
  END o[305]
  PIN o[306]
    DIRECTION OUTPUT ;
    USE SIGNAL ;
    PORT
      LAYER M5 ;
        RECT  53.136 0 53.16 0.084 ;
    END
  END o[306]
  PIN o[307]
    DIRECTION OUTPUT ;
    USE SIGNAL ;
    PORT
      LAYER M5 ;
        RECT  53.232 0 53.256 0.084 ;
    END
  END o[307]
  PIN o[308]
    DIRECTION OUTPUT ;
    USE SIGNAL ;
    PORT
      LAYER M5 ;
        RECT  53.328 0 53.352 0.084 ;
    END
  END o[308]
  PIN o[309]
    DIRECTION OUTPUT ;
    USE SIGNAL ;
    PORT
      LAYER M5 ;
        RECT  53.424 0 53.448 0.084 ;
    END
  END o[309]
  PIN o[30]
    DIRECTION OUTPUT ;
    USE SIGNAL ;
    PORT
      LAYER M5 ;
        RECT  22.8 0 22.824 0.084 ;
    END
  END o[30]
  PIN o[310]
    DIRECTION OUTPUT ;
    USE SIGNAL ;
    PORT
      LAYER M5 ;
        RECT  53.52 0 53.544 0.084 ;
    END
  END o[310]
  PIN o[311]
    DIRECTION OUTPUT ;
    USE SIGNAL ;
    PORT
      LAYER M5 ;
        RECT  53.616 0 53.64 0.084 ;
    END
  END o[311]
  PIN o[312]
    DIRECTION OUTPUT ;
    USE SIGNAL ;
    PORT
      LAYER M5 ;
        RECT  53.712 0 53.736 0.084 ;
    END
  END o[312]
  PIN o[313]
    DIRECTION OUTPUT ;
    USE SIGNAL ;
    PORT
      LAYER M5 ;
        RECT  53.808 0 53.832 0.084 ;
    END
  END o[313]
  PIN o[314]
    DIRECTION OUTPUT ;
    USE SIGNAL ;
    PORT
      LAYER M5 ;
        RECT  53.904 0 53.928 0.084 ;
    END
  END o[314]
  PIN o[315]
    DIRECTION OUTPUT ;
    USE SIGNAL ;
    PORT
      LAYER M5 ;
        RECT  54 0 54.024 0.084 ;
    END
  END o[315]
  PIN o[316]
    DIRECTION OUTPUT ;
    USE SIGNAL ;
    PORT
      LAYER M5 ;
        RECT  54.096 0 54.12 0.084 ;
    END
  END o[316]
  PIN o[317]
    DIRECTION OUTPUT ;
    USE SIGNAL ;
    PORT
      LAYER M5 ;
        RECT  54.192 0 54.216 0.084 ;
    END
  END o[317]
  PIN o[318]
    DIRECTION OUTPUT ;
    USE SIGNAL ;
    PORT
      LAYER M5 ;
        RECT  54.288 0 54.312 0.084 ;
    END
  END o[318]
  PIN o[319]
    DIRECTION OUTPUT ;
    USE SIGNAL ;
    PORT
      LAYER M5 ;
        RECT  54.384 0 54.408 0.084 ;
    END
  END o[319]
  PIN o[31]
    DIRECTION OUTPUT ;
    USE SIGNAL ;
    PORT
      LAYER M5 ;
        RECT  22.896 0 22.92 0.084 ;
    END
  END o[31]
  PIN o[320]
    DIRECTION OUTPUT ;
    USE SIGNAL ;
    PORT
      LAYER M5 ;
        RECT  45.264 0 45.288 0.084 ;
    END
  END o[320]
  PIN o[321]
    DIRECTION OUTPUT ;
    USE SIGNAL ;
    PORT
      LAYER M5 ;
        RECT  45.36 0 45.384 0.084 ;
    END
  END o[321]
  PIN o[322]
    DIRECTION OUTPUT ;
    USE SIGNAL ;
    PORT
      LAYER M5 ;
        RECT  45.456 0 45.48 0.084 ;
    END
  END o[322]
  PIN o[323]
    DIRECTION OUTPUT ;
    USE SIGNAL ;
    PORT
      LAYER M5 ;
        RECT  45.552 0 45.576 0.084 ;
    END
  END o[323]
  PIN o[324]
    DIRECTION OUTPUT ;
    USE SIGNAL ;
    PORT
      LAYER M5 ;
        RECT  45.648 0 45.672 0.084 ;
    END
  END o[324]
  PIN o[325]
    DIRECTION OUTPUT ;
    USE SIGNAL ;
    PORT
      LAYER M5 ;
        RECT  45.744 0 45.768 0.084 ;
    END
  END o[325]
  PIN o[326]
    DIRECTION OUTPUT ;
    USE SIGNAL ;
    PORT
      LAYER M5 ;
        RECT  45.84 0 45.864 0.084 ;
    END
  END o[326]
  PIN o[327]
    DIRECTION OUTPUT ;
    USE SIGNAL ;
    PORT
      LAYER M5 ;
        RECT  45.936 0 45.96 0.084 ;
    END
  END o[327]
  PIN o[328]
    DIRECTION OUTPUT ;
    USE SIGNAL ;
    PORT
      LAYER M5 ;
        RECT  46.032 0 46.056 0.084 ;
    END
  END o[328]
  PIN o[329]
    DIRECTION OUTPUT ;
    USE SIGNAL ;
    PORT
      LAYER M5 ;
        RECT  46.128 0 46.152 0.084 ;
    END
  END o[329]
  PIN o[32]
    DIRECTION OUTPUT ;
    USE SIGNAL ;
    PORT
      LAYER M5 ;
        RECT  22.992 0 23.016 0.084 ;
    END
  END o[32]
  PIN o[330]
    DIRECTION OUTPUT ;
    USE SIGNAL ;
    PORT
      LAYER M5 ;
        RECT  46.224 0 46.248 0.084 ;
    END
  END o[330]
  PIN o[331]
    DIRECTION OUTPUT ;
    USE SIGNAL ;
    PORT
      LAYER M5 ;
        RECT  46.32 0 46.344 0.084 ;
    END
  END o[331]
  PIN o[332]
    DIRECTION OUTPUT ;
    USE SIGNAL ;
    PORT
      LAYER M5 ;
        RECT  46.416 0 46.44 0.084 ;
    END
  END o[332]
  PIN o[333]
    DIRECTION OUTPUT ;
    USE SIGNAL ;
    PORT
      LAYER M5 ;
        RECT  46.512 0 46.536 0.084 ;
    END
  END o[333]
  PIN o[334]
    DIRECTION OUTPUT ;
    USE SIGNAL ;
    PORT
      LAYER M5 ;
        RECT  46.608 0 46.632 0.084 ;
    END
  END o[334]
  PIN o[335]
    DIRECTION OUTPUT ;
    USE SIGNAL ;
    PORT
      LAYER M5 ;
        RECT  46.704 0 46.728 0.084 ;
    END
  END o[335]
  PIN o[336]
    DIRECTION OUTPUT ;
    USE SIGNAL ;
    PORT
      LAYER M5 ;
        RECT  46.8 0 46.824 0.084 ;
    END
  END o[336]
  PIN o[337]
    DIRECTION OUTPUT ;
    USE SIGNAL ;
    PORT
      LAYER M5 ;
        RECT  46.896 0 46.92 0.084 ;
    END
  END o[337]
  PIN o[338]
    DIRECTION OUTPUT ;
    USE SIGNAL ;
    PORT
      LAYER M5 ;
        RECT  46.992 0 47.016 0.084 ;
    END
  END o[338]
  PIN o[339]
    DIRECTION OUTPUT ;
    USE SIGNAL ;
    PORT
      LAYER M5 ;
        RECT  47.088 0 47.112 0.084 ;
    END
  END o[339]
  PIN o[33]
    DIRECTION OUTPUT ;
    USE SIGNAL ;
    PORT
      LAYER M5 ;
        RECT  23.088 0 23.112 0.084 ;
    END
  END o[33]
  PIN o[340]
    DIRECTION OUTPUT ;
    USE SIGNAL ;
    PORT
      LAYER M5 ;
        RECT  47.184 0 47.208 0.084 ;
    END
  END o[340]
  PIN o[341]
    DIRECTION OUTPUT ;
    USE SIGNAL ;
    PORT
      LAYER M5 ;
        RECT  47.28 0 47.304 0.084 ;
    END
  END o[341]
  PIN o[342]
    DIRECTION OUTPUT ;
    USE SIGNAL ;
    PORT
      LAYER M5 ;
        RECT  47.376 0 47.4 0.084 ;
    END
  END o[342]
  PIN o[343]
    DIRECTION OUTPUT ;
    USE SIGNAL ;
    PORT
      LAYER M5 ;
        RECT  47.472 0 47.496 0.084 ;
    END
  END o[343]
  PIN o[344]
    DIRECTION OUTPUT ;
    USE SIGNAL ;
    PORT
      LAYER M5 ;
        RECT  47.568 0 47.592 0.084 ;
    END
  END o[344]
  PIN o[345]
    DIRECTION OUTPUT ;
    USE SIGNAL ;
    PORT
      LAYER M5 ;
        RECT  47.664 0 47.688 0.084 ;
    END
  END o[345]
  PIN o[346]
    DIRECTION OUTPUT ;
    USE SIGNAL ;
    PORT
      LAYER M5 ;
        RECT  47.76 0 47.784 0.084 ;
    END
  END o[346]
  PIN o[347]
    DIRECTION OUTPUT ;
    USE SIGNAL ;
    PORT
      LAYER M5 ;
        RECT  47.856 0 47.88 0.084 ;
    END
  END o[347]
  PIN o[348]
    DIRECTION OUTPUT ;
    USE SIGNAL ;
    PORT
      LAYER M5 ;
        RECT  47.952 0 47.976 0.084 ;
    END
  END o[348]
  PIN o[349]
    DIRECTION OUTPUT ;
    USE SIGNAL ;
    PORT
      LAYER M5 ;
        RECT  48.048 0 48.072 0.084 ;
    END
  END o[349]
  PIN o[34]
    DIRECTION OUTPUT ;
    USE SIGNAL ;
    PORT
      LAYER M5 ;
        RECT  23.184 0 23.208 0.084 ;
    END
  END o[34]
  PIN o[350]
    DIRECTION OUTPUT ;
    USE SIGNAL ;
    PORT
      LAYER M5 ;
        RECT  48.144 0 48.168 0.084 ;
    END
  END o[350]
  PIN o[351]
    DIRECTION OUTPUT ;
    USE SIGNAL ;
    PORT
      LAYER M5 ;
        RECT  48.24 0 48.264 0.084 ;
    END
  END o[351]
  PIN o[352]
    DIRECTION OUTPUT ;
    USE SIGNAL ;
    PORT
      LAYER M5 ;
        RECT  54.48 0 54.504 0.084 ;
    END
  END o[352]
  PIN o[353]
    DIRECTION OUTPUT ;
    USE SIGNAL ;
    PORT
      LAYER M5 ;
        RECT  54.576 0 54.6 0.084 ;
    END
  END o[353]
  PIN o[354]
    DIRECTION OUTPUT ;
    USE SIGNAL ;
    PORT
      LAYER M5 ;
        RECT  54.672 0 54.696 0.084 ;
    END
  END o[354]
  PIN o[355]
    DIRECTION OUTPUT ;
    USE SIGNAL ;
    PORT
      LAYER M5 ;
        RECT  54.768 0 54.792 0.084 ;
    END
  END o[355]
  PIN o[356]
    DIRECTION OUTPUT ;
    USE SIGNAL ;
    PORT
      LAYER M5 ;
        RECT  54.864 0 54.888 0.084 ;
    END
  END o[356]
  PIN o[357]
    DIRECTION OUTPUT ;
    USE SIGNAL ;
    PORT
      LAYER M5 ;
        RECT  54.96 0 54.984 0.084 ;
    END
  END o[357]
  PIN o[358]
    DIRECTION OUTPUT ;
    USE SIGNAL ;
    PORT
      LAYER M5 ;
        RECT  55.056 0 55.08 0.084 ;
    END
  END o[358]
  PIN o[359]
    DIRECTION OUTPUT ;
    USE SIGNAL ;
    PORT
      LAYER M5 ;
        RECT  55.152 0 55.176 0.084 ;
    END
  END o[359]
  PIN o[35]
    DIRECTION OUTPUT ;
    USE SIGNAL ;
    PORT
      LAYER M5 ;
        RECT  23.28 0 23.304 0.084 ;
    END
  END o[35]
  PIN o[360]
    DIRECTION OUTPUT ;
    USE SIGNAL ;
    PORT
      LAYER M5 ;
        RECT  55.248 0 55.272 0.084 ;
    END
  END o[360]
  PIN o[361]
    DIRECTION OUTPUT ;
    USE SIGNAL ;
    PORT
      LAYER M5 ;
        RECT  55.344 0 55.368 0.084 ;
    END
  END o[361]
  PIN o[362]
    DIRECTION OUTPUT ;
    USE SIGNAL ;
    PORT
      LAYER M5 ;
        RECT  55.44 0 55.464 0.084 ;
    END
  END o[362]
  PIN o[363]
    DIRECTION OUTPUT ;
    USE SIGNAL ;
    PORT
      LAYER M5 ;
        RECT  55.536 0 55.56 0.084 ;
    END
  END o[363]
  PIN o[364]
    DIRECTION OUTPUT ;
    USE SIGNAL ;
    PORT
      LAYER M5 ;
        RECT  55.632 0 55.656 0.084 ;
    END
  END o[364]
  PIN o[365]
    DIRECTION OUTPUT ;
    USE SIGNAL ;
    PORT
      LAYER M5 ;
        RECT  55.728 0 55.752 0.084 ;
    END
  END o[365]
  PIN o[366]
    DIRECTION OUTPUT ;
    USE SIGNAL ;
    PORT
      LAYER M5 ;
        RECT  55.824 0 55.848 0.084 ;
    END
  END o[366]
  PIN o[367]
    DIRECTION OUTPUT ;
    USE SIGNAL ;
    PORT
      LAYER M5 ;
        RECT  55.92 0 55.944 0.084 ;
    END
  END o[367]
  PIN o[368]
    DIRECTION OUTPUT ;
    USE SIGNAL ;
    PORT
      LAYER M5 ;
        RECT  56.016 0 56.04 0.084 ;
    END
  END o[368]
  PIN o[369]
    DIRECTION OUTPUT ;
    USE SIGNAL ;
    PORT
      LAYER M5 ;
        RECT  56.112 0 56.136 0.084 ;
    END
  END o[369]
  PIN o[36]
    DIRECTION OUTPUT ;
    USE SIGNAL ;
    PORT
      LAYER M5 ;
        RECT  23.376 0 23.4 0.084 ;
    END
  END o[36]
  PIN o[370]
    DIRECTION OUTPUT ;
    USE SIGNAL ;
    PORT
      LAYER M5 ;
        RECT  56.208 0 56.232 0.084 ;
    END
  END o[370]
  PIN o[371]
    DIRECTION OUTPUT ;
    USE SIGNAL ;
    PORT
      LAYER M5 ;
        RECT  56.304 0 56.328 0.084 ;
    END
  END o[371]
  PIN o[372]
    DIRECTION OUTPUT ;
    USE SIGNAL ;
    PORT
      LAYER M5 ;
        RECT  56.4 0 56.424 0.084 ;
    END
  END o[372]
  PIN o[373]
    DIRECTION OUTPUT ;
    USE SIGNAL ;
    PORT
      LAYER M5 ;
        RECT  56.496 0 56.52 0.084 ;
    END
  END o[373]
  PIN o[374]
    DIRECTION OUTPUT ;
    USE SIGNAL ;
    PORT
      LAYER M5 ;
        RECT  56.592 0 56.616 0.084 ;
    END
  END o[374]
  PIN o[375]
    DIRECTION OUTPUT ;
    USE SIGNAL ;
    PORT
      LAYER M5 ;
        RECT  56.688 0 56.712 0.084 ;
    END
  END o[375]
  PIN o[376]
    DIRECTION OUTPUT ;
    USE SIGNAL ;
    PORT
      LAYER M5 ;
        RECT  56.784 0 56.808 0.084 ;
    END
  END o[376]
  PIN o[377]
    DIRECTION OUTPUT ;
    USE SIGNAL ;
    PORT
      LAYER M5 ;
        RECT  56.88 0 56.904 0.084 ;
    END
  END o[377]
  PIN o[378]
    DIRECTION OUTPUT ;
    USE SIGNAL ;
    PORT
      LAYER M5 ;
        RECT  56.976 0 57 0.084 ;
    END
  END o[378]
  PIN o[379]
    DIRECTION OUTPUT ;
    USE SIGNAL ;
    PORT
      LAYER M5 ;
        RECT  57.072 0 57.096 0.084 ;
    END
  END o[379]
  PIN o[37]
    DIRECTION OUTPUT ;
    USE SIGNAL ;
    PORT
      LAYER M5 ;
        RECT  23.472 0 23.496 0.084 ;
    END
  END o[37]
  PIN o[380]
    DIRECTION OUTPUT ;
    USE SIGNAL ;
    PORT
      LAYER M5 ;
        RECT  57.168 0 57.192 0.084 ;
    END
  END o[380]
  PIN o[381]
    DIRECTION OUTPUT ;
    USE SIGNAL ;
    PORT
      LAYER M5 ;
        RECT  57.264 0 57.288 0.084 ;
    END
  END o[381]
  PIN o[382]
    DIRECTION OUTPUT ;
    USE SIGNAL ;
    PORT
      LAYER M5 ;
        RECT  57.36 0 57.384 0.084 ;
    END
  END o[382]
  PIN o[383]
    DIRECTION OUTPUT ;
    USE SIGNAL ;
    PORT
      LAYER M5 ;
        RECT  57.456 0 57.48 0.084 ;
    END
  END o[383]
  PIN o[384]
    DIRECTION OUTPUT ;
    USE SIGNAL ;
    PORT
      LAYER M5 ;
        RECT  42.192 0 42.216 0.084 ;
    END
  END o[384]
  PIN o[385]
    DIRECTION OUTPUT ;
    USE SIGNAL ;
    PORT
      LAYER M5 ;
        RECT  42.288 0 42.312 0.084 ;
    END
  END o[385]
  PIN o[386]
    DIRECTION OUTPUT ;
    USE SIGNAL ;
    PORT
      LAYER M5 ;
        RECT  42.384 0 42.408 0.084 ;
    END
  END o[386]
  PIN o[387]
    DIRECTION OUTPUT ;
    USE SIGNAL ;
    PORT
      LAYER M5 ;
        RECT  42.48 0 42.504 0.084 ;
    END
  END o[387]
  PIN o[388]
    DIRECTION OUTPUT ;
    USE SIGNAL ;
    PORT
      LAYER M5 ;
        RECT  42.576 0 42.6 0.084 ;
    END
  END o[388]
  PIN o[389]
    DIRECTION OUTPUT ;
    USE SIGNAL ;
    PORT
      LAYER M5 ;
        RECT  42.672 0 42.696 0.084 ;
    END
  END o[389]
  PIN o[38]
    DIRECTION OUTPUT ;
    USE SIGNAL ;
    PORT
      LAYER M5 ;
        RECT  23.568 0 23.592 0.084 ;
    END
  END o[38]
  PIN o[390]
    DIRECTION OUTPUT ;
    USE SIGNAL ;
    PORT
      LAYER M5 ;
        RECT  42.768 0 42.792 0.084 ;
    END
  END o[390]
  PIN o[391]
    DIRECTION OUTPUT ;
    USE SIGNAL ;
    PORT
      LAYER M5 ;
        RECT  42.864 0 42.888 0.084 ;
    END
  END o[391]
  PIN o[392]
    DIRECTION OUTPUT ;
    USE SIGNAL ;
    PORT
      LAYER M5 ;
        RECT  42.96 0 42.984 0.084 ;
    END
  END o[392]
  PIN o[393]
    DIRECTION OUTPUT ;
    USE SIGNAL ;
    PORT
      LAYER M5 ;
        RECT  43.056 0 43.08 0.084 ;
    END
  END o[393]
  PIN o[394]
    DIRECTION OUTPUT ;
    USE SIGNAL ;
    PORT
      LAYER M5 ;
        RECT  43.152 0 43.176 0.084 ;
    END
  END o[394]
  PIN o[395]
    DIRECTION OUTPUT ;
    USE SIGNAL ;
    PORT
      LAYER M5 ;
        RECT  43.248 0 43.272 0.084 ;
    END
  END o[395]
  PIN o[396]
    DIRECTION OUTPUT ;
    USE SIGNAL ;
    PORT
      LAYER M5 ;
        RECT  43.344 0 43.368 0.084 ;
    END
  END o[396]
  PIN o[397]
    DIRECTION OUTPUT ;
    USE SIGNAL ;
    PORT
      LAYER M5 ;
        RECT  43.44 0 43.464 0.084 ;
    END
  END o[397]
  PIN o[398]
    DIRECTION OUTPUT ;
    USE SIGNAL ;
    PORT
      LAYER M5 ;
        RECT  43.536 0 43.56 0.084 ;
    END
  END o[398]
  PIN o[399]
    DIRECTION OUTPUT ;
    USE SIGNAL ;
    PORT
      LAYER M5 ;
        RECT  43.632 0 43.656 0.084 ;
    END
  END o[399]
  PIN o[39]
    DIRECTION OUTPUT ;
    USE SIGNAL ;
    PORT
      LAYER M5 ;
        RECT  23.664 0 23.688 0.084 ;
    END
  END o[39]
  PIN o[3]
    DIRECTION OUTPUT ;
    USE SIGNAL ;
    PORT
      LAYER M5 ;
        RECT  20.208 0 20.232 0.084 ;
    END
  END o[3]
  PIN o[400]
    DIRECTION OUTPUT ;
    USE SIGNAL ;
    PORT
      LAYER M5 ;
        RECT  43.728 0 43.752 0.084 ;
    END
  END o[400]
  PIN o[401]
    DIRECTION OUTPUT ;
    USE SIGNAL ;
    PORT
      LAYER M5 ;
        RECT  43.824 0 43.848 0.084 ;
    END
  END o[401]
  PIN o[402]
    DIRECTION OUTPUT ;
    USE SIGNAL ;
    PORT
      LAYER M5 ;
        RECT  43.92 0 43.944 0.084 ;
    END
  END o[402]
  PIN o[403]
    DIRECTION OUTPUT ;
    USE SIGNAL ;
    PORT
      LAYER M5 ;
        RECT  44.016 0 44.04 0.084 ;
    END
  END o[403]
  PIN o[404]
    DIRECTION OUTPUT ;
    USE SIGNAL ;
    PORT
      LAYER M5 ;
        RECT  44.112 0 44.136 0.084 ;
    END
  END o[404]
  PIN o[405]
    DIRECTION OUTPUT ;
    USE SIGNAL ;
    PORT
      LAYER M5 ;
        RECT  44.208 0 44.232 0.084 ;
    END
  END o[405]
  PIN o[406]
    DIRECTION OUTPUT ;
    USE SIGNAL ;
    PORT
      LAYER M5 ;
        RECT  44.304 0 44.328 0.084 ;
    END
  END o[406]
  PIN o[407]
    DIRECTION OUTPUT ;
    USE SIGNAL ;
    PORT
      LAYER M5 ;
        RECT  44.4 0 44.424 0.084 ;
    END
  END o[407]
  PIN o[408]
    DIRECTION OUTPUT ;
    USE SIGNAL ;
    PORT
      LAYER M5 ;
        RECT  44.496 0 44.52 0.084 ;
    END
  END o[408]
  PIN o[409]
    DIRECTION OUTPUT ;
    USE SIGNAL ;
    PORT
      LAYER M5 ;
        RECT  44.592 0 44.616 0.084 ;
    END
  END o[409]
  PIN o[40]
    DIRECTION OUTPUT ;
    USE SIGNAL ;
    PORT
      LAYER M5 ;
        RECT  23.76 0 23.784 0.084 ;
    END
  END o[40]
  PIN o[410]
    DIRECTION OUTPUT ;
    USE SIGNAL ;
    PORT
      LAYER M5 ;
        RECT  44.688 0 44.712 0.084 ;
    END
  END o[410]
  PIN o[411]
    DIRECTION OUTPUT ;
    USE SIGNAL ;
    PORT
      LAYER M5 ;
        RECT  44.784 0 44.808 0.084 ;
    END
  END o[411]
  PIN o[412]
    DIRECTION OUTPUT ;
    USE SIGNAL ;
    PORT
      LAYER M5 ;
        RECT  44.88 0 44.904 0.084 ;
    END
  END o[412]
  PIN o[413]
    DIRECTION OUTPUT ;
    USE SIGNAL ;
    PORT
      LAYER M5 ;
        RECT  44.976 0 45 0.084 ;
    END
  END o[413]
  PIN o[414]
    DIRECTION OUTPUT ;
    USE SIGNAL ;
    PORT
      LAYER M5 ;
        RECT  45.072 0 45.096 0.084 ;
    END
  END o[414]
  PIN o[415]
    DIRECTION OUTPUT ;
    USE SIGNAL ;
    PORT
      LAYER M5 ;
        RECT  45.168 0 45.192 0.084 ;
    END
  END o[415]
  PIN o[416]
    DIRECTION OUTPUT ;
    USE SIGNAL ;
    PORT
      LAYER M5 ;
        RECT  39.12 0 39.144 0.084 ;
    END
  END o[416]
  PIN o[417]
    DIRECTION OUTPUT ;
    USE SIGNAL ;
    PORT
      LAYER M5 ;
        RECT  39.216 0 39.24 0.084 ;
    END
  END o[417]
  PIN o[418]
    DIRECTION OUTPUT ;
    USE SIGNAL ;
    PORT
      LAYER M5 ;
        RECT  39.312 0 39.336 0.084 ;
    END
  END o[418]
  PIN o[419]
    DIRECTION OUTPUT ;
    USE SIGNAL ;
    PORT
      LAYER M5 ;
        RECT  39.408 0 39.432 0.084 ;
    END
  END o[419]
  PIN o[41]
    DIRECTION OUTPUT ;
    USE SIGNAL ;
    PORT
      LAYER M5 ;
        RECT  23.856 0 23.88 0.084 ;
    END
  END o[41]
  PIN o[420]
    DIRECTION OUTPUT ;
    USE SIGNAL ;
    PORT
      LAYER M5 ;
        RECT  39.504 0 39.528 0.084 ;
    END
  END o[420]
  PIN o[421]
    DIRECTION OUTPUT ;
    USE SIGNAL ;
    PORT
      LAYER M5 ;
        RECT  39.6 0 39.624 0.084 ;
    END
  END o[421]
  PIN o[422]
    DIRECTION OUTPUT ;
    USE SIGNAL ;
    PORT
      LAYER M5 ;
        RECT  39.696 0 39.72 0.084 ;
    END
  END o[422]
  PIN o[423]
    DIRECTION OUTPUT ;
    USE SIGNAL ;
    PORT
      LAYER M5 ;
        RECT  39.792 0 39.816 0.084 ;
    END
  END o[423]
  PIN o[424]
    DIRECTION OUTPUT ;
    USE SIGNAL ;
    PORT
      LAYER M5 ;
        RECT  39.888 0 39.912 0.084 ;
    END
  END o[424]
  PIN o[425]
    DIRECTION OUTPUT ;
    USE SIGNAL ;
    PORT
      LAYER M5 ;
        RECT  39.984 0 40.008 0.084 ;
    END
  END o[425]
  PIN o[426]
    DIRECTION OUTPUT ;
    USE SIGNAL ;
    PORT
      LAYER M5 ;
        RECT  40.08 0 40.104 0.084 ;
    END
  END o[426]
  PIN o[427]
    DIRECTION OUTPUT ;
    USE SIGNAL ;
    PORT
      LAYER M5 ;
        RECT  40.176 0 40.2 0.084 ;
    END
  END o[427]
  PIN o[428]
    DIRECTION OUTPUT ;
    USE SIGNAL ;
    PORT
      LAYER M5 ;
        RECT  40.272 0 40.296 0.084 ;
    END
  END o[428]
  PIN o[429]
    DIRECTION OUTPUT ;
    USE SIGNAL ;
    PORT
      LAYER M5 ;
        RECT  40.368 0 40.392 0.084 ;
    END
  END o[429]
  PIN o[42]
    DIRECTION OUTPUT ;
    USE SIGNAL ;
    PORT
      LAYER M5 ;
        RECT  23.952 0 23.976 0.084 ;
    END
  END o[42]
  PIN o[430]
    DIRECTION OUTPUT ;
    USE SIGNAL ;
    PORT
      LAYER M5 ;
        RECT  40.464 0 40.488 0.084 ;
    END
  END o[430]
  PIN o[431]
    DIRECTION OUTPUT ;
    USE SIGNAL ;
    PORT
      LAYER M5 ;
        RECT  40.56 0 40.584 0.084 ;
    END
  END o[431]
  PIN o[432]
    DIRECTION OUTPUT ;
    USE SIGNAL ;
    PORT
      LAYER M5 ;
        RECT  40.656 0 40.68 0.084 ;
    END
  END o[432]
  PIN o[433]
    DIRECTION OUTPUT ;
    USE SIGNAL ;
    PORT
      LAYER M5 ;
        RECT  40.752 0 40.776 0.084 ;
    END
  END o[433]
  PIN o[434]
    DIRECTION OUTPUT ;
    USE SIGNAL ;
    PORT
      LAYER M5 ;
        RECT  40.848 0 40.872 0.084 ;
    END
  END o[434]
  PIN o[435]
    DIRECTION OUTPUT ;
    USE SIGNAL ;
    PORT
      LAYER M5 ;
        RECT  40.944 0 40.968 0.084 ;
    END
  END o[435]
  PIN o[436]
    DIRECTION OUTPUT ;
    USE SIGNAL ;
    PORT
      LAYER M5 ;
        RECT  41.04 0 41.064 0.084 ;
    END
  END o[436]
  PIN o[437]
    DIRECTION OUTPUT ;
    USE SIGNAL ;
    PORT
      LAYER M5 ;
        RECT  41.136 0 41.16 0.084 ;
    END
  END o[437]
  PIN o[438]
    DIRECTION OUTPUT ;
    USE SIGNAL ;
    PORT
      LAYER M5 ;
        RECT  41.232 0 41.256 0.084 ;
    END
  END o[438]
  PIN o[439]
    DIRECTION OUTPUT ;
    USE SIGNAL ;
    PORT
      LAYER M5 ;
        RECT  41.328 0 41.352 0.084 ;
    END
  END o[439]
  PIN o[43]
    DIRECTION OUTPUT ;
    USE SIGNAL ;
    PORT
      LAYER M5 ;
        RECT  24.048 0 24.072 0.084 ;
    END
  END o[43]
  PIN o[440]
    DIRECTION OUTPUT ;
    USE SIGNAL ;
    PORT
      LAYER M5 ;
        RECT  41.424 0 41.448 0.084 ;
    END
  END o[440]
  PIN o[441]
    DIRECTION OUTPUT ;
    USE SIGNAL ;
    PORT
      LAYER M5 ;
        RECT  41.52 0 41.544 0.084 ;
    END
  END o[441]
  PIN o[442]
    DIRECTION OUTPUT ;
    USE SIGNAL ;
    PORT
      LAYER M5 ;
        RECT  41.616 0 41.64 0.084 ;
    END
  END o[442]
  PIN o[443]
    DIRECTION OUTPUT ;
    USE SIGNAL ;
    PORT
      LAYER M5 ;
        RECT  41.712 0 41.736 0.084 ;
    END
  END o[443]
  PIN o[444]
    DIRECTION OUTPUT ;
    USE SIGNAL ;
    PORT
      LAYER M5 ;
        RECT  41.808 0 41.832 0.084 ;
    END
  END o[444]
  PIN o[445]
    DIRECTION OUTPUT ;
    USE SIGNAL ;
    PORT
      LAYER M5 ;
        RECT  41.904 0 41.928 0.084 ;
    END
  END o[445]
  PIN o[446]
    DIRECTION OUTPUT ;
    USE SIGNAL ;
    PORT
      LAYER M5 ;
        RECT  42 0 42.024 0.084 ;
    END
  END o[446]
  PIN o[447]
    DIRECTION OUTPUT ;
    USE SIGNAL ;
    PORT
      LAYER M5 ;
        RECT  42.096 0 42.12 0.084 ;
    END
  END o[447]
  PIN o[448]
    DIRECTION OUTPUT ;
    USE SIGNAL ;
    PORT
      LAYER M5 ;
        RECT  9.936 0 9.96 0.084 ;
    END
  END o[448]
  PIN o[449]
    DIRECTION OUTPUT ;
    USE SIGNAL ;
    PORT
      LAYER M5 ;
        RECT  10.032 0 10.056 0.084 ;
    END
  END o[449]
  PIN o[44]
    DIRECTION OUTPUT ;
    USE SIGNAL ;
    PORT
      LAYER M5 ;
        RECT  24.144 0 24.168 0.084 ;
    END
  END o[44]
  PIN o[450]
    DIRECTION OUTPUT ;
    USE SIGNAL ;
    PORT
      LAYER M5 ;
        RECT  10.128 0 10.152 0.084 ;
    END
  END o[450]
  PIN o[451]
    DIRECTION OUTPUT ;
    USE SIGNAL ;
    PORT
      LAYER M5 ;
        RECT  10.224 0 10.248 0.084 ;
    END
  END o[451]
  PIN o[452]
    DIRECTION OUTPUT ;
    USE SIGNAL ;
    PORT
      LAYER M5 ;
        RECT  10.32 0 10.344 0.084 ;
    END
  END o[452]
  PIN o[453]
    DIRECTION OUTPUT ;
    USE SIGNAL ;
    PORT
      LAYER M5 ;
        RECT  10.416 0 10.44 0.084 ;
    END
  END o[453]
  PIN o[454]
    DIRECTION OUTPUT ;
    USE SIGNAL ;
    PORT
      LAYER M5 ;
        RECT  10.512 0 10.536 0.084 ;
    END
  END o[454]
  PIN o[455]
    DIRECTION OUTPUT ;
    USE SIGNAL ;
    PORT
      LAYER M5 ;
        RECT  10.608 0 10.632 0.084 ;
    END
  END o[455]
  PIN o[456]
    DIRECTION OUTPUT ;
    USE SIGNAL ;
    PORT
      LAYER M5 ;
        RECT  10.704 0 10.728 0.084 ;
    END
  END o[456]
  PIN o[457]
    DIRECTION OUTPUT ;
    USE SIGNAL ;
    PORT
      LAYER M5 ;
        RECT  10.8 0 10.824 0.084 ;
    END
  END o[457]
  PIN o[458]
    DIRECTION OUTPUT ;
    USE SIGNAL ;
    PORT
      LAYER M5 ;
        RECT  10.896 0 10.92 0.084 ;
    END
  END o[458]
  PIN o[459]
    DIRECTION OUTPUT ;
    USE SIGNAL ;
    PORT
      LAYER M5 ;
        RECT  10.992 0 11.016 0.084 ;
    END
  END o[459]
  PIN o[45]
    DIRECTION OUTPUT ;
    USE SIGNAL ;
    PORT
      LAYER M5 ;
        RECT  24.24 0 24.264 0.084 ;
    END
  END o[45]
  PIN o[460]
    DIRECTION OUTPUT ;
    USE SIGNAL ;
    PORT
      LAYER M5 ;
        RECT  11.088 0 11.112 0.084 ;
    END
  END o[460]
  PIN o[461]
    DIRECTION OUTPUT ;
    USE SIGNAL ;
    PORT
      LAYER M5 ;
        RECT  11.184 0 11.208 0.084 ;
    END
  END o[461]
  PIN o[462]
    DIRECTION OUTPUT ;
    USE SIGNAL ;
    PORT
      LAYER M5 ;
        RECT  11.28 0 11.304 0.084 ;
    END
  END o[462]
  PIN o[463]
    DIRECTION OUTPUT ;
    USE SIGNAL ;
    PORT
      LAYER M5 ;
        RECT  11.376 0 11.4 0.084 ;
    END
  END o[463]
  PIN o[464]
    DIRECTION OUTPUT ;
    USE SIGNAL ;
    PORT
      LAYER M5 ;
        RECT  11.472 0 11.496 0.084 ;
    END
  END o[464]
  PIN o[465]
    DIRECTION OUTPUT ;
    USE SIGNAL ;
    PORT
      LAYER M5 ;
        RECT  11.568 0 11.592 0.084 ;
    END
  END o[465]
  PIN o[466]
    DIRECTION OUTPUT ;
    USE SIGNAL ;
    PORT
      LAYER M5 ;
        RECT  11.664 0 11.688 0.084 ;
    END
  END o[466]
  PIN o[467]
    DIRECTION OUTPUT ;
    USE SIGNAL ;
    PORT
      LAYER M5 ;
        RECT  11.76 0 11.784 0.084 ;
    END
  END o[467]
  PIN o[468]
    DIRECTION OUTPUT ;
    USE SIGNAL ;
    PORT
      LAYER M5 ;
        RECT  11.856 0 11.88 0.084 ;
    END
  END o[468]
  PIN o[469]
    DIRECTION OUTPUT ;
    USE SIGNAL ;
    PORT
      LAYER M5 ;
        RECT  11.952 0 11.976 0.084 ;
    END
  END o[469]
  PIN o[46]
    DIRECTION OUTPUT ;
    USE SIGNAL ;
    PORT
      LAYER M5 ;
        RECT  24.336 0 24.36 0.084 ;
    END
  END o[46]
  PIN o[470]
    DIRECTION OUTPUT ;
    USE SIGNAL ;
    PORT
      LAYER M5 ;
        RECT  12.048 0 12.072 0.084 ;
    END
  END o[470]
  PIN o[471]
    DIRECTION OUTPUT ;
    USE SIGNAL ;
    PORT
      LAYER M5 ;
        RECT  12.144 0 12.168 0.084 ;
    END
  END o[471]
  PIN o[472]
    DIRECTION OUTPUT ;
    USE SIGNAL ;
    PORT
      LAYER M5 ;
        RECT  12.24 0 12.264 0.084 ;
    END
  END o[472]
  PIN o[473]
    DIRECTION OUTPUT ;
    USE SIGNAL ;
    PORT
      LAYER M5 ;
        RECT  12.336 0 12.36 0.084 ;
    END
  END o[473]
  PIN o[474]
    DIRECTION OUTPUT ;
    USE SIGNAL ;
    PORT
      LAYER M5 ;
        RECT  12.432 0 12.456 0.084 ;
    END
  END o[474]
  PIN o[475]
    DIRECTION OUTPUT ;
    USE SIGNAL ;
    PORT
      LAYER M5 ;
        RECT  12.528 0 12.552 0.084 ;
    END
  END o[475]
  PIN o[476]
    DIRECTION OUTPUT ;
    USE SIGNAL ;
    PORT
      LAYER M5 ;
        RECT  12.624 0 12.648 0.084 ;
    END
  END o[476]
  PIN o[477]
    DIRECTION OUTPUT ;
    USE SIGNAL ;
    PORT
      LAYER M5 ;
        RECT  12.72 0 12.744 0.084 ;
    END
  END o[477]
  PIN o[478]
    DIRECTION OUTPUT ;
    USE SIGNAL ;
    PORT
      LAYER M5 ;
        RECT  12.816 0 12.84 0.084 ;
    END
  END o[478]
  PIN o[479]
    DIRECTION OUTPUT ;
    USE SIGNAL ;
    PORT
      LAYER M5 ;
        RECT  12.912 0 12.936 0.084 ;
    END
  END o[479]
  PIN o[47]
    DIRECTION OUTPUT ;
    USE SIGNAL ;
    PORT
      LAYER M5 ;
        RECT  24.432 0 24.456 0.084 ;
    END
  END o[47]
  PIN o[480]
    DIRECTION OUTPUT ;
    USE SIGNAL ;
    PORT
      LAYER M5 ;
        RECT  58.32 0 58.344 0.084 ;
    END
  END o[480]
  PIN o[481]
    DIRECTION OUTPUT ;
    USE SIGNAL ;
    PORT
      LAYER M5 ;
        RECT  58.416 0 58.44 0.084 ;
    END
  END o[481]
  PIN o[482]
    DIRECTION OUTPUT ;
    USE SIGNAL ;
    PORT
      LAYER M5 ;
        RECT  58.512 0 58.536 0.084 ;
    END
  END o[482]
  PIN o[483]
    DIRECTION OUTPUT ;
    USE SIGNAL ;
    PORT
      LAYER M5 ;
        RECT  58.608 0 58.632 0.084 ;
    END
  END o[483]
  PIN o[484]
    DIRECTION OUTPUT ;
    USE SIGNAL ;
    PORT
      LAYER M5 ;
        RECT  58.704 0 58.728 0.084 ;
    END
  END o[484]
  PIN o[485]
    DIRECTION OUTPUT ;
    USE SIGNAL ;
    PORT
      LAYER M5 ;
        RECT  58.8 0 58.824 0.084 ;
    END
  END o[485]
  PIN o[486]
    DIRECTION OUTPUT ;
    USE SIGNAL ;
    PORT
      LAYER M5 ;
        RECT  58.896 0 58.92 0.084 ;
    END
  END o[486]
  PIN o[487]
    DIRECTION OUTPUT ;
    USE SIGNAL ;
    PORT
      LAYER M5 ;
        RECT  58.992 0 59.016 0.084 ;
    END
  END o[487]
  PIN o[488]
    DIRECTION OUTPUT ;
    USE SIGNAL ;
    PORT
      LAYER M5 ;
        RECT  59.088 0 59.112 0.084 ;
    END
  END o[488]
  PIN o[489]
    DIRECTION OUTPUT ;
    USE SIGNAL ;
    PORT
      LAYER M5 ;
        RECT  59.184 0 59.208 0.084 ;
    END
  END o[489]
  PIN o[48]
    DIRECTION OUTPUT ;
    USE SIGNAL ;
    PORT
      LAYER M5 ;
        RECT  24.528 0 24.552 0.084 ;
    END
  END o[48]
  PIN o[490]
    DIRECTION OUTPUT ;
    USE SIGNAL ;
    PORT
      LAYER M5 ;
        RECT  59.28 0 59.304 0.084 ;
    END
  END o[490]
  PIN o[491]
    DIRECTION OUTPUT ;
    USE SIGNAL ;
    PORT
      LAYER M5 ;
        RECT  59.376 0 59.4 0.084 ;
    END
  END o[491]
  PIN o[492]
    DIRECTION OUTPUT ;
    USE SIGNAL ;
    PORT
      LAYER M5 ;
        RECT  59.472 0 59.496 0.084 ;
    END
  END o[492]
  PIN o[493]
    DIRECTION OUTPUT ;
    USE SIGNAL ;
    PORT
      LAYER M5 ;
        RECT  59.568 0 59.592 0.084 ;
    END
  END o[493]
  PIN o[494]
    DIRECTION OUTPUT ;
    USE SIGNAL ;
    PORT
      LAYER M5 ;
        RECT  59.664 0 59.688 0.084 ;
    END
  END o[494]
  PIN o[495]
    DIRECTION OUTPUT ;
    USE SIGNAL ;
    PORT
      LAYER M5 ;
        RECT  59.76 0 59.784 0.084 ;
    END
  END o[495]
  PIN o[496]
    DIRECTION OUTPUT ;
    USE SIGNAL ;
    PORT
      LAYER M5 ;
        RECT  59.856 0 59.88 0.084 ;
    END
  END o[496]
  PIN o[497]
    DIRECTION OUTPUT ;
    USE SIGNAL ;
    PORT
      LAYER M5 ;
        RECT  59.952 0 59.976 0.084 ;
    END
  END o[497]
  PIN o[498]
    DIRECTION OUTPUT ;
    USE SIGNAL ;
    PORT
      LAYER M5 ;
        RECT  60.048 0 60.072 0.084 ;
    END
  END o[498]
  PIN o[499]
    DIRECTION OUTPUT ;
    USE SIGNAL ;
    PORT
      LAYER M5 ;
        RECT  60.144 0 60.168 0.084 ;
    END
  END o[499]
  PIN o[49]
    DIRECTION OUTPUT ;
    USE SIGNAL ;
    PORT
      LAYER M5 ;
        RECT  24.624 0 24.648 0.084 ;
    END
  END o[49]
  PIN o[4]
    DIRECTION OUTPUT ;
    USE SIGNAL ;
    PORT
      LAYER M5 ;
        RECT  20.304 0 20.328 0.084 ;
    END
  END o[4]
  PIN o[500]
    DIRECTION OUTPUT ;
    USE SIGNAL ;
    PORT
      LAYER M5 ;
        RECT  60.24 0 60.264 0.084 ;
    END
  END o[500]
  PIN o[501]
    DIRECTION OUTPUT ;
    USE SIGNAL ;
    PORT
      LAYER M5 ;
        RECT  60.336 0 60.36 0.084 ;
    END
  END o[501]
  PIN o[502]
    DIRECTION OUTPUT ;
    USE SIGNAL ;
    PORT
      LAYER M5 ;
        RECT  60.432 0 60.456 0.084 ;
    END
  END o[502]
  PIN o[503]
    DIRECTION OUTPUT ;
    USE SIGNAL ;
    PORT
      LAYER M5 ;
        RECT  60.528 0 60.552 0.084 ;
    END
  END o[503]
  PIN o[504]
    DIRECTION OUTPUT ;
    USE SIGNAL ;
    PORT
      LAYER M5 ;
        RECT  60.624 0 60.648 0.084 ;
    END
  END o[504]
  PIN o[505]
    DIRECTION OUTPUT ;
    USE SIGNAL ;
    PORT
      LAYER M5 ;
        RECT  60.72 0 60.744 0.084 ;
    END
  END o[505]
  PIN o[506]
    DIRECTION OUTPUT ;
    USE SIGNAL ;
    PORT
      LAYER M5 ;
        RECT  60.816 0 60.84 0.084 ;
    END
  END o[506]
  PIN o[507]
    DIRECTION OUTPUT ;
    USE SIGNAL ;
    PORT
      LAYER M5 ;
        RECT  60.912 0 60.936 0.084 ;
    END
  END o[507]
  PIN o[508]
    DIRECTION OUTPUT ;
    USE SIGNAL ;
    PORT
      LAYER M5 ;
        RECT  61.008 0 61.032 0.084 ;
    END
  END o[508]
  PIN o[509]
    DIRECTION OUTPUT ;
    USE SIGNAL ;
    PORT
      LAYER M5 ;
        RECT  61.104 0 61.128 0.084 ;
    END
  END o[509]
  PIN o[50]
    DIRECTION OUTPUT ;
    USE SIGNAL ;
    PORT
      LAYER M5 ;
        RECT  24.72 0 24.744 0.084 ;
    END
  END o[50]
  PIN o[510]
    DIRECTION OUTPUT ;
    USE SIGNAL ;
    PORT
      LAYER M5 ;
        RECT  61.2 0 61.224 0.084 ;
    END
  END o[510]
  PIN o[511]
    DIRECTION OUTPUT ;
    USE SIGNAL ;
    PORT
      LAYER M5 ;
        RECT  61.296 0 61.32 0.084 ;
    END
  END o[511]
  PIN o[512]
    DIRECTION OUTPUT ;
    USE SIGNAL ;
    PORT
      LAYER M5 ;
        RECT  3.792 0 3.816 0.084 ;
    END
  END o[512]
  PIN o[513]
    DIRECTION OUTPUT ;
    USE SIGNAL ;
    PORT
      LAYER M5 ;
        RECT  3.888 0 3.912 0.084 ;
    END
  END o[513]
  PIN o[514]
    DIRECTION OUTPUT ;
    USE SIGNAL ;
    PORT
      LAYER M5 ;
        RECT  3.984 0 4.008 0.084 ;
    END
  END o[514]
  PIN o[515]
    DIRECTION OUTPUT ;
    USE SIGNAL ;
    PORT
      LAYER M5 ;
        RECT  4.08 0 4.104 0.084 ;
    END
  END o[515]
  PIN o[516]
    DIRECTION OUTPUT ;
    USE SIGNAL ;
    PORT
      LAYER M5 ;
        RECT  4.176 0 4.2 0.084 ;
    END
  END o[516]
  PIN o[517]
    DIRECTION OUTPUT ;
    USE SIGNAL ;
    PORT
      LAYER M5 ;
        RECT  4.272 0 4.296 0.084 ;
    END
  END o[517]
  PIN o[518]
    DIRECTION OUTPUT ;
    USE SIGNAL ;
    PORT
      LAYER M5 ;
        RECT  4.368 0 4.392 0.084 ;
    END
  END o[518]
  PIN o[519]
    DIRECTION OUTPUT ;
    USE SIGNAL ;
    PORT
      LAYER M5 ;
        RECT  4.464 0 4.488 0.084 ;
    END
  END o[519]
  PIN o[51]
    DIRECTION OUTPUT ;
    USE SIGNAL ;
    PORT
      LAYER M5 ;
        RECT  24.816 0 24.84 0.084 ;
    END
  END o[51]
  PIN o[520]
    DIRECTION OUTPUT ;
    USE SIGNAL ;
    PORT
      LAYER M5 ;
        RECT  4.56 0 4.584 0.084 ;
    END
  END o[520]
  PIN o[521]
    DIRECTION OUTPUT ;
    USE SIGNAL ;
    PORT
      LAYER M5 ;
        RECT  4.656 0 4.68 0.084 ;
    END
  END o[521]
  PIN o[522]
    DIRECTION OUTPUT ;
    USE SIGNAL ;
    PORT
      LAYER M5 ;
        RECT  4.752 0 4.776 0.084 ;
    END
  END o[522]
  PIN o[523]
    DIRECTION OUTPUT ;
    USE SIGNAL ;
    PORT
      LAYER M5 ;
        RECT  4.848 0 4.872 0.084 ;
    END
  END o[523]
  PIN o[524]
    DIRECTION OUTPUT ;
    USE SIGNAL ;
    PORT
      LAYER M5 ;
        RECT  4.944 0 4.968 0.084 ;
    END
  END o[524]
  PIN o[525]
    DIRECTION OUTPUT ;
    USE SIGNAL ;
    PORT
      LAYER M5 ;
        RECT  5.04 0 5.064 0.084 ;
    END
  END o[525]
  PIN o[526]
    DIRECTION OUTPUT ;
    USE SIGNAL ;
    PORT
      LAYER M5 ;
        RECT  5.136 0 5.16 0.084 ;
    END
  END o[526]
  PIN o[527]
    DIRECTION OUTPUT ;
    USE SIGNAL ;
    PORT
      LAYER M5 ;
        RECT  5.232 0 5.256 0.084 ;
    END
  END o[527]
  PIN o[528]
    DIRECTION OUTPUT ;
    USE SIGNAL ;
    PORT
      LAYER M5 ;
        RECT  5.328 0 5.352 0.084 ;
    END
  END o[528]
  PIN o[529]
    DIRECTION OUTPUT ;
    USE SIGNAL ;
    PORT
      LAYER M5 ;
        RECT  5.424 0 5.448 0.084 ;
    END
  END o[529]
  PIN o[52]
    DIRECTION OUTPUT ;
    USE SIGNAL ;
    PORT
      LAYER M5 ;
        RECT  24.912 0 24.936 0.084 ;
    END
  END o[52]
  PIN o[530]
    DIRECTION OUTPUT ;
    USE SIGNAL ;
    PORT
      LAYER M5 ;
        RECT  5.52 0 5.544 0.084 ;
    END
  END o[530]
  PIN o[531]
    DIRECTION OUTPUT ;
    USE SIGNAL ;
    PORT
      LAYER M5 ;
        RECT  5.616 0 5.64 0.084 ;
    END
  END o[531]
  PIN o[532]
    DIRECTION OUTPUT ;
    USE SIGNAL ;
    PORT
      LAYER M5 ;
        RECT  5.712 0 5.736 0.084 ;
    END
  END o[532]
  PIN o[533]
    DIRECTION OUTPUT ;
    USE SIGNAL ;
    PORT
      LAYER M5 ;
        RECT  5.808 0 5.832 0.084 ;
    END
  END o[533]
  PIN o[534]
    DIRECTION OUTPUT ;
    USE SIGNAL ;
    PORT
      LAYER M5 ;
        RECT  5.904 0 5.928 0.084 ;
    END
  END o[534]
  PIN o[535]
    DIRECTION OUTPUT ;
    USE SIGNAL ;
    PORT
      LAYER M5 ;
        RECT  6 0 6.024 0.084 ;
    END
  END o[535]
  PIN o[536]
    DIRECTION OUTPUT ;
    USE SIGNAL ;
    PORT
      LAYER M5 ;
        RECT  6.096 0 6.12 0.084 ;
    END
  END o[536]
  PIN o[537]
    DIRECTION OUTPUT ;
    USE SIGNAL ;
    PORT
      LAYER M5 ;
        RECT  6.192 0 6.216 0.084 ;
    END
  END o[537]
  PIN o[538]
    DIRECTION OUTPUT ;
    USE SIGNAL ;
    PORT
      LAYER M5 ;
        RECT  6.288 0 6.312 0.084 ;
    END
  END o[538]
  PIN o[539]
    DIRECTION OUTPUT ;
    USE SIGNAL ;
    PORT
      LAYER M5 ;
        RECT  6.384 0 6.408 0.084 ;
    END
  END o[539]
  PIN o[53]
    DIRECTION OUTPUT ;
    USE SIGNAL ;
    PORT
      LAYER M5 ;
        RECT  25.008 0 25.032 0.084 ;
    END
  END o[53]
  PIN o[540]
    DIRECTION OUTPUT ;
    USE SIGNAL ;
    PORT
      LAYER M5 ;
        RECT  6.48 0 6.504 0.084 ;
    END
  END o[540]
  PIN o[541]
    DIRECTION OUTPUT ;
    USE SIGNAL ;
    PORT
      LAYER M5 ;
        RECT  6.576 0 6.6 0.084 ;
    END
  END o[541]
  PIN o[542]
    DIRECTION OUTPUT ;
    USE SIGNAL ;
    PORT
      LAYER M5 ;
        RECT  6.672 0 6.696 0.084 ;
    END
  END o[542]
  PIN o[543]
    DIRECTION OUTPUT ;
    USE SIGNAL ;
    PORT
      LAYER M5 ;
        RECT  6.768 0 6.792 0.084 ;
    END
  END o[543]
  PIN o[544]
    DIRECTION OUTPUT ;
    USE SIGNAL ;
    PORT
      LAYER M5 ;
        RECT  16.08 0 16.104 0.084 ;
    END
  END o[544]
  PIN o[545]
    DIRECTION OUTPUT ;
    USE SIGNAL ;
    PORT
      LAYER M5 ;
        RECT  16.176 0 16.2 0.084 ;
    END
  END o[545]
  PIN o[546]
    DIRECTION OUTPUT ;
    USE SIGNAL ;
    PORT
      LAYER M5 ;
        RECT  16.272 0 16.296 0.084 ;
    END
  END o[546]
  PIN o[547]
    DIRECTION OUTPUT ;
    USE SIGNAL ;
    PORT
      LAYER M5 ;
        RECT  16.368 0 16.392 0.084 ;
    END
  END o[547]
  PIN o[548]
    DIRECTION OUTPUT ;
    USE SIGNAL ;
    PORT
      LAYER M5 ;
        RECT  16.464 0 16.488 0.084 ;
    END
  END o[548]
  PIN o[549]
    DIRECTION OUTPUT ;
    USE SIGNAL ;
    PORT
      LAYER M5 ;
        RECT  16.56 0 16.584 0.084 ;
    END
  END o[549]
  PIN o[54]
    DIRECTION OUTPUT ;
    USE SIGNAL ;
    PORT
      LAYER M5 ;
        RECT  25.104 0 25.128 0.084 ;
    END
  END o[54]
  PIN o[550]
    DIRECTION OUTPUT ;
    USE SIGNAL ;
    PORT
      LAYER M5 ;
        RECT  16.656 0 16.68 0.084 ;
    END
  END o[550]
  PIN o[551]
    DIRECTION OUTPUT ;
    USE SIGNAL ;
    PORT
      LAYER M5 ;
        RECT  16.752 0 16.776 0.084 ;
    END
  END o[551]
  PIN o[552]
    DIRECTION OUTPUT ;
    USE SIGNAL ;
    PORT
      LAYER M5 ;
        RECT  16.848 0 16.872 0.084 ;
    END
  END o[552]
  PIN o[553]
    DIRECTION OUTPUT ;
    USE SIGNAL ;
    PORT
      LAYER M5 ;
        RECT  16.944 0 16.968 0.084 ;
    END
  END o[553]
  PIN o[554]
    DIRECTION OUTPUT ;
    USE SIGNAL ;
    PORT
      LAYER M5 ;
        RECT  17.04 0 17.064 0.084 ;
    END
  END o[554]
  PIN o[555]
    DIRECTION OUTPUT ;
    USE SIGNAL ;
    PORT
      LAYER M5 ;
        RECT  17.136 0 17.16 0.084 ;
    END
  END o[555]
  PIN o[556]
    DIRECTION OUTPUT ;
    USE SIGNAL ;
    PORT
      LAYER M5 ;
        RECT  17.232 0 17.256 0.084 ;
    END
  END o[556]
  PIN o[557]
    DIRECTION OUTPUT ;
    USE SIGNAL ;
    PORT
      LAYER M5 ;
        RECT  17.328 0 17.352 0.084 ;
    END
  END o[557]
  PIN o[558]
    DIRECTION OUTPUT ;
    USE SIGNAL ;
    PORT
      LAYER M5 ;
        RECT  17.424 0 17.448 0.084 ;
    END
  END o[558]
  PIN o[559]
    DIRECTION OUTPUT ;
    USE SIGNAL ;
    PORT
      LAYER M5 ;
        RECT  17.52 0 17.544 0.084 ;
    END
  END o[559]
  PIN o[55]
    DIRECTION OUTPUT ;
    USE SIGNAL ;
    PORT
      LAYER M5 ;
        RECT  25.2 0 25.224 0.084 ;
    END
  END o[55]
  PIN o[560]
    DIRECTION OUTPUT ;
    USE SIGNAL ;
    PORT
      LAYER M5 ;
        RECT  17.616 0 17.64 0.084 ;
    END
  END o[560]
  PIN o[561]
    DIRECTION OUTPUT ;
    USE SIGNAL ;
    PORT
      LAYER M5 ;
        RECT  17.712 0 17.736 0.084 ;
    END
  END o[561]
  PIN o[562]
    DIRECTION OUTPUT ;
    USE SIGNAL ;
    PORT
      LAYER M5 ;
        RECT  17.808 0 17.832 0.084 ;
    END
  END o[562]
  PIN o[563]
    DIRECTION OUTPUT ;
    USE SIGNAL ;
    PORT
      LAYER M5 ;
        RECT  17.904 0 17.928 0.084 ;
    END
  END o[563]
  PIN o[564]
    DIRECTION OUTPUT ;
    USE SIGNAL ;
    PORT
      LAYER M5 ;
        RECT  18 0 18.024 0.084 ;
    END
  END o[564]
  PIN o[565]
    DIRECTION OUTPUT ;
    USE SIGNAL ;
    PORT
      LAYER M5 ;
        RECT  18.096 0 18.12 0.084 ;
    END
  END o[565]
  PIN o[566]
    DIRECTION OUTPUT ;
    USE SIGNAL ;
    PORT
      LAYER M5 ;
        RECT  18.192 0 18.216 0.084 ;
    END
  END o[566]
  PIN o[567]
    DIRECTION OUTPUT ;
    USE SIGNAL ;
    PORT
      LAYER M5 ;
        RECT  18.288 0 18.312 0.084 ;
    END
  END o[567]
  PIN o[568]
    DIRECTION OUTPUT ;
    USE SIGNAL ;
    PORT
      LAYER M5 ;
        RECT  18.384 0 18.408 0.084 ;
    END
  END o[568]
  PIN o[569]
    DIRECTION OUTPUT ;
    USE SIGNAL ;
    PORT
      LAYER M5 ;
        RECT  18.48 0 18.504 0.084 ;
    END
  END o[569]
  PIN o[56]
    DIRECTION OUTPUT ;
    USE SIGNAL ;
    PORT
      LAYER M5 ;
        RECT  25.296 0 25.32 0.084 ;
    END
  END o[56]
  PIN o[570]
    DIRECTION OUTPUT ;
    USE SIGNAL ;
    PORT
      LAYER M5 ;
        RECT  18.576 0 18.6 0.084 ;
    END
  END o[570]
  PIN o[571]
    DIRECTION OUTPUT ;
    USE SIGNAL ;
    PORT
      LAYER M5 ;
        RECT  18.672 0 18.696 0.084 ;
    END
  END o[571]
  PIN o[572]
    DIRECTION OUTPUT ;
    USE SIGNAL ;
    PORT
      LAYER M5 ;
        RECT  18.768 0 18.792 0.084 ;
    END
  END o[572]
  PIN o[573]
    DIRECTION OUTPUT ;
    USE SIGNAL ;
    PORT
      LAYER M5 ;
        RECT  18.864 0 18.888 0.084 ;
    END
  END o[573]
  PIN o[574]
    DIRECTION OUTPUT ;
    USE SIGNAL ;
    PORT
      LAYER M5 ;
        RECT  18.96 0 18.984 0.084 ;
    END
  END o[574]
  PIN o[575]
    DIRECTION OUTPUT ;
    USE SIGNAL ;
    PORT
      LAYER M5 ;
        RECT  19.056 0 19.08 0.084 ;
    END
  END o[575]
  PIN o[576]
    DIRECTION OUTPUT ;
    USE SIGNAL ;
    PORT
      LAYER M5 ;
        RECT  0.72 0 0.744 0.084 ;
    END
  END o[576]
  PIN o[577]
    DIRECTION OUTPUT ;
    USE SIGNAL ;
    PORT
      LAYER M5 ;
        RECT  0.816 0 0.84 0.084 ;
    END
  END o[577]
  PIN o[578]
    DIRECTION OUTPUT ;
    USE SIGNAL ;
    PORT
      LAYER M5 ;
        RECT  0.912 0 0.936 0.084 ;
    END
  END o[578]
  PIN o[579]
    DIRECTION OUTPUT ;
    USE SIGNAL ;
    PORT
      LAYER M5 ;
        RECT  1.008 0 1.032 0.084 ;
    END
  END o[579]
  PIN o[57]
    DIRECTION OUTPUT ;
    USE SIGNAL ;
    PORT
      LAYER M5 ;
        RECT  25.392 0 25.416 0.084 ;
    END
  END o[57]
  PIN o[580]
    DIRECTION OUTPUT ;
    USE SIGNAL ;
    PORT
      LAYER M5 ;
        RECT  1.104 0 1.128 0.084 ;
    END
  END o[580]
  PIN o[581]
    DIRECTION OUTPUT ;
    USE SIGNAL ;
    PORT
      LAYER M5 ;
        RECT  1.2 0 1.224 0.084 ;
    END
  END o[581]
  PIN o[582]
    DIRECTION OUTPUT ;
    USE SIGNAL ;
    PORT
      LAYER M5 ;
        RECT  1.296 0 1.32 0.084 ;
    END
  END o[582]
  PIN o[583]
    DIRECTION OUTPUT ;
    USE SIGNAL ;
    PORT
      LAYER M5 ;
        RECT  1.392 0 1.416 0.084 ;
    END
  END o[583]
  PIN o[584]
    DIRECTION OUTPUT ;
    USE SIGNAL ;
    PORT
      LAYER M5 ;
        RECT  1.488 0 1.512 0.084 ;
    END
  END o[584]
  PIN o[585]
    DIRECTION OUTPUT ;
    USE SIGNAL ;
    PORT
      LAYER M5 ;
        RECT  1.584 0 1.608 0.084 ;
    END
  END o[585]
  PIN o[586]
    DIRECTION OUTPUT ;
    USE SIGNAL ;
    PORT
      LAYER M5 ;
        RECT  1.68 0 1.704 0.084 ;
    END
  END o[586]
  PIN o[587]
    DIRECTION OUTPUT ;
    USE SIGNAL ;
    PORT
      LAYER M5 ;
        RECT  1.776 0 1.8 0.084 ;
    END
  END o[587]
  PIN o[588]
    DIRECTION OUTPUT ;
    USE SIGNAL ;
    PORT
      LAYER M5 ;
        RECT  1.872 0 1.896 0.084 ;
    END
  END o[588]
  PIN o[589]
    DIRECTION OUTPUT ;
    USE SIGNAL ;
    PORT
      LAYER M5 ;
        RECT  1.968 0 1.992 0.084 ;
    END
  END o[589]
  PIN o[58]
    DIRECTION OUTPUT ;
    USE SIGNAL ;
    PORT
      LAYER M5 ;
        RECT  25.488 0 25.512 0.084 ;
    END
  END o[58]
  PIN o[590]
    DIRECTION OUTPUT ;
    USE SIGNAL ;
    PORT
      LAYER M5 ;
        RECT  2.064 0 2.088 0.084 ;
    END
  END o[590]
  PIN o[591]
    DIRECTION OUTPUT ;
    USE SIGNAL ;
    PORT
      LAYER M5 ;
        RECT  2.16 0 2.184 0.084 ;
    END
  END o[591]
  PIN o[592]
    DIRECTION OUTPUT ;
    USE SIGNAL ;
    PORT
      LAYER M5 ;
        RECT  2.256 0 2.28 0.084 ;
    END
  END o[592]
  PIN o[593]
    DIRECTION OUTPUT ;
    USE SIGNAL ;
    PORT
      LAYER M5 ;
        RECT  2.352 0 2.376 0.084 ;
    END
  END o[593]
  PIN o[594]
    DIRECTION OUTPUT ;
    USE SIGNAL ;
    PORT
      LAYER M5 ;
        RECT  2.448 0 2.472 0.084 ;
    END
  END o[594]
  PIN o[595]
    DIRECTION OUTPUT ;
    USE SIGNAL ;
    PORT
      LAYER M5 ;
        RECT  2.544 0 2.568 0.084 ;
    END
  END o[595]
  PIN o[596]
    DIRECTION OUTPUT ;
    USE SIGNAL ;
    PORT
      LAYER M5 ;
        RECT  2.64 0 2.664 0.084 ;
    END
  END o[596]
  PIN o[597]
    DIRECTION OUTPUT ;
    USE SIGNAL ;
    PORT
      LAYER M5 ;
        RECT  2.736 0 2.76 0.084 ;
    END
  END o[597]
  PIN o[598]
    DIRECTION OUTPUT ;
    USE SIGNAL ;
    PORT
      LAYER M5 ;
        RECT  2.832 0 2.856 0.084 ;
    END
  END o[598]
  PIN o[599]
    DIRECTION OUTPUT ;
    USE SIGNAL ;
    PORT
      LAYER M5 ;
        RECT  2.928 0 2.952 0.084 ;
    END
  END o[599]
  PIN o[59]
    DIRECTION OUTPUT ;
    USE SIGNAL ;
    PORT
      LAYER M5 ;
        RECT  25.584 0 25.608 0.084 ;
    END
  END o[59]
  PIN o[5]
    DIRECTION OUTPUT ;
    USE SIGNAL ;
    PORT
      LAYER M5 ;
        RECT  20.4 0 20.424 0.084 ;
    END
  END o[5]
  PIN o[600]
    DIRECTION OUTPUT ;
    USE SIGNAL ;
    PORT
      LAYER M5 ;
        RECT  3.024 0 3.048 0.084 ;
    END
  END o[600]
  PIN o[601]
    DIRECTION OUTPUT ;
    USE SIGNAL ;
    PORT
      LAYER M5 ;
        RECT  3.12 0 3.144 0.084 ;
    END
  END o[601]
  PIN o[602]
    DIRECTION OUTPUT ;
    USE SIGNAL ;
    PORT
      LAYER M5 ;
        RECT  3.216 0 3.24 0.084 ;
    END
  END o[602]
  PIN o[603]
    DIRECTION OUTPUT ;
    USE SIGNAL ;
    PORT
      LAYER M5 ;
        RECT  3.312 0 3.336 0.084 ;
    END
  END o[603]
  PIN o[604]
    DIRECTION OUTPUT ;
    USE SIGNAL ;
    PORT
      LAYER M5 ;
        RECT  3.408 0 3.432 0.084 ;
    END
  END o[604]
  PIN o[605]
    DIRECTION OUTPUT ;
    USE SIGNAL ;
    PORT
      LAYER M5 ;
        RECT  3.504 0 3.528 0.084 ;
    END
  END o[605]
  PIN o[606]
    DIRECTION OUTPUT ;
    USE SIGNAL ;
    PORT
      LAYER M5 ;
        RECT  3.6 0 3.624 0.084 ;
    END
  END o[606]
  PIN o[607]
    DIRECTION OUTPUT ;
    USE SIGNAL ;
    PORT
      LAYER M5 ;
        RECT  3.696 0 3.72 0.084 ;
    END
  END o[607]
  PIN o[608]
    DIRECTION OUTPUT ;
    USE SIGNAL ;
    PORT
      LAYER M5 ;
        RECT  61.392 0 61.416 0.084 ;
    END
  END o[608]
  PIN o[609]
    DIRECTION OUTPUT ;
    USE SIGNAL ;
    PORT
      LAYER M5 ;
        RECT  61.488 0 61.512 0.084 ;
    END
  END o[609]
  PIN o[60]
    DIRECTION OUTPUT ;
    USE SIGNAL ;
    PORT
      LAYER M5 ;
        RECT  25.68 0 25.704 0.084 ;
    END
  END o[60]
  PIN o[610]
    DIRECTION OUTPUT ;
    USE SIGNAL ;
    PORT
      LAYER M5 ;
        RECT  61.584 0 61.608 0.084 ;
    END
  END o[610]
  PIN o[611]
    DIRECTION OUTPUT ;
    USE SIGNAL ;
    PORT
      LAYER M5 ;
        RECT  61.68 0 61.704 0.084 ;
    END
  END o[611]
  PIN o[612]
    DIRECTION OUTPUT ;
    USE SIGNAL ;
    PORT
      LAYER M5 ;
        RECT  61.776 0 61.8 0.084 ;
    END
  END o[612]
  PIN o[613]
    DIRECTION OUTPUT ;
    USE SIGNAL ;
    PORT
      LAYER M5 ;
        RECT  61.872 0 61.896 0.084 ;
    END
  END o[613]
  PIN o[614]
    DIRECTION OUTPUT ;
    USE SIGNAL ;
    PORT
      LAYER M5 ;
        RECT  61.968 0 61.992 0.084 ;
    END
  END o[614]
  PIN o[615]
    DIRECTION OUTPUT ;
    USE SIGNAL ;
    PORT
      LAYER M5 ;
        RECT  62.064 0 62.088 0.084 ;
    END
  END o[615]
  PIN o[616]
    DIRECTION OUTPUT ;
    USE SIGNAL ;
    PORT
      LAYER M5 ;
        RECT  62.16 0 62.184 0.084 ;
    END
  END o[616]
  PIN o[617]
    DIRECTION OUTPUT ;
    USE SIGNAL ;
    PORT
      LAYER M5 ;
        RECT  62.256 0 62.28 0.084 ;
    END
  END o[617]
  PIN o[618]
    DIRECTION OUTPUT ;
    USE SIGNAL ;
    PORT
      LAYER M5 ;
        RECT  62.352 0 62.376 0.084 ;
    END
  END o[618]
  PIN o[619]
    DIRECTION OUTPUT ;
    USE SIGNAL ;
    PORT
      LAYER M5 ;
        RECT  62.448 0 62.472 0.084 ;
    END
  END o[619]
  PIN o[61]
    DIRECTION OUTPUT ;
    USE SIGNAL ;
    PORT
      LAYER M5 ;
        RECT  25.776 0 25.8 0.084 ;
    END
  END o[61]
  PIN o[620]
    DIRECTION OUTPUT ;
    USE SIGNAL ;
    PORT
      LAYER M5 ;
        RECT  62.544 0 62.568 0.084 ;
    END
  END o[620]
  PIN o[621]
    DIRECTION OUTPUT ;
    USE SIGNAL ;
    PORT
      LAYER M5 ;
        RECT  62.64 0 62.664 0.084 ;
    END
  END o[621]
  PIN o[622]
    DIRECTION OUTPUT ;
    USE SIGNAL ;
    PORT
      LAYER M5 ;
        RECT  62.736 0 62.76 0.084 ;
    END
  END o[622]
  PIN o[623]
    DIRECTION OUTPUT ;
    USE SIGNAL ;
    PORT
      LAYER M5 ;
        RECT  62.832 0 62.856 0.084 ;
    END
  END o[623]
  PIN o[62]
    DIRECTION OUTPUT ;
    USE SIGNAL ;
    PORT
      LAYER M5 ;
        RECT  25.872 0 25.896 0.084 ;
    END
  END o[62]
  PIN o[63]
    DIRECTION OUTPUT ;
    USE SIGNAL ;
    PORT
      LAYER M5 ;
        RECT  25.968 0 25.992 0.084 ;
    END
  END o[63]
  PIN o[64]
    DIRECTION OUTPUT ;
    USE SIGNAL ;
    PORT
      LAYER M5 ;
        RECT  26.064 0 26.088 0.084 ;
    END
  END o[64]
  PIN o[65]
    DIRECTION OUTPUT ;
    USE SIGNAL ;
    PORT
      LAYER M5 ;
        RECT  26.16 0 26.184 0.084 ;
    END
  END o[65]
  PIN o[66]
    DIRECTION OUTPUT ;
    USE SIGNAL ;
    PORT
      LAYER M5 ;
        RECT  26.256 0 26.28 0.084 ;
    END
  END o[66]
  PIN o[67]
    DIRECTION OUTPUT ;
    USE SIGNAL ;
    PORT
      LAYER M5 ;
        RECT  26.352 0 26.376 0.084 ;
    END
  END o[67]
  PIN o[68]
    DIRECTION OUTPUT ;
    USE SIGNAL ;
    PORT
      LAYER M5 ;
        RECT  26.448 0 26.472 0.084 ;
    END
  END o[68]
  PIN o[69]
    DIRECTION OUTPUT ;
    USE SIGNAL ;
    PORT
      LAYER M5 ;
        RECT  26.544 0 26.568 0.084 ;
    END
  END o[69]
  PIN o[6]
    DIRECTION OUTPUT ;
    USE SIGNAL ;
    PORT
      LAYER M5 ;
        RECT  20.496 0 20.52 0.084 ;
    END
  END o[6]
  PIN o[70]
    DIRECTION OUTPUT ;
    USE SIGNAL ;
    PORT
      LAYER M5 ;
        RECT  26.64 0 26.664 0.084 ;
    END
  END o[70]
  PIN o[71]
    DIRECTION OUTPUT ;
    USE SIGNAL ;
    PORT
      LAYER M5 ;
        RECT  26.736 0 26.76 0.084 ;
    END
  END o[71]
  PIN o[72]
    DIRECTION OUTPUT ;
    USE SIGNAL ;
    PORT
      LAYER M5 ;
        RECT  26.832 0 26.856 0.084 ;
    END
  END o[72]
  PIN o[73]
    DIRECTION OUTPUT ;
    USE SIGNAL ;
    PORT
      LAYER M5 ;
        RECT  26.928 0 26.952 0.084 ;
    END
  END o[73]
  PIN o[74]
    DIRECTION OUTPUT ;
    USE SIGNAL ;
    PORT
      LAYER M5 ;
        RECT  27.024 0 27.048 0.084 ;
    END
  END o[74]
  PIN o[75]
    DIRECTION OUTPUT ;
    USE SIGNAL ;
    PORT
      LAYER M5 ;
        RECT  27.12 0 27.144 0.084 ;
    END
  END o[75]
  PIN o[76]
    DIRECTION OUTPUT ;
    USE SIGNAL ;
    PORT
      LAYER M5 ;
        RECT  27.216 0 27.24 0.084 ;
    END
  END o[76]
  PIN o[77]
    DIRECTION OUTPUT ;
    USE SIGNAL ;
    PORT
      LAYER M5 ;
        RECT  27.312 0 27.336 0.084 ;
    END
  END o[77]
  PIN o[78]
    DIRECTION OUTPUT ;
    USE SIGNAL ;
    PORT
      LAYER M5 ;
        RECT  27.408 0 27.432 0.084 ;
    END
  END o[78]
  PIN o[79]
    DIRECTION OUTPUT ;
    USE SIGNAL ;
    PORT
      LAYER M5 ;
        RECT  27.504 0 27.528 0.084 ;
    END
  END o[79]
  PIN o[7]
    DIRECTION OUTPUT ;
    USE SIGNAL ;
    PORT
      LAYER M5 ;
        RECT  20.592 0 20.616 0.084 ;
    END
  END o[7]
  PIN o[80]
    DIRECTION OUTPUT ;
    USE SIGNAL ;
    PORT
      LAYER M5 ;
        RECT  27.6 0 27.624 0.084 ;
    END
  END o[80]
  PIN o[81]
    DIRECTION OUTPUT ;
    USE SIGNAL ;
    PORT
      LAYER M5 ;
        RECT  27.696 0 27.72 0.084 ;
    END
  END o[81]
  PIN o[82]
    DIRECTION OUTPUT ;
    USE SIGNAL ;
    PORT
      LAYER M5 ;
        RECT  27.792 0 27.816 0.084 ;
    END
  END o[82]
  PIN o[83]
    DIRECTION OUTPUT ;
    USE SIGNAL ;
    PORT
      LAYER M5 ;
        RECT  27.888 0 27.912 0.084 ;
    END
  END o[83]
  PIN o[84]
    DIRECTION OUTPUT ;
    USE SIGNAL ;
    PORT
      LAYER M5 ;
        RECT  27.984 0 28.008 0.084 ;
    END
  END o[84]
  PIN o[85]
    DIRECTION OUTPUT ;
    USE SIGNAL ;
    PORT
      LAYER M5 ;
        RECT  28.08 0 28.104 0.084 ;
    END
  END o[85]
  PIN o[86]
    DIRECTION OUTPUT ;
    USE SIGNAL ;
    PORT
      LAYER M5 ;
        RECT  28.176 0 28.2 0.084 ;
    END
  END o[86]
  PIN o[87]
    DIRECTION OUTPUT ;
    USE SIGNAL ;
    PORT
      LAYER M5 ;
        RECT  28.272 0 28.296 0.084 ;
    END
  END o[87]
  PIN o[88]
    DIRECTION OUTPUT ;
    USE SIGNAL ;
    PORT
      LAYER M5 ;
        RECT  28.368 0 28.392 0.084 ;
    END
  END o[88]
  PIN o[89]
    DIRECTION OUTPUT ;
    USE SIGNAL ;
    PORT
      LAYER M5 ;
        RECT  28.464 0 28.488 0.084 ;
    END
  END o[89]
  PIN o[8]
    DIRECTION OUTPUT ;
    USE SIGNAL ;
    PORT
      LAYER M5 ;
        RECT  20.688 0 20.712 0.084 ;
    END
  END o[8]
  PIN o[90]
    DIRECTION OUTPUT ;
    USE SIGNAL ;
    PORT
      LAYER M5 ;
        RECT  28.56 0 28.584 0.084 ;
    END
  END o[90]
  PIN o[91]
    DIRECTION OUTPUT ;
    USE SIGNAL ;
    PORT
      LAYER M5 ;
        RECT  28.656 0 28.68 0.084 ;
    END
  END o[91]
  PIN o[92]
    DIRECTION OUTPUT ;
    USE SIGNAL ;
    PORT
      LAYER M5 ;
        RECT  28.752 0 28.776 0.084 ;
    END
  END o[92]
  PIN o[93]
    DIRECTION OUTPUT ;
    USE SIGNAL ;
    PORT
      LAYER M5 ;
        RECT  28.848 0 28.872 0.084 ;
    END
  END o[93]
  PIN o[94]
    DIRECTION OUTPUT ;
    USE SIGNAL ;
    PORT
      LAYER M5 ;
        RECT  28.944 0 28.968 0.084 ;
    END
  END o[94]
  PIN o[95]
    DIRECTION OUTPUT ;
    USE SIGNAL ;
    PORT
      LAYER M5 ;
        RECT  29.04 0 29.064 0.084 ;
    END
  END o[95]
  PIN o[96]
    DIRECTION OUTPUT ;
    USE SIGNAL ;
    PORT
      LAYER M5 ;
        RECT  35.28 0 35.304 0.084 ;
    END
  END o[96]
  PIN o[97]
    DIRECTION OUTPUT ;
    USE SIGNAL ;
    PORT
      LAYER M5 ;
        RECT  35.376 0 35.4 0.084 ;
    END
  END o[97]
  PIN o[98]
    DIRECTION OUTPUT ;
    USE SIGNAL ;
    PORT
      LAYER M5 ;
        RECT  35.472 0 35.496 0.084 ;
    END
  END o[98]
  PIN o[99]
    DIRECTION OUTPUT ;
    USE SIGNAL ;
    PORT
      LAYER M5 ;
        RECT  35.568 0 35.592 0.084 ;
    END
  END o[99]
  PIN o[9]
    DIRECTION OUTPUT ;
    USE SIGNAL ;
    PORT
      LAYER M5 ;
        RECT  20.784 0 20.808 0.084 ;
    END
  END o[9]
  PIN rs
    DIRECTION INPUT ;
    USE SIGNAL ;
    PORT
      LAYER M4 ;
        RECT  0 11.088 0.084 11.112 ;
    END
  END rs
  PIN VDD
    DIRECTION INOUT ;
    USE POWER ;
    PORT
      LAYER M5 ;
        RECT  61.992 2.151 62.112 21.609 ;
        RECT  59.292 2.151 59.412 21.609 ;
        RECT  56.592 2.151 56.712 21.609 ;
        RECT  53.892 2.151 54.012 21.609 ;
        RECT  51.192 2.151 51.312 21.609 ;
        RECT  48.492 2.151 48.612 21.609 ;
        RECT  45.792 2.151 45.912 21.609 ;
        RECT  43.092 2.151 43.212 21.609 ;
        RECT  40.392 2.151 40.512 21.609 ;
        RECT  37.692 2.151 37.812 21.609 ;
        RECT  34.992 2.151 35.112 21.609 ;
        RECT  32.292 2.151 32.412 21.609 ;
        RECT  29.592 2.151 29.712 21.609 ;
        RECT  26.892 2.151 27.012 21.609 ;
        RECT  24.192 2.151 24.312 21.609 ;
        RECT  21.492 2.151 21.612 21.609 ;
        RECT  18.792 2.151 18.912 21.609 ;
        RECT  16.092 2.151 16.212 21.609 ;
        RECT  13.392 2.151 13.512 21.609 ;
        RECT  10.692 2.151 10.812 21.609 ;
        RECT  7.992 2.151 8.112 21.609 ;
        RECT  5.292 2.151 5.412 21.609 ;
        RECT  2.592 2.151 2.712 21.609 ;
    END
  END VDD
  PIN VSS
    DIRECTION INOUT ;
    USE GROUND ;
    PORT
      LAYER M5 ;
        RECT  61.8 2.137 61.92 21.623 ;
        RECT  59.1 2.137 59.22 21.623 ;
        RECT  56.4 2.137 56.52 21.623 ;
        RECT  53.7 2.137 53.82 21.623 ;
        RECT  51 2.137 51.12 21.623 ;
        RECT  48.3 2.137 48.42 21.623 ;
        RECT  45.6 2.137 45.72 21.623 ;
        RECT  42.9 2.137 43.02 21.623 ;
        RECT  40.2 2.137 40.32 21.623 ;
        RECT  37.5 2.137 37.62 21.623 ;
        RECT  34.8 2.137 34.92 21.623 ;
        RECT  32.1 2.137 32.22 21.623 ;
        RECT  29.4 2.137 29.52 21.623 ;
        RECT  26.7 2.137 26.82 21.623 ;
        RECT  24 2.137 24.12 21.623 ;
        RECT  21.3 2.137 21.42 21.623 ;
        RECT  18.6 2.137 18.72 21.623 ;
        RECT  15.9 2.137 16.02 21.623 ;
        RECT  13.2 2.137 13.32 21.623 ;
        RECT  10.5 2.137 10.62 21.623 ;
        RECT  7.8 2.137 7.92 21.623 ;
        RECT  5.1 2.137 5.22 21.623 ;
        RECT  2.4 2.137 2.52 21.623 ;
    END
  END VSS
  OBS
    LAYER RVTN ;
     RECT  2.16 2.16 62.64 2.295 ;
     RECT  2.16 2.565 62.64 2.835 ;
     RECT  2.16 3.105 62.64 3.375 ;
     RECT  2.16 3.645 62.64 3.915 ;
     RECT  2.16 4.185 62.64 4.455 ;
     RECT  2.16 4.725 62.64 4.995 ;
     RECT  2.16 5.265 62.64 5.535 ;
     RECT  2.16 5.805 62.64 6.075 ;
     RECT  2.16 6.345 62.64 6.615 ;
     RECT  2.16 6.885 62.64 7.155 ;
     RECT  2.16 7.425 62.64 7.695 ;
     RECT  2.16 7.965 62.64 8.235 ;
     RECT  2.16 8.505 62.64 8.775 ;
     RECT  2.16 9.045 62.64 9.315 ;
     RECT  2.16 9.585 62.64 9.855 ;
     RECT  2.16 10.125 62.64 10.395 ;
     RECT  2.16 10.665 62.64 10.935 ;
     RECT  2.16 11.205 62.64 11.475 ;
     RECT  2.16 11.745 62.64 12.015 ;
     RECT  2.16 12.285 62.64 12.555 ;
     RECT  2.16 12.825 62.64 13.095 ;
     RECT  2.16 13.365 62.64 13.635 ;
     RECT  2.16 13.905 62.64 14.175 ;
     RECT  2.16 14.445 62.64 14.715 ;
     RECT  2.16 14.985 62.64 15.255 ;
     RECT  2.16 15.525 62.64 15.795 ;
     RECT  2.16 16.065 62.64 16.335 ;
     RECT  2.16 16.605 62.64 16.875 ;
     RECT  2.16 17.145 62.64 17.415 ;
     RECT  2.16 17.685 62.64 17.955 ;
     RECT  2.16 18.225 62.64 18.495 ;
     RECT  2.16 18.765 62.64 19.035 ;
     RECT  2.16 19.305 62.64 19.575 ;
     RECT  2.16 19.845 62.64 20.115 ;
     RECT  2.16 20.385 62.64 20.655 ;
     RECT  2.16 20.925 62.64 21.195 ;
     RECT  2.16 21.465 62.64 21.6 ;
    LAYER RVTP ;
     RECT  2.16 2.295 62.64 2.565 ;
     RECT  2.16 2.835 62.64 3.105 ;
     RECT  2.16 3.375 62.64 3.645 ;
     RECT  2.16 3.915 62.64 4.185 ;
     RECT  2.16 4.455 62.64 4.725 ;
     RECT  2.16 4.995 62.64 5.265 ;
     RECT  2.16 5.535 62.64 5.805 ;
     RECT  2.16 6.075 62.64 6.345 ;
     RECT  2.16 6.615 62.64 6.885 ;
     RECT  2.16 7.155 62.64 7.425 ;
     RECT  2.16 7.695 62.64 7.965 ;
     RECT  2.16 8.235 62.64 8.505 ;
     RECT  2.16 8.775 62.64 9.045 ;
     RECT  2.16 9.315 62.64 9.585 ;
     RECT  2.16 9.855 62.64 10.125 ;
     RECT  2.16 10.395 62.64 10.665 ;
     RECT  2.16 10.935 62.64 11.205 ;
     RECT  2.16 11.475 62.64 11.745 ;
     RECT  2.16 12.015 62.64 12.285 ;
     RECT  2.16 12.555 62.64 12.825 ;
     RECT  2.16 13.095 62.64 13.365 ;
     RECT  2.16 13.635 62.64 13.905 ;
     RECT  2.16 14.175 62.64 14.445 ;
     RECT  2.16 14.715 62.64 14.985 ;
     RECT  2.16 15.255 62.64 15.525 ;
     RECT  2.16 15.795 62.64 16.065 ;
     RECT  2.16 16.335 62.64 16.605 ;
     RECT  2.16 16.875 62.64 17.145 ;
     RECT  2.16 17.415 62.64 17.685 ;
     RECT  2.16 17.955 62.64 18.225 ;
     RECT  2.16 18.495 62.64 18.765 ;
     RECT  2.16 19.035 62.64 19.305 ;
     RECT  2.16 19.575 62.64 19.845 ;
     RECT  2.16 20.115 62.64 20.385 ;
     RECT  2.16 20.655 62.64 20.925 ;
     RECT  2.16 21.195 62.64 21.465 ;
    LAYER M1 ;
     RECT  2.16 2.151 62.64 21.609 ;
    LAYER M2 ;
     RECT  1.651 3.456 1.723 3.474 ;
     RECT  1.723 3.456 1.831 4.104 ;
     RECT  1.687 2.376 1.867 2.394 ;
     RECT  1.831 3.186 1.867 4.104 ;
     RECT  1.831 10.944 1.939 10.962 ;
     RECT  1.867 11.826 1.939 11.844 ;
     RECT  1.867 2.376 1.975 4.104 ;
     RECT  1.687 5.976 2.083 5.994 ;
     RECT  1.651 6.822 2.083 6.84 ;
     RECT  1.975 2.376 2.16 4.176 ;
     RECT  2.083 4.932 2.16 4.95 ;
     RECT  2.083 5.886 2.16 6.84 ;
     RECT  2.011 9.666 2.16 9.684 ;
     RECT  1.939 10.944 2.16 11.844 ;
     RECT  1.903 12.906 2.16 12.924 ;
     RECT  2.16 2.151 3.271 21.609 ;
     RECT  3.271 2.106 4.127 21.609 ;
     RECT  4.127 2.151 5.719 21.609 ;
     RECT  5.719 2.106 6.251 21.609 ;
     RECT  6.367 1.152 7.151 1.17 ;
     RECT  6.251 2.151 7.159 21.609 ;
     RECT  7.159 2.151 7.627 21.654 ;
     RECT  7.627 2.106 7.979 21.654 ;
     RECT  7.979 2.151 8.887 21.654 ;
     RECT  8.887 2.106 9.275 21.726 ;
     RECT  9.275 2.151 10.255 21.726 ;
     RECT  10.255 2.106 10.363 21.726 ;
     RECT  10.363 2.106 11.155 22.266 ;
     RECT  11.155 2.034 11.623 22.266 ;
     RECT  11.623 1.998 12.083 22.266 ;
     RECT  12.083 2.034 13.739 22.266 ;
     RECT  13.711 1.152 14.675 1.17 ;
     RECT  13.739 2.106 14.855 22.266 ;
     RECT  14.855 2.151 16.051 22.266 ;
     RECT  16.051 1.962 16.727 22.266 ;
     RECT  16.727 2.034 17.087 22.266 ;
     RECT  17.087 2.106 17.123 22.266 ;
     RECT  17.123 2.151 18.535 22.266 ;
     RECT  18.535 2.106 20.219 22.266 ;
     RECT  22.099 1.152 22.739 1.17 ;
     RECT  20.219 2.151 22.927 22.266 ;
     RECT  22.927 2.106 23.783 22.266 ;
     RECT  23.783 2.151 24.619 22.266 ;
     RECT  24.619 2.106 25.339 22.266 ;
     RECT  25.267 1.152 25.403 1.242 ;
     RECT  25.403 1.152 25.511 1.17 ;
     RECT  25.339 2.07 25.987 22.266 ;
     RECT  25.987 2.034 26.887 22.266 ;
     RECT  27.427 1.152 27.635 1.17 ;
     RECT  26.887 1.962 27.995 22.266 ;
     RECT  27.995 1.998 30.803 22.266 ;
     RECT  30.803 2.106 32.071 22.266 ;
     RECT  32.071 2.034 32.395 22.266 ;
     RECT  32.395 1.962 33.691 22.266 ;
     RECT  33.691 1.926 34.195 22.266 ;
     RECT  34.195 1.881 34.591 22.266 ;
     RECT  34.591 1.836 35.699 22.266 ;
     RECT  35.699 1.998 36.095 22.266 ;
     RECT  36.095 2.034 36.311 22.266 ;
     RECT  36.311 2.106 36.815 22.266 ;
     RECT  36.815 2.151 37.651 22.266 ;
     RECT  37.651 2.034 39.119 22.266 ;
     RECT  39.119 2.106 39.335 22.266 ;
     RECT  39.335 2.151 42.115 22.266 ;
     RECT  42.367 1.152 42.467 1.17 ;
     RECT  44.527 1.152 44.671 1.17 ;
     RECT  44.671 1.152 44.807 1.206 ;
     RECT  42.115 2.106 44.887 22.266 ;
     RECT  44.807 1.152 44.951 1.17 ;
     RECT  44.887 2.07 45.815 22.266 ;
     RECT  45.815 2.106 46.211 22.266 ;
     RECT  46.219 1.152 46.319 1.17 ;
     RECT  46.211 2.151 47.083 22.266 ;
     RECT  47.083 2.106 48.559 22.266 ;
     RECT  48.559 2.07 49.055 22.266 ;
     RECT  49.055 2.106 49.667 22.266 ;
     RECT  49.927 1.152 49.991 1.17 ;
     RECT  49.667 2.151 51.187 22.266 ;
     RECT  51.187 1.962 51.691 22.266 ;
     RECT  51.691 1.881 53.051 22.266 ;
     RECT  53.051 2.034 53.851 22.266 ;
     RECT  54.355 1.152 54.563 1.17 ;
     RECT  53.851 1.962 57.011 22.266 ;
     RECT  57.955 1.152 58.091 1.17 ;
     RECT  57.011 2.034 58.775 22.266 ;
     RECT  58.775 2.034 59.251 21.69 ;
     RECT  59.251 1.926 59.467 21.69 ;
     RECT  59.467 1.881 60.215 21.69 ;
     RECT  60.215 1.881 61.411 21.609 ;
     RECT  61.411 1.152 61.547 21.609 ;
     RECT  61.547 1.881 62.64 21.609 ;
     RECT  62.64 4.698 62.663 5.904 ;
     RECT  62.64 6.66 62.699 8.496 ;
     RECT  62.663 4.698 62.735 5.292 ;
     RECT  62.735 4.698 62.771 4.716 ;
     RECT  62.64 1.881 62.807 2.898 ;
     RECT  62.699 8.478 62.807 8.496 ;
     RECT  62.64 9.396 62.879 11.934 ;
     RECT  62.64 16.956 62.879 19.368 ;
     RECT  62.807 1.881 62.915 2.826 ;
     RECT  62.64 21.051 62.915 21.069 ;
     RECT  62.879 9.396 62.951 9.882 ;
     RECT  62.879 16.956 62.987 19.026 ;
     RECT  62.951 9.864 63.023 9.882 ;
     RECT  62.987 17.226 63.059 19.026 ;
     RECT  62.879 10.98 63.095 11.934 ;
     RECT  62.699 6.66 63.131 7.344 ;
     RECT  62.64 3.816 63.311 3.834 ;
     RECT  63.131 6.66 63.311 6.678 ;
     RECT  63.059 18.306 63.311 19.026 ;
     RECT  62.64 12.726 63.347 13.554 ;
     RECT  63.311 18.306 63.347 18.594 ;
     RECT  62.915 2.034 63.383 2.826 ;
     RECT  63.347 12.726 63.383 13.014 ;
     RECT  63.059 17.226 63.383 17.244 ;
     RECT  63.095 11.376 63.419 11.934 ;
     RECT  63.383 2.034 63.455 2.484 ;
     RECT  63.419 11.916 63.455 11.934 ;
     RECT  63.455 2.034 63.491 2.052 ;
     RECT  63.383 12.726 63.491 12.744 ;
     RECT  63.347 18.306 63.887 18.324 ;
    LAYER M3 ;
     RECT  11.052 0.091 11.07 0.139 ;
     RECT  15.588 0.091 15.606 0.139 ;
     RECT  30.528 0.091 30.942 0.139 ;
     RECT  48.888 0.091 48.906 0.139 ;
     RECT  54.36 0.091 55.134 0.139 ;
     RECT  56.196 0.091 56.79 0.139 ;
     RECT  11.052 0.139 11.214 0.187 ;
     RECT  15.588 0.139 15.714 0.187 ;
     RECT  30.528 0.139 31.05 0.187 ;
     RECT  59.58 0.091 60.174 0.187 ;
     RECT  35.28 0.091 35.298 0.221 ;
     RECT  40.752 0.091 40.77 0.221 ;
     RECT  33.516 0.091 33.534 0.235 ;
     RECT  3.168 0.091 3.51 0.269 ;
     RECT  11.052 0.187 11.394 0.269 ;
     RECT  12.204 0.091 12.906 0.269 ;
     RECT  27.792 0.091 27.81 0.269 ;
     RECT  43.596 0.091 43.614 0.269 ;
     RECT  51.66 0.091 51.678 0.269 ;
     RECT  55.98 0.139 56.898 0.269 ;
     RECT  11.196 0.269 11.394 0.317 ;
     RECT  18.468 0.091 18.486 0.317 ;
     RECT  54.36 0.139 55.242 0.317 ;
     RECT  4.464 0.091 4.482 0.365 ;
     RECT  11.376 0.317 11.394 0.365 ;
     RECT  15.516 0.187 16.506 0.365 ;
     RECT  30.384 0.187 31.05 0.365 ;
     RECT  48.888 0.139 49.158 0.365 ;
     RECT  32.616 0.235 33.534 0.413 ;
     RECT  54.36 0.317 55.206 0.413 ;
     RECT  15.516 0.365 15.534 0.461 ;
     RECT  56.196 0.269 56.898 0.509 ;
     RECT  59.58 0.187 60.354 0.509 ;
     RECT  14.688 0.091 14.706 0.523 ;
     RECT  8.532 0.091 8.55 0.571 ;
     RECT  12.204 0.269 12.474 0.571 ;
     RECT  13.392 0.523 13.41 0.571 ;
     RECT  14.292 0.523 14.706 0.571 ;
     RECT  22.068 0.523 22.086 0.571 ;
     RECT  23.076 0.091 23.094 0.571 ;
     RECT  25.272 0.187 25.29 0.571 ;
     RECT  26.136 0.091 26.154 0.571 ;
     RECT  30.456 0.365 31.05 0.571 ;
     RECT  32.904 0.413 33.534 0.571 ;
     RECT  37.908 0.523 37.926 0.571 ;
     RECT  39.456 0.523 39.474 0.571 ;
     RECT  46.224 0.091 46.242 0.571 ;
     RECT  49.14 0.365 49.158 0.571 ;
     RECT  11.736 0.571 12.474 0.605 ;
     RECT  16.488 0.365 16.506 0.605 ;
     RECT  32.904 0.571 33.93 0.605 ;
     RECT  44.532 0.571 44.55 0.619 ;
     RECT  45.504 0.571 46.242 0.619 ;
     RECT  32.976 0.605 33.93 0.653 ;
     RECT  60.336 0.509 60.354 0.653 ;
     RECT  8.46 0.571 8.55 0.667 ;
     RECT  9.576 0.619 9.594 0.667 ;
     RECT  57.96 0.571 57.978 0.667 ;
     RECT  61.776 0.091 62.766 0.667 ;
     RECT  56.88 0.509 56.898 0.701 ;
     RECT  30.456 0.571 31.59 0.845 ;
     RECT  31.32 0.845 31.59 1.051 ;
     RECT  5.796 0.091 5.814 1.099 ;
     RECT  5.796 1.099 6.39 1.147 ;
     RECT  7.128 0.619 7.146 1.147 ;
     RECT  17.424 0.571 17.442 1.147 ;
     RECT  27.432 0.571 27.45 1.147 ;
     RECT  28.368 0.667 28.386 1.147 ;
     RECT  42.444 0.571 42.462 1.147 ;
     RECT  44.532 0.619 46.242 1.147 ;
     RECT  54.36 0.413 54.378 1.147 ;
     RECT  55.188 0.413 55.206 1.147 ;
     RECT  57.96 0.667 58.014 1.147 ;
     RECT  61.524 0.667 62.766 1.147 ;
     RECT  33.516 0.653 33.93 1.195 ;
     RECT  11.736 0.605 11.754 1.243 ;
     RECT  60.588 1.147 60.606 1.627 ;
     RECT  57.96 1.147 58.086 1.675 ;
     RECT  5.796 1.147 7.146 1.723 ;
     RECT  8.46 0.667 9.594 1.723 ;
     RECT  11.592 1.243 11.754 1.723 ;
     RECT  13.392 0.571 15.21 1.723 ;
     RECT  16.884 1.147 17.442 1.723 ;
     RECT  20.124 0.091 20.142 1.723 ;
     RECT  22.068 0.571 23.094 1.723 ;
     RECT  24.408 0.811 24.426 1.723 ;
     RECT  25.272 0.571 26.154 1.723 ;
     RECT  27.396 1.147 28.386 1.723 ;
     RECT  30.456 0.845 30.546 1.723 ;
     RECT  31.32 1.051 31.662 1.723 ;
     RECT  33.516 1.195 34.326 1.723 ;
     RECT  35.208 1.147 35.226 1.723 ;
     RECT  37.296 0.571 37.926 1.723 ;
     RECT  39.456 0.571 40.086 1.723 ;
     RECT  42.048 1.147 42.714 1.723 ;
     RECT  44.532 1.147 46.314 1.723 ;
     RECT  49.14 0.571 49.986 1.723 ;
     RECT  54.36 1.147 55.206 1.723 ;
     RECT  60.444 1.627 60.606 1.723 ;
     RECT  61.416 1.147 62.766 1.723 ;
     RECT  5.796 1.723 10.098 1.771 ;
     RECT  16.884 1.723 18.126 1.771 ;
     RECT  20.124 1.723 20.43 1.771 ;
     RECT  24.408 1.723 26.154 1.771 ;
     RECT  27.396 1.723 29.178 1.771 ;
     RECT  37.296 1.723 38.25 1.771 ;
     RECT  48.996 1.723 50.598 1.771 ;
     RECT  54.072 1.723 55.206 1.771 ;
     RECT  56.016 1.723 56.034 1.771 ;
     RECT  60.444 1.723 62.766 1.771 ;
     RECT  11.34 1.723 11.754 1.819 ;
     RECT  36.756 1.771 38.322 1.819 ;
     RECT  39.456 1.723 42.714 1.819 ;
     RECT  54.072 1.771 56.034 1.819 ;
     RECT  32.868 1.723 34.326 1.831 ;
     RECT  35.208 1.723 35.874 1.831 ;
     RECT  36.756 1.819 42.714 1.867 ;
     RECT  51.624 1.723 51.642 1.876 ;
     RECT  52.524 0.571 52.542 1.876 ;
     RECT  57.96 1.675 58.77 1.876 ;
     RECT  59.508 1.723 59.526 1.876 ;
     RECT  60.264 1.771 62.766 1.876 ;
     RECT  3.168 0.269 3.186 1.915 ;
     RECT  4.32 1.723 4.734 1.915 ;
     RECT  13.392 1.723 15.786 1.957 ;
     RECT  16.884 1.771 18.378 1.957 ;
     RECT  30.168 1.723 31.878 1.957 ;
     RECT  32.868 1.831 35.874 1.957 ;
     RECT  48.996 1.771 50.742 1.957 ;
     RECT  51.624 1.876 51.714 1.957 ;
     RECT  54.072 1.819 56.574 1.957 ;
     RECT  11.34 1.819 11.898 1.993 ;
     RECT  24.408 1.771 29.286 1.993 ;
     RECT  30.168 1.957 35.874 1.993 ;
     RECT  36.756 1.867 43.074 1.993 ;
     RECT  57.96 1.876 59.526 1.993 ;
     RECT  60.264 1.876 62.91 1.993 ;
     RECT  3.168 1.915 4.734 2.011 ;
     RECT  19.872 1.771 20.43 2.011 ;
     RECT  24.408 1.993 43.074 2.011 ;
     RECT  44.208 1.723 47.466 2.011 ;
     RECT  11.34 1.993 12.078 2.029 ;
     RECT  13.392 1.957 18.378 2.029 ;
     RECT  52.524 1.876 53.046 2.029 ;
     RECT  53.856 1.957 57.006 2.029 ;
     RECT  57.96 1.993 62.91 2.029 ;
     RECT  48.996 1.957 51.714 2.065 ;
     RECT  52.452 2.029 53.046 2.065 ;
     RECT  5.652 1.771 10.098 2.101 ;
     RECT  11.16 2.029 18.378 2.101 ;
     RECT  19.8 2.011 20.43 2.101 ;
     RECT  22.068 1.723 23.202 2.101 ;
     RECT  24.408 2.011 47.466 2.101 ;
     RECT  48.564 2.065 53.046 2.101 ;
     RECT  3.096 2.011 4.734 2.143 ;
     RECT  5.652 2.101 10.278 2.143 ;
     RECT  11.16 2.101 18.558 2.143 ;
     RECT  19.332 2.101 20.43 2.143 ;
     RECT  22.068 2.101 53.046 2.143 ;
     RECT  53.856 2.029 63.486 2.143 ;
     RECT  2.415 2.143 20.43 2.191 ;
     RECT  21.315 2.143 63.486 2.191 ;
     RECT  2.415 2.191 63.486 2.371 ;
     RECT  1.692 2.371 63.486 3.451 ;
     RECT  1.656 3.451 63.486 3.499 ;
     RECT  1.152 3.499 63.486 3.917 ;
     RECT  1.656 3.917 63.486 5.495 ;
     RECT  1.656 5.495 22.482 6.241 ;
     RECT  23.328 5.495 63.486 6.241 ;
     RECT  1.656 6.241 63.486 6.845 ;
     RECT  1.836 6.845 63.486 10.891 ;
     RECT  1.152 10.891 63.486 11.021 ;
     RECT  1.872 11.021 63.486 11.849 ;
     RECT  1.908 11.849 63.486 12.749 ;
     RECT  1.908 12.749 63.378 12.929 ;
     RECT  2.268 12.929 63.378 13.019 ;
     RECT  2.268 13.019 63.342 13.559 ;
     RECT  2.268 13.559 62.622 16.951 ;
     RECT  2.268 16.951 62.982 17.221 ;
     RECT  2.268 17.221 63.378 17.951 ;
     RECT  58.212 17.951 63.378 18.301 ;
     RECT  2.268 17.951 57.474 19.147 ;
     RECT  58.212 18.301 63.882 19.147 ;
     RECT  2.268 19.147 63.882 20.573 ;
     RECT  2.268 20.573 63.378 21.299 ;
     RECT  2.415 21.299 63.378 21.389 ;
     RECT  15.696 21.389 24.57 21.425 ;
     RECT  2.415 21.389 6.21 21.461 ;
     RECT  6.984 21.389 9.09 21.461 ;
     RECT  15.696 21.425 17.73 21.461 ;
     RECT  38.736 21.389 63.378 21.461 ;
     RECT  15.876 21.461 17.694 21.533 ;
     RECT  25.344 21.389 28.314 21.533 ;
     RECT  45.108 21.461 63.378 21.533 ;
     RECT  2.415 21.461 5.454 21.569 ;
     RECT  9.9 21.389 12.042 21.569 ;
     RECT  34.38 21.389 37.854 21.569 ;
     RECT  38.736 21.461 44.298 21.569 ;
     RECT  45.108 21.533 52.506 21.569 ;
     RECT  53.28 21.533 63.378 21.569 ;
     RECT  6.984 21.461 8.91 21.581 ;
     RECT  25.344 21.533 27.666 21.581 ;
     RECT  2.415 21.569 3.726 21.617 ;
     RECT  13.215 21.389 14.958 21.617 ;
     RECT  15.915 21.533 17.694 21.617 ;
     RECT  53.496 21.569 63.378 21.629 ;
     RECT  7.164 21.581 8.91 21.659 ;
     RECT  11.592 21.569 12.042 21.659 ;
     RECT  38.736 21.569 41.274 21.659 ;
     RECT  4.788 21.569 5.454 21.677 ;
     RECT  13.356 21.617 14.958 21.677 ;
     RECT  16.056 21.617 17.694 21.677 ;
     RECT  18.576 21.425 24.57 21.677 ;
     RECT  26.172 21.581 27.666 21.677 ;
     RECT  29.124 21.389 33.21 21.677 ;
     RECT  34.38 21.569 35.586 21.677 ;
     RECT  38.736 21.659 40.698 21.677 ;
     RECT  42.192 21.569 44.298 21.677 ;
     RECT  45.108 21.569 51.858 21.677 ;
     RECT  53.496 21.629 55.494 21.677 ;
     RECT  56.232 21.629 63.378 21.677 ;
     RECT  11.592 21.659 11.61 21.695 ;
     RECT  2.844 21.617 3.726 21.725 ;
     RECT  7.2 21.659 8.91 21.725 ;
     RECT  13.356 21.677 13.806 21.725 ;
     RECT  16.056 21.677 16.254 21.725 ;
     RECT  36.324 21.569 37.854 21.725 ;
     RECT  50.256 21.677 51.858 21.725 ;
     RECT  58.752 21.677 63.054 21.725 ;
     RECT  7.38 21.725 8.91 21.731 ;
     RECT  32.004 21.677 33.21 21.731 ;
     RECT  40.176 21.677 40.698 21.731 ;
     RECT  13.716 21.725 13.806 21.767 ;
     RECT  36.324 21.725 37.134 21.767 ;
     RECT  38.736 21.677 38.754 21.767 ;
     RECT  45.108 21.677 49.338 21.767 ;
     RECT  5.256 21.677 5.454 21.773 ;
     RECT  7.38 21.731 8.586 21.773 ;
     RECT  16.056 21.725 16.074 21.773 ;
     RECT  18.576 21.677 19.854 21.773 ;
     RECT  21.096 21.677 22.086 21.773 ;
     RECT  23.256 21.677 24.174 21.773 ;
     RECT  29.124 21.677 30.042 21.773 ;
     RECT  34.956 21.677 35.586 21.773 ;
     RECT  50.256 21.725 51.426 21.773 ;
     RECT  53.856 21.677 54.27 21.773 ;
     RECT  58.752 21.725 59.094 21.773 ;
     RECT  18.576 21.773 18.594 21.803 ;
     RECT  30.024 21.773 30.042 21.803 ;
     RECT  5.436 21.773 5.454 21.821 ;
     RECT  23.256 21.773 23.994 21.821 ;
     RECT  26.64 21.677 27.666 21.821 ;
     RECT  50.256 21.773 50.994 21.869 ;
     RECT  53.964 21.773 54.27 21.869 ;
     RECT  23.256 21.821 23.31 21.884 ;
     RECT  26.784 21.821 27.666 21.884 ;
     RECT  29.124 21.773 29.286 21.884 ;
     RECT  32.076 21.731 33.21 21.917 ;
     RECT  45.108 21.767 47.07 21.917 ;
     RECT  56.556 21.677 57.294 21.917 ;
     RECT  59.904 21.725 63.054 21.917 ;
     RECT  29.16 21.884 29.286 21.965 ;
     RECT  32.4 21.917 33.21 21.965 ;
     RECT  50.256 21.869 50.922 21.965 ;
     RECT  26.784 21.884 27.414 22.013 ;
     RECT  50.256 21.965 50.814 22.013 ;
     RECT  54.144 21.869 54.27 22.013 ;
     RECT  37.044 21.767 37.134 22.037 ;
     RECT  26.784 22.013 26.802 22.061 ;
     RECT  32.4 21.965 33.138 22.061 ;
     RECT  37.044 22.037 37.062 22.061 ;
     RECT  7.38 21.773 7.398 22.205 ;
     RECT  59.904 21.917 61.614 22.205 ;
     RECT  62.46 21.917 63.054 22.205 ;
     RECT  8.568 21.773 8.586 22.253 ;
     RECT  17.1 21.677 17.694 22.253 ;
     RECT  19.512 21.773 19.854 22.253 ;
     RECT  23.292 21.884 23.31 22.253 ;
     RECT  25.344 21.581 25.362 22.253 ;
     RECT  47.88 21.767 49.338 22.253 ;
     RECT  59.904 22.205 60.462 22.253 ;
     RECT  62.46 22.205 62.802 22.253 ;
     RECT  42.768 21.677 44.298 22.267 ;
     RECT  45.108 21.917 45.414 22.267 ;
     RECT  10.368 21.569 10.854 22.271 ;
     RECT  58.752 21.773 58.77 22.271 ;
     RECT  42.768 22.267 45.414 22.301 ;
     RECT  48.456 22.253 49.338 22.301 ;
     RECT  59.904 22.253 59.994 22.301 ;
     RECT  17.1 22.253 17.226 22.349 ;
     RECT  19.656 22.253 19.854 22.349 ;
     RECT  21.096 21.773 21.222 22.349 ;
     RECT  46.836 21.917 47.07 22.349 ;
     RECT  42.768 22.301 43.722 22.397 ;
     RECT  44.712 22.301 45.414 22.397 ;
     RECT  46.836 22.349 46.998 22.397 ;
     RECT  48.924 22.301 49.338 22.397 ;
     RECT  61.272 22.205 61.614 22.397 ;
     RECT  19.764 22.349 19.854 22.411 ;
     RECT  17.1 22.349 17.118 22.445 ;
     RECT  19.764 22.411 19.89 22.445 ;
     RECT  56.7 21.917 57.294 22.445 ;
     RECT  61.272 22.397 61.434 22.445 ;
     RECT  21.096 22.349 21.114 22.493 ;
     RECT  42.768 22.397 42.786 22.493 ;
     RECT  49.032 22.397 49.338 22.493 ;
     RECT  19.872 22.445 19.89 22.541 ;
     RECT  44.82 22.397 45.414 22.541 ;
     RECT  46.836 22.397 46.854 22.541 ;
     RECT  49.032 22.493 49.05 22.541 ;
     RECT  45.396 22.541 45.414 22.781 ;
     RECT  59.904 22.301 59.922 22.781 ;
     RECT  3.06 21.725 3.726 22.829 ;
     RECT  50.256 22.013 50.274 22.829 ;
     RECT  61.416 22.445 61.434 22.829 ;
     RECT  62.46 22.253 62.478 22.829 ;
     RECT  3.06 22.829 3.294 22.877 ;
     RECT  22.068 21.773 22.086 23.131 ;
     RECT  32.508 22.061 32.67 23.131 ;
     RECT  21.78 23.131 22.086 23.309 ;
     RECT  31.932 23.131 32.67 23.309 ;
     RECT  29.808 23.323 29.826 23.371 ;
     RECT  9.468 23.371 9.486 23.419 ;
     RECT  6.192 21.461 6.21 23.467 ;
     RECT  38.052 23.419 38.07 23.467 ;
     RECT  43.704 22.397 43.722 23.501 ;
     RECT  3.06 22.877 3.078 23.515 ;
     RECT  22.068 23.309 22.086 23.515 ;
     RECT  29.808 23.371 30.042 23.515 ;
     RECT  54.144 22.013 54.162 23.515 ;
     RECT  19.08 23.371 19.098 23.549 ;
     RECT  29.808 23.515 30.15 23.549 ;
     RECT  35.316 21.773 35.586 23.549 ;
     RECT  5.724 23.467 6.21 23.597 ;
     RECT  2.376 23.515 3.078 23.645 ;
     RECT  6.192 23.597 6.21 23.645 ;
     RECT  9.468 23.419 9.666 23.645 ;
     RECT  10.836 22.271 10.854 23.645 ;
     RECT  13.716 21.767 13.734 23.645 ;
     RECT  18.18 23.419 18.198 23.645 ;
     RECT  22.068 23.515 22.23 23.645 ;
     RECT  24.804 23.419 24.822 23.645 ;
     RECT  29.88 23.549 30.15 23.645 ;
     RECT  32.652 23.309 32.67 23.645 ;
     RECT  33.48 23.371 33.498 23.645 ;
     RECT  35.568 23.549 35.586 23.645 ;
     RECT  38.052 23.467 38.574 23.645 ;
     RECT  40.68 21.731 40.698 23.645 ;
     RECT  42.66 23.419 42.678 23.645 ;
     RECT  46.116 23.419 46.134 23.645 ;
     RECT  50.868 23.467 50.886 23.645 ;
     RECT  53.64 23.515 54.162 23.645 ;
     RECT  57.276 22.445 57.294 23.645 ;
     RECT  58.86 23.515 58.878 23.645 ;
     RECT  61.56 23.515 61.578 23.645 ;
    LAYER M4 ;
     RECT  0.709 2.784 0.805 2.808 ;
     RECT  0.805 2.784 0.901 3.432 ;
     RECT  0.901 2.784 0.997 3.48 ;
     RECT  0.997 2.784 1.141 3.528 ;
     RECT  0.06 10.992 1.141 11.112 ;
     RECT  1.141 2.784 1.189 3.912 ;
     RECT  1.189 2.784 1.477 4.584 ;
     RECT  1.477 2.784 1.573 4.728 ;
     RECT  1.573 2.784 1.765 4.968 ;
     RECT  1.861 20.16 1.957 20.184 ;
     RECT  1.141 10.896 2.041 11.112 ;
     RECT  1.957 20.16 2.053 20.472 ;
     RECT  2.041 10.896 2.113 11.16 ;
     RECT  1.765 2.784 2.149 5.208 ;
     RECT  2.053 20.064 2.149 20.472 ;
     RECT  2.149 2.784 2.245 5.256 ;
     RECT  2.113 10.416 2.257 11.16 ;
     RECT  2.245 2.784 2.293 5.736 ;
     RECT  2.149 19.92 2.293 20.472 ;
     RECT  2.293 23.52 2.321 23.544 ;
     RECT  2.293 0.24 2.341 0.264 ;
     RECT  2.293 2.784 2.408 6.888 ;
     RECT  2.257 10.416 2.408 11.256 ;
     RECT  2.365 12.528 2.408 12.552 ;
     RECT  2.293 19.632 2.408 20.472 ;
     RECT  2.321 23.52 2.437 23.64 ;
     RECT  2.341 0.24 2.533 0.36 ;
     RECT  2.408 2.148 2.629 21.612 ;
     RECT  2.533 0.24 2.677 0.456 ;
     RECT  2.629 2.016 2.704 21.72 ;
     RECT  2.704 2.016 2.725 12.984 ;
     RECT  2.704 19.536 2.725 21.72 ;
     RECT  2.704 17.088 2.765 17.16 ;
     RECT  2.725 19.536 2.915 21.768 ;
     RECT  2.677 0.144 2.917 0.6 ;
     RECT  2.437 23.376 3.089 23.64 ;
     RECT  2.917 0.096 3.109 0.6 ;
     RECT  2.725 1.968 3.109 12.984 ;
     RECT  3.089 23.376 3.157 23.592 ;
     RECT  3.109 0.096 3.197 12.984 ;
     RECT  3.197 0.096 3.395 12.552 ;
     RECT  3.157 22.8 3.395 23.592 ;
     RECT  2.915 19.536 3.413 21.576 ;
     RECT  3.413 19.824 3.436 21.576 ;
     RECT  3.436 19.92 3.484 21.576 ;
     RECT  3.395 22.8 3.635 22.872 ;
     RECT  2.765 17.136 3.701 17.16 ;
     RECT  3.925 17.424 4.129 17.64 ;
     RECT  3.395 1.728 4.165 12.552 ;
     RECT  3.635 22.8 4.211 22.824 ;
     RECT  3.395 0.096 4.357 0.6 ;
     RECT  4.165 1.728 4.357 12.696 ;
     RECT  4.129 17.424 4.489 18.504 ;
     RECT  3.484 19.92 4.489 21.192 ;
     RECT  4.357 0.096 4.537 12.696 ;
     RECT  4.489 17.424 4.777 21.24 ;
     RECT  4.537 0.144 4.849 12.696 ;
     RECT  4.849 0.144 5.108 13.368 ;
     RECT  4.777 17.424 5.108 21.672 ;
     RECT  5.108 0.144 5.125 21.672 ;
     RECT  5.125 0.144 5.221 21.768 ;
     RECT  5.221 0.144 5.404 21.816 ;
     RECT  4.885 23.568 5.413 23.592 ;
     RECT  5.404 17.376 5.465 21.816 ;
     RECT  5.413 23.376 5.509 23.592 ;
     RECT  5.465 17.376 5.555 21.72 ;
     RECT  5.509 23.376 5.651 23.64 ;
     RECT  5.651 23.472 5.753 23.64 ;
     RECT  5.404 0.144 5.785 13.368 ;
     RECT  5.785 0.096 5.869 13.368 ;
     RECT  5.753 23.616 6.221 23.64 ;
     RECT  5.555 17.376 6.973 21.24 ;
     RECT  6.973 17.376 7.189 21.576 ;
     RECT  5.869 0.192 7.331 13.368 ;
     RECT  7.331 1.728 7.369 13.368 ;
     RECT  6.901 14.496 7.369 14.52 ;
     RECT  7.189 17.376 7.369 21.72 ;
     RECT  7.369 17.376 7.475 22.2 ;
     RECT  7.331 0.192 7.621 0.696 ;
     RECT  7.369 1.728 7.808 14.52 ;
     RECT  7.475 17.376 7.808 21.768 ;
     RECT  7.808 1.728 8.104 21.768 ;
     RECT  8.005 23.568 8.291 23.592 ;
     RECT  7.621 0.144 8.341 0.696 ;
     RECT  8.104 1.728 8.341 14.52 ;
     RECT  8.341 0.144 8.389 14.52 ;
     RECT  8.104 17.088 8.54 21.768 ;
     RECT  8.389 0.096 8.561 14.52 ;
     RECT  8.54 17.088 8.627 22.248 ;
     RECT  8.627 17.088 8.993 21.432 ;
     RECT  9.205 23.52 9.253 23.544 ;
     RECT  8.561 0.144 9.385 14.52 ;
     RECT  9.253 23.376 9.394 23.544 ;
     RECT  9.394 23.376 9.587 23.64 ;
     RECT  9.587 23.424 9.677 23.64 ;
     RECT  9.677 23.52 9.683 23.64 ;
     RECT  9.817 16.32 10.141 16.344 ;
     RECT  8.993 17.376 10.393 21.432 ;
     RECT  9.385 0.144 10.508 15.24 ;
     RECT  10.141 16.32 10.508 16.392 ;
     RECT  10.393 17.376 10.508 21.864 ;
     RECT  10.508 0.144 10.646 21.864 ;
     RECT  10.646 0.144 10.835 21.816 ;
     RECT  9.683 23.616 10.865 23.64 ;
     RECT  10.835 0.144 11.026 21.432 ;
     RECT  11.026 0.096 11.125 21.432 ;
     RECT  11.125 0.144 11.893 21.432 ;
     RECT  11.893 0.144 12.178 22.296 ;
     RECT  12.178 0.096 12.961 22.296 ;
     RECT  12.961 0.144 13.045 22.296 ;
     RECT  13.189 23.376 13.285 23.4 ;
     RECT  13.285 23.376 13.573 23.496 ;
     RECT  13.573 23.376 13.619 23.64 ;
     RECT  13.619 23.472 13.667 23.64 ;
     RECT  13.045 0.144 13.745 22.344 ;
     RECT  13.667 23.616 13.745 23.64 ;
     RECT  13.745 0.144 14.069 15.24 ;
     RECT  14.069 0.144 14.245 4.008 ;
     RECT  14.069 5.088 14.857 15.24 ;
     RECT  13.745 16.272 14.857 22.344 ;
     RECT  14.245 0.096 15.205 4.008 ;
     RECT  15.205 0.096 15.541 4.104 ;
     RECT  14.857 5.088 15.541 22.344 ;
     RECT  15.541 0.096 15.661 22.344 ;
     RECT  15.661 0.144 15.769 22.344 ;
     RECT  15.769 0.192 15.827 22.344 ;
     RECT  15.109 23.568 16.165 23.592 ;
     RECT  15.827 1.728 16.213 22.344 ;
     RECT  16.165 23.376 16.213 23.592 ;
     RECT  16.213 1.728 16.499 23.592 ;
     RECT  15.827 0.192 16.829 0.648 ;
     RECT  16.499 1.728 16.829 22.536 ;
     RECT  16.829 0.192 16.933 22.536 ;
     RECT  16.933 0.144 17.555 22.536 ;
     RECT  17.555 0.144 17.651 0.696 ;
     RECT  17.555 1.728 17.989 22.536 ;
     RECT  16.499 23.568 17.989 23.592 ;
     RECT  17.989 1.728 18.13 23.592 ;
     RECT  18.13 1.728 18.137 23.64 ;
     RECT  18.137 1.776 18.253 23.64 ;
     RECT  17.651 0.144 18.323 0.6 ;
     RECT  18.323 0.144 18.418 0.504 ;
     RECT  18.418 0.096 18.419 0.504 ;
     RECT  18.253 1.776 18.433 23.592 ;
     RECT  18.419 0.096 18.541 0.408 ;
     RECT  18.433 1.968 18.611 23.592 ;
     RECT  18.541 0.144 18.803 0.408 ;
     RECT  18.611 1.968 18.904 23.544 ;
     RECT  18.803 0.144 19.043 0.264 ;
     RECT  18.904 1.968 19.117 4.728 ;
     RECT  19.043 0.24 19.379 0.264 ;
     RECT  18.904 5.712 19.573 23.544 ;
     RECT  19.117 1.968 19.861 4.632 ;
     RECT  19.573 5.712 19.901 23.592 ;
     RECT  19.901 23.472 19.907 23.592 ;
     RECT  19.861 1.776 19.955 4.632 ;
     RECT  19.955 1.776 20.101 1.8 ;
     RECT  19.901 5.712 20.108 22.44 ;
     RECT  20.005 0.096 20.153 0.12 ;
     RECT  20.101 1.728 20.441 1.8 ;
     RECT  19.955 2.784 20.677 4.632 ;
     RECT  20.108 5.664 20.677 22.44 ;
     RECT  20.677 2.784 21.085 22.44 ;
     RECT  21.085 1.968 21.445 22.488 ;
     RECT  19.907 23.568 21.541 23.592 ;
     RECT  21.445 1.632 21.604 22.488 ;
     RECT  21.604 1.632 21.665 4.248 ;
     RECT  21.604 5.664 21.725 22.488 ;
     RECT  21.541 23.568 21.725 23.64 ;
     RECT  21.628 0.528 21.829 0.552 ;
     RECT  21.725 5.664 21.875 23.64 ;
     RECT  21.829 0.528 21.925 0.6 ;
     RECT  21.925 0.384 21.973 0.6 ;
     RECT  21.973 0.288 22.021 0.6 ;
     RECT  22.021 0.192 22.213 0.6 ;
     RECT  21.665 1.632 22.213 3.96 ;
     RECT  21.875 23.52 22.285 23.64 ;
     RECT  22.285 23.52 22.307 23.592 ;
     RECT  22.213 0.192 22.405 3.96 ;
     RECT  22.307 23.568 22.595 23.592 ;
     RECT  22.405 0.144 22.789 3.96 ;
     RECT  22.789 0.096 23.077 3.96 ;
     RECT  23.077 0.096 23.101 4.008 ;
     RECT  23.101 0.096 23.105 4.68 ;
     RECT  23.105 0.384 23.281 4.68 ;
     RECT  21.875 5.664 23.281 22.488 ;
     RECT  23.281 0.384 23.315 22.488 ;
     RECT  23.315 0.384 24.133 1.176 ;
     RECT  23.941 23.568 24.229 23.592 ;
     RECT  24.133 0.336 24.277 1.176 ;
     RECT  23.315 2.148 24.277 22.488 ;
     RECT  24.277 0.144 24.613 22.488 ;
     RECT  24.229 23.52 24.613 23.592 ;
     RECT  24.613 0.144 24.754 23.592 ;
     RECT  24.754 0.144 24.844 23.64 ;
     RECT  24.844 23.52 24.851 23.64 ;
     RECT  24.851 23.616 24.877 23.64 ;
     RECT  24.844 0.144 24.977 22.488 ;
     RECT  24.977 0.144 25.235 4.632 ;
     RECT  25.235 0.144 25.445 4.584 ;
     RECT  25.445 0.144 25.553 0.648 ;
     RECT  24.977 5.76 25.571 22.488 ;
     RECT  25.553 0.144 25.957 0.6 ;
     RECT  25.957 0.096 26.165 0.6 ;
     RECT  25.571 5.76 26.245 22.44 ;
     RECT  25.445 1.728 26.389 4.584 ;
     RECT  26.245 5.712 26.389 22.44 ;
     RECT  26.165 0.144 27.013 0.6 ;
     RECT  27.013 0.144 27.109 0.648 ;
     RECT  26.917 23.568 27.203 23.592 ;
     RECT  27.109 0.144 27.385 0.696 ;
     RECT  26.389 1.728 27.385 22.44 ;
     RECT  27.385 0.144 27.781 22.44 ;
     RECT  27.781 0.096 27.865 22.44 ;
     RECT  28.213 23.568 28.837 23.592 ;
     RECT  27.865 0.144 28.979 22.44 ;
     RECT  28.837 23.472 29.701 23.592 ;
     RECT  28.979 1.728 29.704 22.44 ;
     RECT  29.704 16.272 29.797 22.44 ;
     RECT  29.701 23.424 29.797 23.592 ;
     RECT  29.797 16.272 29.842 23.592 ;
     RECT  28.979 0.144 29.941 0.744 ;
     RECT  29.704 1.728 29.941 15.288 ;
     RECT  29.842 16.272 30.131 23.64 ;
     RECT  30.131 23.52 30.161 23.64 ;
     RECT  30.161 23.52 30.179 23.544 ;
     RECT  29.941 0.144 30.469 15.288 ;
     RECT  30.131 16.272 31.877 22.44 ;
     RECT  30.469 0.096 32.108 15.288 ;
     RECT  31.877 16.272 32.108 23.304 ;
     RECT  32.108 0.096 32.389 23.304 ;
     RECT  32.389 0.096 32.404 23.64 ;
     RECT  32.404 0.096 32.819 15.288 ;
     RECT  32.404 16.272 33.539 23.64 ;
     RECT  32.819 0.096 33.545 0.648 ;
     RECT  33.539 23.472 33.587 23.64 ;
     RECT  33.545 0.144 33.925 0.648 ;
     RECT  32.819 1.728 33.925 15.288 ;
     RECT  33.539 16.272 34.789 22.44 ;
     RECT  33.925 0.144 34.808 15.288 ;
     RECT  34.789 16.272 34.808 23.256 ;
     RECT  34.808 0.144 34.981 23.256 ;
     RECT  34.981 0.144 35.104 23.64 ;
     RECT  35.104 0.144 35.173 13.896 ;
     RECT  35.104 16.272 35.267 23.64 ;
     RECT  35.173 0.096 35.309 13.896 ;
     RECT  35.267 23.424 35.315 23.64 ;
     RECT  35.315 23.52 35.345 23.64 ;
     RECT  35.309 0.144 35.363 13.896 ;
     RECT  35.345 23.616 35.597 23.64 ;
     RECT  35.363 0.192 36.313 13.896 ;
     RECT  35.104 15.264 36.313 15.288 ;
     RECT  36.313 0.192 36.899 15.288 ;
     RECT  36.899 0.192 37.237 0.696 ;
     RECT  37.237 23.52 37.333 23.544 ;
     RECT  37.237 0.144 37.361 0.696 ;
     RECT  36.899 1.728 37.508 15.288 ;
     RECT  35.267 16.272 37.508 22.44 ;
     RECT  37.361 0.144 37.523 0.648 ;
     RECT  37.508 1.728 37.861 22.44 ;
     RECT  37.333 23.52 37.861 23.592 ;
     RECT  37.861 1.728 37.865 23.592 ;
     RECT  37.523 0.528 37.901 0.648 ;
     RECT  37.901 0.528 37.937 0.552 ;
     RECT  37.865 5.136 38.002 23.592 ;
     RECT  38.002 5.136 38.003 23.64 ;
     RECT  38.003 23.424 38.541 23.64 ;
     RECT  38.541 23.472 38.585 23.64 ;
     RECT  38.585 23.472 38.627 23.544 ;
     RECT  37.865 1.728 38.723 4.104 ;
     RECT  38.627 23.52 38.723 23.544 ;
     RECT  38.003 5.136 39.089 22.44 ;
     RECT  39.445 0.528 39.589 0.552 ;
     RECT  38.723 1.728 39.589 4.008 ;
     RECT  39.589 0.528 39.701 4.008 ;
     RECT  39.701 1.728 39.781 4.008 ;
     RECT  39.701 0.528 39.925 0.696 ;
     RECT  39.089 5.232 40.069 22.44 ;
     RECT  39.925 23.568 40.069 23.592 ;
     RECT  39.781 1.728 40.208 4.152 ;
     RECT  40.069 5.232 40.208 23.592 ;
     RECT  39.925 0.144 40.211 0.696 ;
     RECT  40.208 1.728 40.307 23.592 ;
     RECT  40.307 23.472 40.357 23.592 ;
     RECT  40.357 23.472 40.709 23.64 ;
     RECT  40.709 23.472 40.739 23.496 ;
     RECT  40.211 0.144 40.741 0.456 ;
     RECT  40.741 0.096 40.979 0.456 ;
     RECT  40.979 0.144 41.027 0.456 ;
     RECT  40.307 1.728 41.701 22.44 ;
     RECT  41.027 0.144 42.181 0.168 ;
     RECT  41.701 1.152 42.181 22.44 ;
     RECT  42.181 0.144 42.373 22.44 ;
     RECT  42.373 0.144 42.517 23.352 ;
     RECT  42.517 0.144 42.565 23.448 ;
     RECT  42.565 0.144 42.61 23.544 ;
     RECT  42.61 0.144 42.725 23.64 ;
     RECT  42.725 1.872 42.733 23.64 ;
     RECT  42.733 1.872 43.331 23.592 ;
     RECT  42.725 0.144 43.57 0.408 ;
     RECT  43.57 0.096 43.669 0.408 ;
     RECT  43.669 0.24 43.717 0.408 ;
     RECT  43.331 1.872 43.733 23.496 ;
     RECT  43.717 0.24 43.811 0.6 ;
     RECT  43.811 0.576 43.813 0.6 ;
     RECT  43.733 1.872 43.909 22.536 ;
     RECT  43.813 0.576 44.101 0.648 ;
     RECT  43.909 1.728 44.101 22.536 ;
     RECT  44.101 0.576 44.237 22.536 ;
     RECT  44.237 0.576 44.243 1.272 ;
     RECT  44.243 0.576 45.277 1.176 ;
     RECT  44.237 2.304 45.277 22.536 ;
     RECT  45.277 0.576 45.301 22.536 ;
     RECT  45.301 0.144 45.385 22.536 ;
     RECT  45.385 0.144 45.925 22.776 ;
     RECT  45.925 0.144 45.973 23.352 ;
     RECT  45.973 0.144 46.021 23.448 ;
     RECT  46.021 0.096 46.066 23.544 ;
     RECT  46.066 0.096 46.115 23.64 ;
     RECT  46.115 1.728 46.145 23.64 ;
     RECT  46.115 0.096 46.163 0.408 ;
     RECT  46.145 23.52 46.163 23.64 ;
     RECT  46.163 23.616 46.189 23.64 ;
     RECT  46.163 0.096 46.253 0.312 ;
     RECT  46.253 0.144 47.219 0.312 ;
     RECT  46.145 1.728 47.477 22.536 ;
     RECT  47.477 2.148 48.085 22.536 ;
     RECT  47.653 23.568 48.085 23.592 ;
     RECT  48.085 2.148 48.275 23.592 ;
     RECT  47.219 0.144 48.421 0.264 ;
     RECT  48.275 23.52 48.803 23.592 ;
     RECT  48.421 0.144 48.86 0.6 ;
     RECT  48.803 23.52 48.899 23.544 ;
     RECT  48.275 2.148 48.941 22.536 ;
     RECT  48.86 0.096 48.947 0.6 ;
     RECT  48.947 0.144 48.997 0.6 ;
     RECT  48.941 1.728 48.997 22.536 ;
     RECT  48.997 0.144 49.061 22.536 ;
     RECT  49.061 0.144 49.169 22.488 ;
     RECT  49.169 0.576 49.385 22.488 ;
     RECT  49.385 1.728 49.421 22.488 ;
     RECT  49.421 1.728 49.637 4.008 ;
     RECT  49.385 0.576 49.997 0.6 ;
     RECT  49.421 5.088 50.204 22.488 ;
     RECT  49.637 1.728 50.725 3.96 ;
     RECT  50.204 5.088 50.773 22.824 ;
     RECT  50.773 5.088 50.813 23.4 ;
     RECT  50.725 1.728 50.821 4.008 ;
     RECT  50.813 5.088 50.821 23.64 ;
     RECT  50.821 1.728 50.897 23.64 ;
     RECT  50.897 1.728 50.915 23.496 ;
     RECT  50.915 1.728 50.963 23.4 ;
     RECT  50.963 1.728 51.059 23.208 ;
     RECT  50.293 0.144 51.205 0.168 ;
     RECT  51.205 0.144 51.445 0.6 ;
     RECT  51.059 1.728 51.445 22.44 ;
     RECT  51.445 0.144 51.634 22.44 ;
     RECT  51.634 0.096 51.731 22.44 ;
     RECT  51.731 0.096 51.733 0.6 ;
     RECT  51.733 0.144 52.403 0.6 ;
     RECT  52.403 0.576 52.693 0.6 ;
     RECT  51.731 1.728 52.693 22.44 ;
     RECT  53.557 23.52 53.585 23.544 ;
     RECT  53.585 23.52 53.701 23.64 ;
     RECT  53.701 23.424 54.131 23.64 ;
     RECT  54.131 23.616 54.173 23.64 ;
     RECT  52.693 0.576 54.277 22.44 ;
     RECT  54.277 0.096 54.851 22.44 ;
     RECT  54.851 0.096 55.189 18.024 ;
     RECT  55.189 0.144 56.099 18.024 ;
     RECT  56.099 0.144 56.185 0.696 ;
     RECT  56.099 1.776 56.408 18.024 ;
     RECT  54.851 19.008 56.408 22.44 ;
     RECT  56.408 1.776 56.485 22.44 ;
     RECT  55.957 23.568 56.485 23.592 ;
     RECT  56.485 1.776 56.704 23.592 ;
     RECT  56.185 0.096 56.819 0.696 ;
     RECT  56.704 19.008 56.869 23.592 ;
     RECT  56.869 19.008 56.915 23.64 ;
     RECT  56.819 0.144 56.953 0.696 ;
     RECT  56.953 0.24 56.963 0.696 ;
     RECT  56.915 23.472 56.963 23.64 ;
     RECT  56.963 0.576 57.061 0.696 ;
     RECT  56.704 1.776 57.061 13.896 ;
     RECT  56.704 15.264 57.161 18.024 ;
     RECT  56.963 23.616 57.305 23.64 ;
     RECT  57.061 0.576 57.347 13.896 ;
     RECT  57.161 15.264 57.485 15.576 ;
     RECT  57.485 15.264 57.923 15.288 ;
     RECT  57.161 16.8 58.019 18.024 ;
     RECT  57.347 1.728 58.741 13.896 ;
     RECT  57.347 0.576 58.837 0.696 ;
     RECT  58.741 1.68 58.837 13.896 ;
     RECT  58.789 23.616 58.837 23.64 ;
     RECT  58.837 23.52 58.889 23.64 ;
     RECT  58.837 0.144 59.108 13.896 ;
     RECT  58.019 16.848 59.108 18.024 ;
     RECT  56.915 19.008 59.108 22.44 ;
     RECT  59.108 0.144 59.404 22.44 ;
     RECT  59.404 0.144 59.525 13.896 ;
     RECT  59.404 16.848 59.845 22.44 ;
     RECT  58.889 23.52 59.845 23.592 ;
     RECT  59.845 16.848 59.933 23.592 ;
     RECT  59.933 16.848 60.035 22.44 ;
     RECT  59.525 0.096 60.275 13.896 ;
     RECT  60.275 0.144 60.437 13.896 ;
     RECT  60.035 17.424 60.467 22.44 ;
     RECT  59.933 23.472 61.189 23.592 ;
     RECT  60.437 0.144 61.379 13.656 ;
     RECT  60.467 18.192 61.405 22.44 ;
     RECT  61.189 23.424 61.405 23.592 ;
     RECT  61.405 18.192 61.429 23.592 ;
     RECT  61.429 17.952 61.477 23.592 ;
     RECT  61.477 17.952 61.622 23.64 ;
     RECT  61.379 0.144 61.765 0.696 ;
     RECT  61.379 1.824 61.808 13.656 ;
     RECT  61.622 17.952 61.808 23.592 ;
     RECT  61.808 1.824 61.811 23.592 ;
     RECT  61.811 1.824 62.104 22.824 ;
     RECT  62.104 1.824 62.243 7.752 ;
     RECT  62.104 17.472 62.243 22.824 ;
     RECT  62.104 10.848 62.273 11.16 ;
     RECT  62.243 18.24 62.309 22.824 ;
     RECT  62.243 1.824 62.381 5.256 ;
     RECT  62.381 2.832 62.435 5.256 ;
     RECT  62.104 8.976 62.435 9.672 ;
     RECT  61.765 0.096 62.437 0.696 ;
     RECT  62.381 1.824 62.437 1.848 ;
     RECT  62.437 0.096 62.483 1.848 ;
     RECT  62.435 3.36 62.483 5.256 ;
     RECT  62.309 18.24 62.483 18.264 ;
     RECT  62.243 6.288 62.489 7.752 ;
     RECT  62.273 10.848 62.525 10.872 ;
     RECT  62.489 7.152 62.531 7.752 ;
     RECT  62.483 0.096 62.579 1.272 ;
     RECT  62.483 3.456 62.579 5.256 ;
     RECT  62.531 7.296 62.579 7.752 ;
     RECT  62.435 9.648 62.627 9.672 ;
     RECT  62.579 7.728 62.633 7.752 ;
     RECT  62.579 3.936 62.641 5.256 ;
     RECT  62.641 3.984 62.675 5.256 ;
     RECT  62.579 1.152 62.723 1.176 ;
     RECT  62.675 3.984 62.723 4.536 ;
     RECT  62.309 19.248 62.785 22.824 ;
     RECT  62.579 0.096 62.812 0.12 ;
     RECT  62.785 19.248 63.059 19.416 ;
     RECT  62.723 3.984 63.137 4.008 ;
     RECT  62.785 20.544 63.251 22.824 ;
     RECT  63.251 22.8 63.347 22.824 ;
     RECT  63.277 19.008 63.443 19.032 ;
     RECT  63.251 20.544 63.539 21.816 ;
     RECT  63.539 21.648 63.635 21.816 ;
     RECT  63.635 21.696 63.731 21.816 ;
     RECT  63.731 21.792 63.827 21.816 ;
     RECT  63.539 20.544 63.923 20.616 ;
     RECT  63.923 20.592 64.019 20.616 ;
    LAYER M5 ;
     RECT  0.72 0.016 62.856 2.819 ;
     RECT  0.816 2.819 62.856 3.443 ;
     RECT  0.912 3.443 62.856 3.491 ;
     RECT  1.008 3.491 62.856 3.539 ;
     RECT  1.2 3.539 62.856 4.019 ;
     RECT  1.2 4.019 62.712 4.547 ;
     RECT  1.2 4.547 62.664 4.595 ;
     RECT  1.488 4.595 62.664 4.739 ;
     RECT  1.584 4.739 62.664 4.979 ;
     RECT  1.776 4.979 62.664 5.219 ;
     RECT  2.16 5.219 62.664 5.267 ;
     RECT  2.256 5.267 62.616 5.747 ;
     RECT  2.304 5.747 62.616 6.323 ;
     RECT  2.4 6.323 62.616 6.899 ;
     RECT  2.4 6.899 35.352 8.003 ;
     RECT  36.384 6.899 62.616 8.003 ;
     RECT  36.432 8.003 62.616 8.531 ;
     RECT  23.664 8.003 35.112 8.579 ;
     RECT  36.432 8.531 57.48 8.579 ;
     RECT  36.672 8.579 57.48 8.675 ;
     RECT  58.944 8.531 62.616 8.867 ;
     RECT  2.4 8.003 22.68 9.013 ;
     RECT  24 8.579 35.112 9.109 ;
     RECT  24 9.109 35.208 9.203 ;
     RECT  36.816 8.675 57.48 9.251 ;
     RECT  33.888 9.203 35.208 9.253 ;
     RECT  36.816 9.251 54.312 9.299 ;
     RECT  58.944 8.867 59.412 9.299 ;
     RECT  2.4 9.013 22.824 9.443 ;
     RECT  42.624 9.299 54.12 9.491 ;
     RECT  2.4 9.443 22.68 9.635 ;
     RECT  36.816 9.299 41.496 9.683 ;
     RECT  60.864 8.867 62.616 9.683 ;
     RECT  2.4 9.635 21.612 9.731 ;
     RECT  33.888 9.253 35.352 9.731 ;
     RECT  42.624 9.491 54.012 9.731 ;
     RECT  2.4 9.731 14.616 9.779 ;
     RECT  26.496 9.203 32.76 9.827 ;
     RECT  40.08 9.683 41.496 9.827 ;
     RECT  34.8 9.731 35.352 9.829 ;
     RECT  36.816 9.683 38.76 9.829 ;
     RECT  55.296 9.251 57.48 9.877 ;
     RECT  29.232 9.827 32.76 10.019 ;
     RECT  55.296 9.877 57.672 10.069 ;
     RECT  42.624 9.731 51.672 10.115 ;
     RECT  29.28 10.019 32.76 10.163 ;
     RECT  15.648 9.731 21.612 10.211 ;
     RECT  34.8 9.829 38.76 10.211 ;
     RECT  40.08 9.827 41.4 10.211 ;
     RECT  44.976 10.115 51.672 10.211 ;
     RECT  22.656 9.635 22.68 10.259 ;
     RECT  26.496 9.827 28.248 10.307 ;
     RECT  34.8 10.211 35.208 10.307 ;
     RECT  36.816 10.211 38.76 10.307 ;
     RECT  15.648 10.211 20.232 10.355 ;
     RECT  24 9.203 25.512 10.355 ;
     RECT  32.1 10.163 32.76 10.357 ;
     RECT  26.496 10.307 27.912 10.403 ;
     RECT  42.624 10.115 43.896 10.451 ;
     RECT  40.08 10.211 41.112 10.595 ;
     RECT  45.024 10.211 51.672 10.595 ;
     RECT  24 10.355 25.416 10.643 ;
     RECT  2.4 9.779 13.608 10.691 ;
     RECT  55.296 10.069 57.864 10.693 ;
     RECT  48.144 10.595 51.672 10.739 ;
     RECT  32.1 10.357 33.048 10.835 ;
     RECT  37.5 10.307 38.76 10.835 ;
     RECT  14.592 9.779 14.616 10.883 ;
     RECT  29.28 10.163 31.128 10.883 ;
     RECT  45.024 10.595 47.112 10.883 ;
     RECT  2.4 10.691 8.112 10.931 ;
     RECT  29.28 10.883 30.216 10.931 ;
     RECT  32.1 10.835 32.952 10.931 ;
     RECT  48.192 10.739 51.672 10.931 ;
     RECT  52.704 9.731 54.012 10.933 ;
     RECT  55.296 10.693 58.104 10.933 ;
     RECT  29.28 10.931 29.712 10.981 ;
     RECT  49.92 10.931 51.672 10.981 ;
     RECT  52.704 10.933 58.104 10.981 ;
     RECT  2.4 10.931 2.808 11.027 ;
     RECT  9.36 10.691 13.608 11.027 ;
     RECT  45.024 10.883 45.912 11.027 ;
     RECT  29.088 10.981 29.712 11.219 ;
     RECT  49.92 10.981 58.104 11.219 ;
     RECT  4.224 10.931 8.112 11.459 ;
     RECT  24 10.643 25.08 11.459 ;
     RECT  40.08 10.595 41.064 11.459 ;
     RECT  42.624 10.451 43.848 11.459 ;
     RECT  49.92 11.219 54.012 11.459 ;
     RECT  15.9 10.355 20.232 11.507 ;
     RECT  26.496 10.403 27.012 11.509 ;
     RECT  48.192 10.931 48.936 11.555 ;
     RECT  32.1 10.931 32.52 11.699 ;
     RECT  40.2 11.459 41.064 11.795 ;
     RECT  45.168 11.027 45.912 11.939 ;
     RECT  42.624 11.459 43.212 11.941 ;
     RECT  6.528 11.459 8.112 12.083 ;
     RECT  45.264 11.939 45.912 12.229 ;
     RECT  47.04 10.883 47.112 12.229 ;
     RECT  48.3 11.555 48.936 12.277 ;
     RECT  49.92 11.459 52.728 12.277 ;
     RECT  4.752 11.459 5.544 12.515 ;
     RECT  9.36 11.027 13.512 12.515 ;
     RECT  4.752 12.515 5.412 12.563 ;
     RECT  42.432 11.941 43.212 12.805 ;
     RECT  48.3 12.277 52.728 13.139 ;
     RECT  53.7 11.459 54.012 13.141 ;
     RECT  26.352 11.509 27.012 13.333 ;
     RECT  53.472 13.141 54.012 13.379 ;
     RECT  24 11.459 24.312 13.381 ;
     RECT  25.68 13.333 27.012 13.381 ;
     RECT  42.432 12.805 44.184 13.381 ;
     RECT  45.264 12.229 47.112 13.381 ;
     RECT  22.8 14.389 22.824 14.723 ;
     RECT  29.4 11.219 29.712 15.205 ;
     RECT  37.5 10.835 37.812 15.205 ;
     RECT  39.168 14.485 39.192 15.205 ;
     RECT  18.48 11.507 20.232 15.347 ;
     RECT  37.5 15.205 39.192 15.781 ;
     RECT  40.2 11.795 40.512 15.781 ;
     RECT  22.608 14.773 22.632 16.069 ;
     RECT  24 13.381 27.012 16.261 ;
     RECT  22.608 16.069 22.824 16.307 ;
     RECT  32.1 11.699 32.412 16.309 ;
     RECT  33.456 13.333 33.48 16.309 ;
     RECT  59.1 9.299 59.412 16.837 ;
     RECT  60.864 9.683 62.568 16.837 ;
     RECT  37.5 15.781 40.512 17.413 ;
     RECT  37.056 17.413 40.512 17.651 ;
     RECT  22.608 16.307 22.632 17.941 ;
     RECT  53.7 13.379 54.012 17.941 ;
     RECT  21.3 10.211 21.612 17.989 ;
     RECT  22.608 17.941 22.872 17.989 ;
     RECT  37.5 17.651 40.512 18.469 ;
     RECT  29.4 15.205 30.12 18.517 ;
     RECT  9.36 12.515 9.384 18.563 ;
     RECT  42.432 13.381 47.112 18.563 ;
     RECT  48.3 13.139 52.344 18.709 ;
     RECT  37.5 18.469 41.448 18.755 ;
     RECT  37.5 18.755 40.512 18.757 ;
     RECT  53.7 17.941 54.168 18.757 ;
     RECT  55.536 11.219 58.104 18.757 ;
     RECT  21.3 17.989 22.872 18.997 ;
     RECT  59.1 16.837 62.568 18.997 ;
     RECT  21.3 18.997 22.968 19.429 ;
     RECT  24 16.261 27.864 19.429 ;
     RECT  2.4 11.027 2.712 19.525 ;
     RECT  3.936 17.605 3.96 19.525 ;
     RECT  21.3 19.429 27.864 19.525 ;
     RECT  29.4 18.517 30.744 19.525 ;
     RECT  48.3 18.709 52.584 19.573 ;
     RECT  2.4 19.525 3.96 19.621 ;
     RECT  5.1 12.563 5.412 19.621 ;
     RECT  6.528 12.083 6.552 19.621 ;
     RECT  15.9 11.507 17.4 19.621 ;
     RECT  18.6 15.347 20.232 19.621 ;
     RECT  34.8 10.307 35.112 19.621 ;
     RECT  36.96 18.757 40.512 19.621 ;
     RECT  32.1 16.309 33.48 19.669 ;
     RECT  34.512 19.621 35.256 19.669 ;
     RECT  14.496 17.893 14.52 19.717 ;
     RECT  15.648 19.621 20.232 19.717 ;
     RECT  14.496 19.717 20.232 19.813 ;
     RECT  21.3 19.525 30.744 19.813 ;
     RECT  10.5 12.515 13.512 19.861 ;
     RECT  14.496 19.813 30.744 19.861 ;
     RECT  32.1 19.669 35.256 19.861 ;
     RECT  36.336 19.621 40.512 19.861 ;
     RECT  53.7 18.757 58.104 19.861 ;
     RECT  59.1 18.997 63.432 19.861 ;
     RECT  2.304 19.621 3.96 19.909 ;
     RECT  5.1 19.621 6.552 19.909 ;
     RECT  7.8 12.083 8.112 19.909 ;
     RECT  10.224 19.861 30.744 19.909 ;
     RECT  31.728 19.861 40.728 19.909 ;
     RECT  42.432 18.563 47.064 19.909 ;
     RECT  48.192 19.573 52.584 19.909 ;
     RECT  53.568 19.861 63.432 19.909 ;
     RECT  42.432 19.909 63.432 20.005 ;
     RECT  2.16 19.909 6.552 20.053 ;
     RECT  2.064 20.053 6.552 20.149 ;
     RECT  7.8 19.909 40.728 20.149 ;
     RECT  42.144 20.005 63.432 20.149 ;
     RECT  7.8 20.149 63.432 20.533 ;
     RECT  7.8 20.533 63.912 20.581 ;
     RECT  7.8 20.581 64.008 21.109 ;
     RECT  1.872 20.149 6.552 21.253 ;
     RECT  7.536 21.109 64.008 21.253 ;
     RECT  1.872 21.253 64.008 23.696 ;
  END
END hbfd_rly_624_NS
END LIBRARY
